VERSION 5.8 ;
BUSBITCHARS "[]" ;
DIVIDERCHAR "/" ;
UNITS
    DATABASE MICRONS 1000 ;
END UNITS

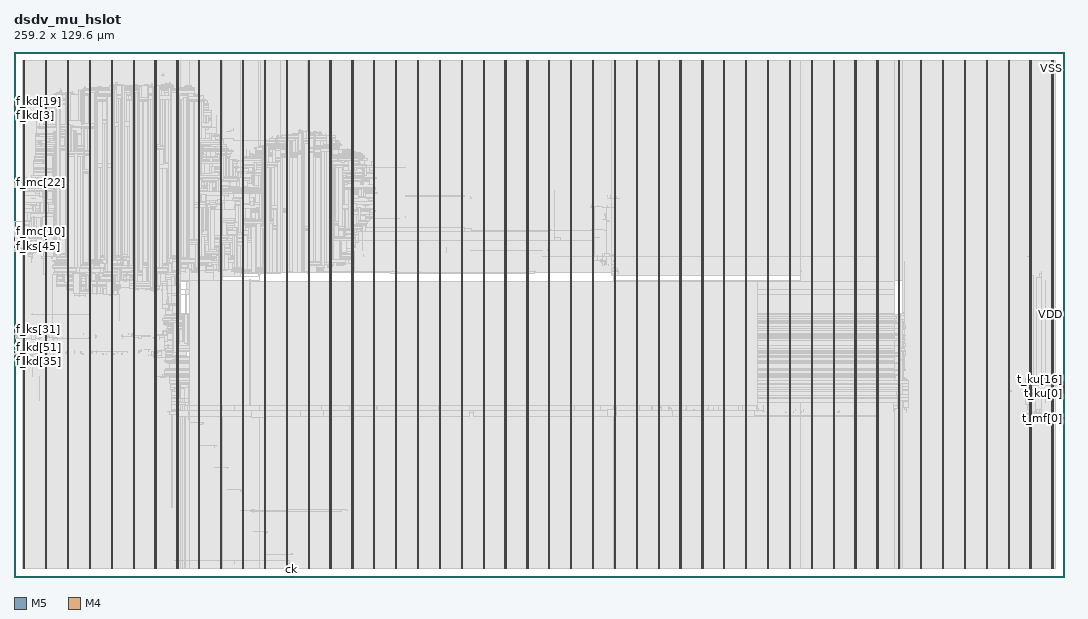
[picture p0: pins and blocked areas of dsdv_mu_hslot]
MACRO dsdv_mu_hslot
  FOREIGN dsdv_mu_hslot 0 0 ;
  CLASS BLOCK ;
  SIZE 259.2 BY 129.6 ;
  PIN ck
    DIRECTION INPUT ;
    USE SIGNAL ;
    PORT
      LAYER M5 ;
        RECT  68.496 0 68.52 0.084 ;
    END
  END ck
  PIN f_kd[0]
    DIRECTION INPUT ;
    USE SIGNAL ;
    PORT
      LAYER M4 ;
        RECT  0 113.52 0.084 113.544 ;
    END
  END f_kd[0]
  PIN f_kd[10]
    DIRECTION INPUT ;
    USE SIGNAL ;
    PORT
      LAYER M4 ;
        RECT  0 114.48 0.084 114.504 ;
    END
  END f_kd[10]
  PIN f_kd[11]
    DIRECTION INPUT ;
    USE SIGNAL ;
    PORT
      LAYER M4 ;
        RECT  0 114.576 0.084 114.6 ;
    END
  END f_kd[11]
  PIN f_kd[12]
    DIRECTION INPUT ;
    USE SIGNAL ;
    PORT
      LAYER M4 ;
        RECT  0 114.672 0.084 114.696 ;
    END
  END f_kd[12]
  PIN f_kd[13]
    DIRECTION INPUT ;
    USE SIGNAL ;
    PORT
      LAYER M4 ;
        RECT  0 114.768 0.084 114.792 ;
    END
  END f_kd[13]
  PIN f_kd[14]
    DIRECTION INPUT ;
    USE SIGNAL ;
    PORT
      LAYER M4 ;
        RECT  0 114.864 0.084 114.888 ;
    END
  END f_kd[14]
  PIN f_kd[15]
    DIRECTION INPUT ;
    USE SIGNAL ;
    PORT
      LAYER M4 ;
        RECT  0 114.96 0.084 114.984 ;
    END
  END f_kd[15]
  PIN f_kd[16]
    DIRECTION INPUT ;
    USE SIGNAL ;
    PORT
      LAYER M4 ;
        RECT  0 115.056 0.084 115.08 ;
    END
  END f_kd[16]
  PIN f_kd[17]
    DIRECTION INPUT ;
    USE SIGNAL ;
    PORT
      LAYER M4 ;
        RECT  0 115.152 0.084 115.176 ;
    END
  END f_kd[17]
  PIN f_kd[18]
    DIRECTION INPUT ;
    USE SIGNAL ;
    PORT
      LAYER M4 ;
        RECT  0 115.248 0.084 115.272 ;
    END
  END f_kd[18]
  PIN f_kd[19]
    DIRECTION INPUT ;
    USE SIGNAL ;
    PORT
      LAYER M4 ;
        RECT  0 115.344 0.084 115.368 ;
    END
  END f_kd[19]
  PIN f_kd[1]
    DIRECTION INPUT ;
    USE SIGNAL ;
    PORT
      LAYER M4 ;
        RECT  0 113.616 0.084 113.64 ;
    END
  END f_kd[1]
  PIN f_kd[20]
    DIRECTION INPUT ;
    USE SIGNAL ;
    PORT
      LAYER M4 ;
        RECT  0 115.44 0.084 115.464 ;
    END
  END f_kd[20]
  PIN f_kd[21]
    DIRECTION INPUT ;
    USE SIGNAL ;
    PORT
      LAYER M4 ;
        RECT  0 115.536 0.084 115.56 ;
    END
  END f_kd[21]
  PIN f_kd[22]
    DIRECTION INPUT ;
    USE SIGNAL ;
    PORT
      LAYER M4 ;
        RECT  0 115.632 0.084 115.656 ;
    END
  END f_kd[22]
  PIN f_kd[23]
    DIRECTION INPUT ;
    USE SIGNAL ;
    PORT
      LAYER M4 ;
        RECT  0 115.728 0.084 115.752 ;
    END
  END f_kd[23]
  PIN f_kd[24]
    DIRECTION INPUT ;
    USE SIGNAL ;
    PORT
      LAYER M4 ;
        RECT  0 115.824 0.084 115.848 ;
    END
  END f_kd[24]
  PIN f_kd[25]
    DIRECTION INPUT ;
    USE SIGNAL ;
    PORT
      LAYER M4 ;
        RECT  0 115.92 0.084 115.944 ;
    END
  END f_kd[25]
  PIN f_kd[26]
    DIRECTION INPUT ;
    USE SIGNAL ;
    PORT
      LAYER M4 ;
        RECT  0 116.016 0.084 116.04 ;
    END
  END f_kd[26]
  PIN f_kd[27]
    DIRECTION INPUT ;
    USE SIGNAL ;
    PORT
      LAYER M4 ;
        RECT  0 116.112 0.084 116.136 ;
    END
  END f_kd[27]
  PIN f_kd[28]
    DIRECTION INPUT ;
    USE SIGNAL ;
    PORT
      LAYER M4 ;
        RECT  0 116.208 0.084 116.232 ;
    END
  END f_kd[28]
  PIN f_kd[29]
    DIRECTION INPUT ;
    USE SIGNAL ;
    PORT
      LAYER M4 ;
        RECT  0 116.304 0.084 116.328 ;
    END
  END f_kd[29]
  PIN f_kd[2]
    DIRECTION INPUT ;
    USE SIGNAL ;
    PORT
      LAYER M4 ;
        RECT  0 113.712 0.084 113.736 ;
    END
  END f_kd[2]
  PIN f_kd[30]
    DIRECTION INPUT ;
    USE SIGNAL ;
    PORT
      LAYER M4 ;
        RECT  0 116.4 0.084 116.424 ;
    END
  END f_kd[30]
  PIN f_kd[31]
    DIRECTION INPUT ;
    USE SIGNAL ;
    PORT
      LAYER M4 ;
        RECT  0 116.496 0.084 116.52 ;
    END
  END f_kd[31]
  PIN f_kd[32]
    DIRECTION INPUT ;
    USE SIGNAL ;
    PORT
      LAYER M4 ;
        RECT  0 52.848 0.084 52.872 ;
    END
  END f_kd[32]
  PIN f_kd[33]
    DIRECTION INPUT ;
    USE SIGNAL ;
    PORT
      LAYER M4 ;
        RECT  0 52.944 0.084 52.968 ;
    END
  END f_kd[33]
  PIN f_kd[34]
    DIRECTION INPUT ;
    USE SIGNAL ;
    PORT
      LAYER M4 ;
        RECT  0 53.04 0.084 53.064 ;
    END
  END f_kd[34]
  PIN f_kd[35]
    DIRECTION INPUT ;
    USE SIGNAL ;
    PORT
      LAYER M4 ;
        RECT  0 53.136 0.084 53.16 ;
    END
  END f_kd[35]
  PIN f_kd[36]
    DIRECTION INPUT ;
    USE SIGNAL ;
    PORT
      LAYER M4 ;
        RECT  0 53.232 0.084 53.256 ;
    END
  END f_kd[36]
  PIN f_kd[37]
    DIRECTION INPUT ;
    USE SIGNAL ;
    PORT
      LAYER M4 ;
        RECT  0 53.328 0.084 53.352 ;
    END
  END f_kd[37]
  PIN f_kd[38]
    DIRECTION INPUT ;
    USE SIGNAL ;
    PORT
      LAYER M4 ;
        RECT  0 53.424 0.084 53.448 ;
    END
  END f_kd[38]
  PIN f_kd[39]
    DIRECTION INPUT ;
    USE SIGNAL ;
    PORT
      LAYER M4 ;
        RECT  0 53.52 0.084 53.544 ;
    END
  END f_kd[39]
  PIN f_kd[3]
    DIRECTION INPUT ;
    USE SIGNAL ;
    PORT
      LAYER M4 ;
        RECT  0 113.808 0.084 113.832 ;
    END
  END f_kd[3]
  PIN f_kd[40]
    DIRECTION INPUT ;
    USE SIGNAL ;
    PORT
      LAYER M4 ;
        RECT  0 53.616 0.084 53.64 ;
    END
  END f_kd[40]
  PIN f_kd[41]
    DIRECTION INPUT ;
    USE SIGNAL ;
    PORT
      LAYER M4 ;
        RECT  0 53.712 0.084 53.736 ;
    END
  END f_kd[41]
  PIN f_kd[42]
    DIRECTION INPUT ;
    USE SIGNAL ;
    PORT
      LAYER M4 ;
        RECT  0 53.808 0.084 53.832 ;
    END
  END f_kd[42]
  PIN f_kd[43]
    DIRECTION INPUT ;
    USE SIGNAL ;
    PORT
      LAYER M4 ;
        RECT  0 53.904 0.084 53.928 ;
    END
  END f_kd[43]
  PIN f_kd[44]
    DIRECTION INPUT ;
    USE SIGNAL ;
    PORT
      LAYER M4 ;
        RECT  0 54 0.084 54.024 ;
    END
  END f_kd[44]
  PIN f_kd[45]
    DIRECTION INPUT ;
    USE SIGNAL ;
    PORT
      LAYER M4 ;
        RECT  0 54.096 0.084 54.12 ;
    END
  END f_kd[45]
  PIN f_kd[46]
    DIRECTION INPUT ;
    USE SIGNAL ;
    PORT
      LAYER M4 ;
        RECT  0 54.192 0.084 54.216 ;
    END
  END f_kd[46]
  PIN f_kd[47]
    DIRECTION INPUT ;
    USE SIGNAL ;
    PORT
      LAYER M4 ;
        RECT  0 54.288 0.084 54.312 ;
    END
  END f_kd[47]
  PIN f_kd[48]
    DIRECTION INPUT ;
    USE SIGNAL ;
    PORT
      LAYER M4 ;
        RECT  0 54.384 0.084 54.408 ;
    END
  END f_kd[48]
  PIN f_kd[49]
    DIRECTION INPUT ;
    USE SIGNAL ;
    PORT
      LAYER M4 ;
        RECT  0 54.48 0.084 54.504 ;
    END
  END f_kd[49]
  PIN f_kd[4]
    DIRECTION INPUT ;
    USE SIGNAL ;
    PORT
      LAYER M4 ;
        RECT  0 113.904 0.084 113.928 ;
    END
  END f_kd[4]
  PIN f_kd[50]
    DIRECTION INPUT ;
    USE SIGNAL ;
    PORT
      LAYER M4 ;
        RECT  0 54.576 0.084 54.6 ;
    END
  END f_kd[50]
  PIN f_kd[51]
    DIRECTION INPUT ;
    USE SIGNAL ;
    PORT
      LAYER M4 ;
        RECT  0 54.672 0.084 54.696 ;
    END
  END f_kd[51]
  PIN f_kd[52]
    DIRECTION INPUT ;
    USE SIGNAL ;
    PORT
      LAYER M4 ;
        RECT  0 54.768 0.084 54.792 ;
    END
  END f_kd[52]
  PIN f_kd[53]
    DIRECTION INPUT ;
    USE SIGNAL ;
    PORT
      LAYER M4 ;
        RECT  0 54.864 0.084 54.888 ;
    END
  END f_kd[53]
  PIN f_kd[5]
    DIRECTION INPUT ;
    USE SIGNAL ;
    PORT
      LAYER M4 ;
        RECT  0 114 0.084 114.024 ;
    END
  END f_kd[5]
  PIN f_kd[6]
    DIRECTION INPUT ;
    USE SIGNAL ;
    PORT
      LAYER M4 ;
        RECT  0 114.096 0.084 114.12 ;
    END
  END f_kd[6]
  PIN f_kd[7]
    DIRECTION INPUT ;
    USE SIGNAL ;
    PORT
      LAYER M4 ;
        RECT  0 114.192 0.084 114.216 ;
    END
  END f_kd[7]
  PIN f_kd[8]
    DIRECTION INPUT ;
    USE SIGNAL ;
    PORT
      LAYER M4 ;
        RECT  0 114.288 0.084 114.312 ;
    END
  END f_kd[8]
  PIN f_kd[9]
    DIRECTION INPUT ;
    USE SIGNAL ;
    PORT
      LAYER M4 ;
        RECT  0 114.384 0.084 114.408 ;
    END
  END f_kd[9]
  PIN f_ks[0]
    DIRECTION INPUT ;
    USE SIGNAL ;
    PORT
      LAYER M4 ;
        RECT  0 54.96 0.084 54.984 ;
    END
  END f_ks[0]
  PIN f_ks[10]
    DIRECTION INPUT ;
    USE SIGNAL ;
    PORT
      LAYER M4 ;
        RECT  0 58.992 0.084 59.016 ;
    END
  END f_ks[10]
  PIN f_ks[11]
    DIRECTION INPUT ;
    USE SIGNAL ;
    PORT
      LAYER M4 ;
        RECT  0 59.088 0.084 59.112 ;
    END
  END f_ks[11]
  PIN f_ks[12]
    DIRECTION INPUT ;
    USE SIGNAL ;
    PORT
      LAYER M4 ;
        RECT  0 59.184 0.084 59.208 ;
    END
  END f_ks[12]
  PIN f_ks[13]
    DIRECTION INPUT ;
    USE SIGNAL ;
    PORT
      LAYER M4 ;
        RECT  0 59.28 0.084 59.304 ;
    END
  END f_ks[13]
  PIN f_ks[14]
    DIRECTION INPUT ;
    USE SIGNAL ;
    PORT
      LAYER M4 ;
        RECT  0 59.376 0.084 59.4 ;
    END
  END f_ks[14]
  PIN f_ks[15]
    DIRECTION INPUT ;
    USE SIGNAL ;
    PORT
      LAYER M4 ;
        RECT  0 59.472 0.084 59.496 ;
    END
  END f_ks[15]
  PIN f_ks[16]
    DIRECTION INPUT ;
    USE SIGNAL ;
    PORT
      LAYER M4 ;
        RECT  0 59.568 0.084 59.592 ;
    END
  END f_ks[16]
  PIN f_ks[17]
    DIRECTION INPUT ;
    USE SIGNAL ;
    PORT
      LAYER M4 ;
        RECT  0 59.664 0.084 59.688 ;
    END
  END f_ks[17]
  PIN f_ks[18]
    DIRECTION INPUT ;
    USE SIGNAL ;
    PORT
      LAYER M4 ;
        RECT  0 59.76 0.084 59.784 ;
    END
  END f_ks[18]
  PIN f_ks[19]
    DIRECTION INPUT ;
    USE SIGNAL ;
    PORT
      LAYER M4 ;
        RECT  0 59.856 0.084 59.88 ;
    END
  END f_ks[19]
  PIN f_ks[1]
    DIRECTION INPUT ;
    USE SIGNAL ;
    PORT
      LAYER M4 ;
        RECT  0 55.056 0.084 55.08 ;
    END
  END f_ks[1]
  PIN f_ks[20]
    DIRECTION INPUT ;
    USE SIGNAL ;
    PORT
      LAYER M4 ;
        RECT  0 59.952 0.084 59.976 ;
    END
  END f_ks[20]
  PIN f_ks[21]
    DIRECTION INPUT ;
    USE SIGNAL ;
    PORT
      LAYER M4 ;
        RECT  0 60.048 0.084 60.072 ;
    END
  END f_ks[21]
  PIN f_ks[22]
    DIRECTION INPUT ;
    USE SIGNAL ;
    PORT
      LAYER M4 ;
        RECT  0 60.144 0.084 60.168 ;
    END
  END f_ks[22]
  PIN f_ks[23]
    DIRECTION INPUT ;
    USE SIGNAL ;
    PORT
      LAYER M4 ;
        RECT  0 60.24 0.084 60.264 ;
    END
  END f_ks[23]
  PIN f_ks[24]
    DIRECTION INPUT ;
    USE SIGNAL ;
    PORT
      LAYER M4 ;
        RECT  0 60.336 0.084 60.36 ;
    END
  END f_ks[24]
  PIN f_ks[25]
    DIRECTION INPUT ;
    USE SIGNAL ;
    PORT
      LAYER M4 ;
        RECT  0 60.432 0.084 60.456 ;
    END
  END f_ks[25]
  PIN f_ks[26]
    DIRECTION INPUT ;
    USE SIGNAL ;
    PORT
      LAYER M4 ;
        RECT  0 60.528 0.084 60.552 ;
    END
  END f_ks[26]
  PIN f_ks[27]
    DIRECTION INPUT ;
    USE SIGNAL ;
    PORT
      LAYER M4 ;
        RECT  0 60.624 0.084 60.648 ;
    END
  END f_ks[27]
  PIN f_ks[28]
    DIRECTION INPUT ;
    USE SIGNAL ;
    PORT
      LAYER M4 ;
        RECT  0 60.72 0.084 60.744 ;
    END
  END f_ks[28]
  PIN f_ks[29]
    DIRECTION INPUT ;
    USE SIGNAL ;
    PORT
      LAYER M4 ;
        RECT  0 60.816 0.084 60.84 ;
    END
  END f_ks[29]
  PIN f_ks[2]
    DIRECTION INPUT ;
    USE SIGNAL ;
    PORT
      LAYER M4 ;
        RECT  0 55.152 0.084 55.176 ;
    END
  END f_ks[2]
  PIN f_ks[30]
    DIRECTION INPUT ;
    USE SIGNAL ;
    PORT
      LAYER M4 ;
        RECT  0 60.912 0.084 60.936 ;
    END
  END f_ks[30]
  PIN f_ks[31]
    DIRECTION INPUT ;
    USE SIGNAL ;
    PORT
      LAYER M4 ;
        RECT  0 61.008 0.084 61.032 ;
    END
  END f_ks[31]
  PIN f_ks[32]
    DIRECTION INPUT ;
    USE SIGNAL ;
    PORT
      LAYER M4 ;
        RECT  0 61.104 0.084 61.128 ;
    END
  END f_ks[32]
  PIN f_ks[33]
    DIRECTION INPUT ;
    USE SIGNAL ;
    PORT
      LAYER M4 ;
        RECT  0 61.2 0.084 61.224 ;
    END
  END f_ks[33]
  PIN f_ks[34]
    DIRECTION INPUT ;
    USE SIGNAL ;
    PORT
      LAYER M4 ;
        RECT  0 61.296 0.084 61.32 ;
    END
  END f_ks[34]
  PIN f_ks[35]
    DIRECTION INPUT ;
    USE SIGNAL ;
    PORT
      LAYER M4 ;
        RECT  0 61.392 0.084 61.416 ;
    END
  END f_ks[35]
  PIN f_ks[36]
    DIRECTION INPUT ;
    USE SIGNAL ;
    PORT
      LAYER M4 ;
        RECT  0 61.488 0.084 61.512 ;
    END
  END f_ks[36]
  PIN f_ks[37]
    DIRECTION INPUT ;
    USE SIGNAL ;
    PORT
      LAYER M4 ;
        RECT  0 61.584 0.084 61.608 ;
    END
  END f_ks[37]
  PIN f_ks[38]
    DIRECTION INPUT ;
    USE SIGNAL ;
    PORT
      LAYER M4 ;
        RECT  0 61.68 0.084 61.704 ;
    END
  END f_ks[38]
  PIN f_ks[39]
    DIRECTION INPUT ;
    USE SIGNAL ;
    PORT
      LAYER M4 ;
        RECT  0 61.776 0.084 61.8 ;
    END
  END f_ks[39]
  PIN f_ks[3]
    DIRECTION INPUT ;
    USE SIGNAL ;
    PORT
      LAYER M4 ;
        RECT  0 55.248 0.084 55.272 ;
    END
  END f_ks[3]
  PIN f_ks[40]
    DIRECTION INPUT ;
    USE SIGNAL ;
    PORT
      LAYER M4 ;
        RECT  0 61.872 0.084 61.896 ;
    END
  END f_ks[40]
  PIN f_ks[41]
    DIRECTION INPUT ;
    USE SIGNAL ;
    PORT
      LAYER M4 ;
        RECT  0 61.968 0.084 61.992 ;
    END
  END f_ks[41]
  PIN f_ks[42]
    DIRECTION INPUT ;
    USE SIGNAL ;
    PORT
      LAYER M4 ;
        RECT  0 81.264 0.084 81.288 ;
    END
  END f_ks[42]
  PIN f_ks[43]
    DIRECTION INPUT ;
    USE SIGNAL ;
    PORT
      LAYER M4 ;
        RECT  0 81.36 0.084 81.384 ;
    END
  END f_ks[43]
  PIN f_ks[44]
    DIRECTION INPUT ;
    USE SIGNAL ;
    PORT
      LAYER M4 ;
        RECT  0 81.456 0.084 81.48 ;
    END
  END f_ks[44]
  PIN f_ks[45]
    DIRECTION INPUT ;
    USE SIGNAL ;
    PORT
      LAYER M4 ;
        RECT  0 81.552 0.084 81.576 ;
    END
  END f_ks[45]
  PIN f_ks[46]
    DIRECTION INPUT ;
    USE SIGNAL ;
    PORT
      LAYER M4 ;
        RECT  0 81.648 0.084 81.672 ;
    END
  END f_ks[46]
  PIN f_ks[47]
    DIRECTION INPUT ;
    USE SIGNAL ;
    PORT
      LAYER M4 ;
        RECT  0 81.744 0.084 81.768 ;
    END
  END f_ks[47]
  PIN f_ks[48]
    DIRECTION INPUT ;
    USE SIGNAL ;
    PORT
      LAYER M4 ;
        RECT  0 81.84 0.084 81.864 ;
    END
  END f_ks[48]
  PIN f_ks[49]
    DIRECTION INPUT ;
    USE SIGNAL ;
    PORT
      LAYER M4 ;
        RECT  0 81.936 0.084 81.96 ;
    END
  END f_ks[49]
  PIN f_ks[4]
    DIRECTION INPUT ;
    USE SIGNAL ;
    PORT
      LAYER M4 ;
        RECT  0 55.344 0.084 55.368 ;
    END
  END f_ks[4]
  PIN f_ks[50]
    DIRECTION INPUT ;
    USE SIGNAL ;
    PORT
      LAYER M4 ;
        RECT  0 82.032 0.084 82.056 ;
    END
  END f_ks[50]
  PIN f_ks[51]
    DIRECTION INPUT ;
    USE SIGNAL ;
    PORT
      LAYER M4 ;
        RECT  0 82.128 0.084 82.152 ;
    END
  END f_ks[51]
  PIN f_ks[52]
    DIRECTION INPUT ;
    USE SIGNAL ;
    PORT
      LAYER M4 ;
        RECT  0 82.224 0.084 82.248 ;
    END
  END f_ks[52]
  PIN f_ks[5]
    DIRECTION INPUT ;
    USE SIGNAL ;
    PORT
      LAYER M4 ;
        RECT  0 55.44 0.084 55.464 ;
    END
  END f_ks[5]
  PIN f_ks[6]
    DIRECTION INPUT ;
    USE SIGNAL ;
    PORT
      LAYER M4 ;
        RECT  0 55.536 0.084 55.56 ;
    END
  END f_ks[6]
  PIN f_ks[7]
    DIRECTION INPUT ;
    USE SIGNAL ;
    PORT
      LAYER M4 ;
        RECT  0 55.632 0.084 55.656 ;
    END
  END f_ks[7]
  PIN f_ks[8]
    DIRECTION INPUT ;
    USE SIGNAL ;
    PORT
      LAYER M4 ;
        RECT  0 55.728 0.084 55.752 ;
    END
  END f_ks[8]
  PIN f_ks[9]
    DIRECTION INPUT ;
    USE SIGNAL ;
    PORT
      LAYER M4 ;
        RECT  0 55.824 0.084 55.848 ;
    END
  END f_ks[9]
  PIN f_mc[0]
    DIRECTION INPUT ;
    USE SIGNAL ;
    PORT
      LAYER M4 ;
        RECT  0 82.32 0.084 82.344 ;
    END
  END f_mc[0]
  PIN f_mc[10]
    DIRECTION INPUT ;
    USE SIGNAL ;
    PORT
      LAYER M4 ;
        RECT  0 83.28 0.084 83.304 ;
    END
  END f_mc[10]
  PIN f_mc[11]
    DIRECTION INPUT ;
    USE SIGNAL ;
    PORT
      LAYER M4 ;
        RECT  0 83.376 0.084 83.4 ;
    END
  END f_mc[11]
  PIN f_mc[12]
    DIRECTION INPUT ;
    USE SIGNAL ;
    PORT
      LAYER M4 ;
        RECT  0 83.472 0.084 83.496 ;
    END
  END f_mc[12]
  PIN f_mc[13]
    DIRECTION INPUT ;
    USE SIGNAL ;
    PORT
      LAYER M4 ;
        RECT  0 83.568 0.084 83.592 ;
    END
  END f_mc[13]
  PIN f_mc[14]
    DIRECTION INPUT ;
    USE SIGNAL ;
    PORT
      LAYER M4 ;
        RECT  0 83.664 0.084 83.688 ;
    END
  END f_mc[14]
  PIN f_mc[15]
    DIRECTION INPUT ;
    USE SIGNAL ;
    PORT
      LAYER M4 ;
        RECT  0 83.76 0.084 83.784 ;
    END
  END f_mc[15]
  PIN f_mc[16]
    DIRECTION INPUT ;
    USE SIGNAL ;
    PORT
      LAYER M4 ;
        RECT  0 83.856 0.084 83.88 ;
    END
  END f_mc[16]
  PIN f_mc[17]
    DIRECTION INPUT ;
    USE SIGNAL ;
    PORT
      LAYER M4 ;
        RECT  0 83.952 0.084 83.976 ;
    END
  END f_mc[17]
  PIN f_mc[18]
    DIRECTION INPUT ;
    USE SIGNAL ;
    PORT
      LAYER M4 ;
        RECT  0 84.048 0.084 84.072 ;
    END
  END f_mc[18]
  PIN f_mc[19]
    DIRECTION INPUT ;
    USE SIGNAL ;
    PORT
      LAYER M4 ;
        RECT  0 84.144 0.084 84.168 ;
    END
  END f_mc[19]
  PIN f_mc[1]
    DIRECTION INPUT ;
    USE SIGNAL ;
    PORT
      LAYER M4 ;
        RECT  0 82.416 0.084 82.44 ;
    END
  END f_mc[1]
  PIN f_mc[20]
    DIRECTION INPUT ;
    USE SIGNAL ;
    PORT
      LAYER M4 ;
        RECT  0 84.24 0.084 84.264 ;
    END
  END f_mc[20]
  PIN f_mc[21]
    DIRECTION INPUT ;
    USE SIGNAL ;
    PORT
      LAYER M4 ;
        RECT  0 97.2 0.084 97.224 ;
    END
  END f_mc[21]
  PIN f_mc[22]
    DIRECTION INPUT ;
    USE SIGNAL ;
    PORT
      LAYER M4 ;
        RECT  0 97.296 0.084 97.32 ;
    END
  END f_mc[22]
  PIN f_mc[23]
    DIRECTION INPUT ;
    USE SIGNAL ;
    PORT
      LAYER M4 ;
        RECT  0 97.392 0.084 97.416 ;
    END
  END f_mc[23]
  PIN f_mc[24]
    DIRECTION INPUT ;
    USE SIGNAL ;
    PORT
      LAYER M4 ;
        RECT  0 97.488 0.084 97.512 ;
    END
  END f_mc[24]
  PIN f_mc[25]
    DIRECTION INPUT ;
    USE SIGNAL ;
    PORT
      LAYER M4 ;
        RECT  0 97.584 0.084 97.608 ;
    END
  END f_mc[25]
  PIN f_mc[2]
    DIRECTION INPUT ;
    USE SIGNAL ;
    PORT
      LAYER M4 ;
        RECT  0 82.512 0.084 82.536 ;
    END
  END f_mc[2]
  PIN f_mc[3]
    DIRECTION INPUT ;
    USE SIGNAL ;
    PORT
      LAYER M4 ;
        RECT  0 82.608 0.084 82.632 ;
    END
  END f_mc[3]
  PIN f_mc[4]
    DIRECTION INPUT ;
    USE SIGNAL ;
    PORT
      LAYER M4 ;
        RECT  0 82.704 0.084 82.728 ;
    END
  END f_mc[4]
  PIN f_mc[5]
    DIRECTION INPUT ;
    USE SIGNAL ;
    PORT
      LAYER M4 ;
        RECT  0 82.8 0.084 82.824 ;
    END
  END f_mc[5]
  PIN f_mc[6]
    DIRECTION INPUT ;
    USE SIGNAL ;
    PORT
      LAYER M4 ;
        RECT  0 82.896 0.084 82.92 ;
    END
  END f_mc[6]
  PIN f_mc[7]
    DIRECTION INPUT ;
    USE SIGNAL ;
    PORT
      LAYER M4 ;
        RECT  0 82.992 0.084 83.016 ;
    END
  END f_mc[7]
  PIN f_mc[8]
    DIRECTION INPUT ;
    USE SIGNAL ;
    PORT
      LAYER M4 ;
        RECT  0 83.088 0.084 83.112 ;
    END
  END f_mc[8]
  PIN f_mc[9]
    DIRECTION INPUT ;
    USE SIGNAL ;
    PORT
      LAYER M4 ;
        RECT  0 83.184 0.084 83.208 ;
    END
  END f_mc[9]
  PIN rst_n
    DIRECTION INPUT ;
    USE SIGNAL ;
    PORT
      LAYER M5 ;
        RECT  68.592 0 68.616 0.084 ;
    END
  END rst_n
  PIN t_ku[0]
    DIRECTION OUTPUT ;
    USE SIGNAL ;
    PORT
      LAYER M4 ;
        RECT  259.116 45.264 259.2 45.288 ;
    END
  END t_ku[0]
  PIN t_ku[10]
    DIRECTION OUTPUT ;
    USE SIGNAL ;
    PORT
      LAYER M4 ;
        RECT  259.116 46.224 259.2 46.248 ;
    END
  END t_ku[10]
  PIN t_ku[11]
    DIRECTION OUTPUT ;
    USE SIGNAL ;
    PORT
      LAYER M4 ;
        RECT  259.116 46.32 259.2 46.344 ;
    END
  END t_ku[11]
  PIN t_ku[12]
    DIRECTION OUTPUT ;
    USE SIGNAL ;
    PORT
      LAYER M4 ;
        RECT  259.116 46.416 259.2 46.44 ;
    END
  END t_ku[12]
  PIN t_ku[13]
    DIRECTION OUTPUT ;
    USE SIGNAL ;
    PORT
      LAYER M4 ;
        RECT  259.116 46.512 259.2 46.536 ;
    END
  END t_ku[13]
  PIN t_ku[14]
    DIRECTION OUTPUT ;
    USE SIGNAL ;
    PORT
      LAYER M4 ;
        RECT  259.116 46.608 259.2 46.632 ;
    END
  END t_ku[14]
  PIN t_ku[15]
    DIRECTION OUTPUT ;
    USE SIGNAL ;
    PORT
      LAYER M4 ;
        RECT  259.116 46.704 259.2 46.728 ;
    END
  END t_ku[15]
  PIN t_ku[16]
    DIRECTION OUTPUT ;
    USE SIGNAL ;
    PORT
      LAYER M4 ;
        RECT  259.116 46.8 259.2 46.824 ;
    END
  END t_ku[16]
  PIN t_ku[17]
    DIRECTION OUTPUT ;
    USE SIGNAL ;
    PORT
      LAYER M4 ;
        RECT  259.116 46.896 259.2 46.92 ;
    END
  END t_ku[17]
  PIN t_ku[18]
    DIRECTION OUTPUT ;
    USE SIGNAL ;
    PORT
      LAYER M4 ;
        RECT  259.116 46.992 259.2 47.016 ;
    END
  END t_ku[18]
  PIN t_ku[19]
    DIRECTION OUTPUT ;
    USE SIGNAL ;
    PORT
      LAYER M4 ;
        RECT  259.116 47.088 259.2 47.112 ;
    END
  END t_ku[19]
  PIN t_ku[1]
    DIRECTION OUTPUT ;
    USE SIGNAL ;
    PORT
      LAYER M4 ;
        RECT  259.116 45.36 259.2 45.384 ;
    END
  END t_ku[1]
  PIN t_ku[20]
    DIRECTION OUTPUT ;
    USE SIGNAL ;
    PORT
      LAYER M4 ;
        RECT  259.116 47.184 259.2 47.208 ;
    END
  END t_ku[20]
  PIN t_ku[21]
    DIRECTION OUTPUT ;
    USE SIGNAL ;
    PORT
      LAYER M4 ;
        RECT  259.116 47.28 259.2 47.304 ;
    END
  END t_ku[21]
  PIN t_ku[22]
    DIRECTION OUTPUT ;
    USE SIGNAL ;
    PORT
      LAYER M4 ;
        RECT  259.116 47.376 259.2 47.4 ;
    END
  END t_ku[22]
  PIN t_ku[23]
    DIRECTION OUTPUT ;
    USE SIGNAL ;
    PORT
      LAYER M4 ;
        RECT  259.116 47.472 259.2 47.496 ;
    END
  END t_ku[23]
  PIN t_ku[24]
    DIRECTION OUTPUT ;
    USE SIGNAL ;
    PORT
      LAYER M4 ;
        RECT  259.116 47.568 259.2 47.592 ;
    END
  END t_ku[24]
  PIN t_ku[25]
    DIRECTION OUTPUT ;
    USE SIGNAL ;
    PORT
      LAYER M4 ;
        RECT  259.116 47.664 259.2 47.688 ;
    END
  END t_ku[25]
  PIN t_ku[26]
    DIRECTION OUTPUT ;
    USE SIGNAL ;
    PORT
      LAYER M4 ;
        RECT  259.116 47.76 259.2 47.784 ;
    END
  END t_ku[26]
  PIN t_ku[27]
    DIRECTION OUTPUT ;
    USE SIGNAL ;
    PORT
      LAYER M4 ;
        RECT  259.116 47.856 259.2 47.88 ;
    END
  END t_ku[27]
  PIN t_ku[28]
    DIRECTION OUTPUT ;
    USE SIGNAL ;
    PORT
      LAYER M4 ;
        RECT  259.116 47.952 259.2 47.976 ;
    END
  END t_ku[28]
  PIN t_ku[29]
    DIRECTION OUTPUT ;
    USE SIGNAL ;
    PORT
      LAYER M4 ;
        RECT  259.116 48.048 259.2 48.072 ;
    END
  END t_ku[29]
  PIN t_ku[2]
    DIRECTION OUTPUT ;
    USE SIGNAL ;
    PORT
      LAYER M4 ;
        RECT  259.116 45.456 259.2 45.48 ;
    END
  END t_ku[2]
  PIN t_ku[30]
    DIRECTION OUTPUT ;
    USE SIGNAL ;
    PORT
      LAYER M4 ;
        RECT  259.116 48.144 259.2 48.168 ;
    END
  END t_ku[30]
  PIN t_ku[31]
    DIRECTION OUTPUT ;
    USE SIGNAL ;
    PORT
      LAYER M4 ;
        RECT  259.116 48.24 259.2 48.264 ;
    END
  END t_ku[31]
  PIN t_ku[3]
    DIRECTION OUTPUT ;
    USE SIGNAL ;
    PORT
      LAYER M4 ;
        RECT  259.116 45.552 259.2 45.576 ;
    END
  END t_ku[3]
  PIN t_ku[4]
    DIRECTION OUTPUT ;
    USE SIGNAL ;
    PORT
      LAYER M4 ;
        RECT  259.116 45.648 259.2 45.672 ;
    END
  END t_ku[4]
  PIN t_ku[5]
    DIRECTION OUTPUT ;
    USE SIGNAL ;
    PORT
      LAYER M4 ;
        RECT  259.116 45.744 259.2 45.768 ;
    END
  END t_ku[5]
  PIN t_ku[6]
    DIRECTION OUTPUT ;
    USE SIGNAL ;
    PORT
      LAYER M4 ;
        RECT  259.116 45.84 259.2 45.864 ;
    END
  END t_ku[6]
  PIN t_ku[7]
    DIRECTION OUTPUT ;
    USE SIGNAL ;
    PORT
      LAYER M4 ;
        RECT  259.116 45.936 259.2 45.96 ;
    END
  END t_ku[7]
  PIN t_ku[8]
    DIRECTION OUTPUT ;
    USE SIGNAL ;
    PORT
      LAYER M4 ;
        RECT  259.116 46.032 259.2 46.056 ;
    END
  END t_ku[8]
  PIN t_ku[9]
    DIRECTION OUTPUT ;
    USE SIGNAL ;
    PORT
      LAYER M4 ;
        RECT  259.116 46.128 259.2 46.152 ;
    END
  END t_ku[9]
  PIN t_mf[0]
    DIRECTION OUTPUT ;
    USE SIGNAL ;
    PORT
      LAYER M4 ;
        RECT  259.116 39.12 259.2 39.144 ;
    END
  END t_mf[0]
  PIN t_mf[1]
    DIRECTION OUTPUT ;
    USE SIGNAL ;
    PORT
      LAYER M4 ;
        RECT  259.116 39.216 259.2 39.24 ;
    END
  END t_mf[1]
  PIN t_mf[2]
    DIRECTION OUTPUT ;
    USE SIGNAL ;
    PORT
      LAYER M4 ;
        RECT  259.116 39.312 259.2 39.336 ;
    END
  END t_mf[2]
  PIN t_mf[3]
    DIRECTION OUTPUT ;
    USE SIGNAL ;
    PORT
      LAYER M4 ;
        RECT  259.116 39.408 259.2 39.432 ;
    END
  END t_mf[3]
  PIN VDD
    DIRECTION INOUT ;
    USE POWER ;
    PORT
      LAYER M5 ;
        RECT  256.392 2.151 256.512 127.449 ;
        RECT  250.992 2.151 251.112 127.449 ;
        RECT  245.592 2.151 245.712 127.449 ;
        RECT  240.192 2.151 240.312 127.449 ;
        RECT  234.792 2.151 234.912 127.449 ;
        RECT  229.392 2.151 229.512 127.449 ;
        RECT  223.992 2.151 224.112 127.449 ;
        RECT  218.592 2.151 218.712 127.449 ;
        RECT  213.192 2.151 213.312 127.449 ;
        RECT  207.792 2.151 207.912 127.449 ;
        RECT  202.392 2.151 202.512 127.449 ;
        RECT  196.992 2.151 197.112 127.449 ;
        RECT  191.592 2.151 191.712 127.449 ;
        RECT  186.192 2.151 186.312 127.449 ;
        RECT  180.792 2.151 180.912 127.449 ;
        RECT  175.392 2.151 175.512 127.449 ;
        RECT  169.992 2.151 170.112 127.449 ;
        RECT  164.592 2.151 164.712 127.449 ;
        RECT  159.192 2.151 159.312 127.449 ;
        RECT  153.792 2.151 153.912 127.449 ;
        RECT  148.392 2.151 148.512 127.449 ;
        RECT  142.992 2.151 143.112 127.449 ;
        RECT  137.592 2.151 137.712 127.449 ;
        RECT  132.192 2.151 132.312 127.449 ;
        RECT  126.792 2.151 126.912 127.449 ;
        RECT  121.392 2.151 121.512 127.449 ;
        RECT  115.992 2.151 116.112 127.449 ;
        RECT  110.592 2.151 110.712 127.449 ;
        RECT  105.192 2.151 105.312 127.449 ;
        RECT  99.792 2.151 99.912 127.449 ;
        RECT  94.392 2.151 94.512 127.449 ;
        RECT  88.992 2.151 89.112 127.449 ;
        RECT  83.592 2.151 83.712 127.449 ;
        RECT  78.192 2.151 78.312 127.449 ;
        RECT  72.792 2.151 72.912 127.449 ;
        RECT  67.392 2.151 67.512 127.449 ;
        RECT  61.992 2.151 62.112 127.449 ;
        RECT  56.592 2.151 56.712 127.449 ;
        RECT  51.192 2.151 51.312 127.449 ;
        RECT  45.792 2.151 45.912 127.449 ;
        RECT  40.392 2.151 40.512 127.449 ;
        RECT  34.992 2.151 35.112 127.449 ;
        RECT  29.592 2.151 29.712 127.449 ;
        RECT  24.192 2.151 24.312 127.449 ;
        RECT  18.792 2.151 18.912 127.449 ;
        RECT  13.392 2.151 13.512 127.449 ;
        RECT  7.992 2.151 8.112 127.449 ;
        RECT  2.592 2.151 2.712 127.449 ;
    END
  END VDD
  PIN VSS
    DIRECTION INOUT ;
    USE GROUND ;
    PORT
      LAYER M5 ;
        RECT  256.2 2.137 256.32 127.463 ;
        RECT  250.8 2.137 250.92 127.463 ;
        RECT  245.4 2.137 245.52 127.463 ;
        RECT  240 2.137 240.12 127.463 ;
        RECT  234.6 2.137 234.72 127.463 ;
        RECT  229.2 2.137 229.32 127.463 ;
        RECT  223.8 2.137 223.92 127.463 ;
        RECT  218.4 2.137 218.52 127.463 ;
        RECT  213 2.137 213.12 127.463 ;
        RECT  207.6 2.137 207.72 127.463 ;
        RECT  202.2 2.137 202.32 127.463 ;
        RECT  196.8 2.137 196.92 127.463 ;
        RECT  191.4 2.137 191.52 127.463 ;
        RECT  186 2.137 186.12 127.463 ;
        RECT  180.6 2.137 180.72 127.463 ;
        RECT  175.2 2.137 175.32 127.463 ;
        RECT  169.8 2.137 169.92 127.463 ;
        RECT  164.4 2.137 164.52 127.463 ;
        RECT  159 2.137 159.12 127.463 ;
        RECT  153.6 2.137 153.72 127.463 ;
        RECT  148.2 2.137 148.32 127.463 ;
        RECT  142.8 2.137 142.92 127.463 ;
        RECT  137.4 2.137 137.52 127.463 ;
        RECT  132 2.137 132.12 127.463 ;
        RECT  126.6 2.137 126.72 127.463 ;
        RECT  121.2 2.137 121.32 127.463 ;
        RECT  115.8 2.137 115.92 127.463 ;
        RECT  110.4 2.137 110.52 127.463 ;
        RECT  105 2.137 105.12 127.463 ;
        RECT  99.6 2.137 99.72 127.463 ;
        RECT  94.2 2.137 94.32 127.463 ;
        RECT  88.8 2.137 88.92 127.463 ;
        RECT  83.4 2.137 83.52 127.463 ;
        RECT  78 2.137 78.12 127.463 ;
        RECT  72.6 2.137 72.72 127.463 ;
        RECT  67.2 2.137 67.32 127.463 ;
        RECT  61.8 2.137 61.92 127.463 ;
        RECT  56.4 2.137 56.52 127.463 ;
        RECT  51 2.137 51.12 127.463 ;
        RECT  45.6 2.137 45.72 127.463 ;
        RECT  40.2 2.137 40.32 127.463 ;
        RECT  34.8 2.137 34.92 127.463 ;
        RECT  29.4 2.137 29.52 127.463 ;
        RECT  24 2.137 24.12 127.463 ;
        RECT  18.6 2.137 18.72 127.463 ;
        RECT  13.2 2.137 13.32 127.463 ;
        RECT  7.8 2.137 7.92 127.463 ;
        RECT  2.4 2.137 2.52 127.463 ;
    END
  END VSS
  # OT_OBS_CLOSED layer=M5 d_um=1.536 added=462
  OBS
    LAYER RVTN ;
     RECT  2.16 2.16 257.04 2.295 ;
     RECT  2.16 2.565 257.04 2.835 ;
     RECT  2.16 3.105 257.04 3.375 ;
     RECT  2.16 3.645 257.04 3.915 ;
     RECT  2.16 4.185 257.04 4.455 ;
     RECT  2.16 4.725 257.04 4.995 ;
     RECT  2.16 5.265 257.04 5.535 ;
     RECT  2.16 5.805 257.04 6.075 ;
     RECT  2.16 6.345 257.04 6.615 ;
     RECT  2.16 6.885 257.04 7.155 ;
     RECT  2.16 7.425 257.04 7.695 ;
     RECT  2.16 7.965 257.04 8.235 ;
     RECT  2.16 8.505 257.04 8.775 ;
     RECT  2.16 9.045 257.04 9.315 ;
     RECT  2.16 9.585 257.04 9.855 ;
     RECT  2.16 10.125 257.04 10.395 ;
     RECT  2.16 10.665 257.04 10.935 ;
     RECT  2.16 11.205 257.04 11.475 ;
     RECT  2.16 11.745 257.04 12.015 ;
     RECT  2.16 12.285 257.04 12.555 ;
     RECT  2.16 12.825 257.04 13.095 ;
     RECT  2.16 13.365 257.04 13.635 ;
     RECT  2.16 13.905 257.04 14.175 ;
     RECT  2.16 14.445 257.04 14.715 ;
     RECT  2.16 14.985 257.04 15.255 ;
     RECT  2.16 15.525 257.04 15.795 ;
     RECT  2.16 16.065 257.04 16.335 ;
     RECT  2.16 16.605 257.04 16.875 ;
     RECT  2.16 17.145 257.04 17.415 ;
     RECT  2.16 17.685 257.04 17.955 ;
     RECT  2.16 18.225 257.04 18.495 ;
     RECT  2.16 18.765 257.04 19.035 ;
     RECT  2.16 19.305 257.04 19.575 ;
     RECT  2.16 19.845 257.04 20.115 ;
     RECT  2.16 20.385 257.04 20.655 ;
     RECT  2.16 20.925 257.04 21.195 ;
     RECT  2.16 21.465 257.04 21.735 ;
     RECT  2.16 22.005 257.04 22.275 ;
     RECT  2.16 22.545 257.04 22.815 ;
     RECT  2.16 23.085 257.04 23.355 ;
     RECT  2.16 23.625 257.04 23.895 ;
     RECT  2.16 24.165 257.04 24.435 ;
     RECT  2.16 24.705 257.04 24.975 ;
     RECT  2.16 25.245 257.04 25.515 ;
     RECT  2.16 25.785 257.04 26.055 ;
     RECT  2.16 26.325 257.04 26.595 ;
     RECT  2.16 26.865 257.04 27.135 ;
     RECT  2.16 27.405 257.04 27.675 ;
     RECT  2.16 27.945 257.04 28.215 ;
     RECT  2.16 28.485 257.04 28.755 ;
     RECT  2.16 29.025 257.04 29.295 ;
     RECT  2.16 29.565 257.04 29.835 ;
     RECT  2.16 30.105 257.04 30.375 ;
     RECT  2.16 30.645 257.04 30.915 ;
     RECT  2.16 31.185 257.04 31.455 ;
     RECT  2.16 31.725 257.04 31.995 ;
     RECT  2.16 32.265 257.04 32.535 ;
     RECT  2.16 32.805 257.04 33.075 ;
     RECT  2.16 33.345 257.04 33.615 ;
     RECT  2.16 33.885 257.04 34.155 ;
     RECT  2.16 34.425 257.04 34.695 ;
     RECT  2.16 34.965 257.04 35.235 ;
     RECT  2.16 35.505 257.04 35.775 ;
     RECT  2.16 36.045 257.04 36.315 ;
     RECT  2.16 36.585 257.04 36.855 ;
     RECT  2.16 37.125 257.04 37.395 ;
     RECT  2.16 37.665 257.04 37.935 ;
     RECT  2.16 38.205 257.04 38.475 ;
     RECT  2.16 38.745 257.04 39.015 ;
     RECT  2.16 39.285 257.04 39.555 ;
     RECT  2.16 39.825 257.04 40.095 ;
     RECT  2.16 40.365 257.04 40.635 ;
     RECT  2.16 40.905 257.04 41.04 ;
     RECT  2.16 41.04 41.148 41.175 ;
     RECT  219.348 41.04 257.04 41.175 ;
     RECT  2.16 41.445 41.148 41.715 ;
     RECT  219.348 41.445 257.04 41.715 ;
     RECT  2.16 41.985 41.148 42.255 ;
     RECT  219.348 41.985 257.04 42.255 ;
     RECT  2.16 42.525 41.148 42.795 ;
     RECT  219.348 42.525 257.04 42.795 ;
     RECT  2.16 43.065 41.148 43.335 ;
     RECT  219.348 43.065 257.04 43.335 ;
     RECT  2.16 43.605 41.148 43.875 ;
     RECT  219.348 43.605 257.04 43.875 ;
     RECT  2.16 44.145 41.148 44.415 ;
     RECT  219.348 44.145 257.04 44.415 ;
     RECT  2.16 44.685 41.148 44.955 ;
     RECT  219.348 44.685 257.04 44.955 ;
     RECT  2.16 45.225 41.148 45.495 ;
     RECT  219.348 45.225 257.04 45.495 ;
     RECT  2.16 45.765 41.148 46.035 ;
     RECT  219.348 45.765 257.04 46.035 ;
     RECT  2.16 46.305 41.148 46.575 ;
     RECT  219.348 46.305 257.04 46.575 ;
     RECT  2.16 46.845 41.148 47.115 ;
     RECT  219.348 46.845 257.04 47.115 ;
     RECT  2.16 47.385 41.148 47.655 ;
     RECT  219.348 47.385 257.04 47.655 ;
     RECT  2.16 47.925 41.148 48.195 ;
     RECT  219.348 47.925 257.04 48.195 ;
     RECT  2.16 48.465 41.148 48.735 ;
     RECT  219.348 48.465 257.04 48.735 ;
     RECT  2.16 49.005 41.148 49.275 ;
     RECT  219.348 49.005 257.04 49.275 ;
     RECT  2.16 49.545 41.148 49.815 ;
     RECT  219.348 49.545 257.04 49.815 ;
     RECT  2.16 50.085 41.148 50.355 ;
     RECT  219.348 50.085 257.04 50.355 ;
     RECT  2.16 50.625 41.148 50.895 ;
     RECT  219.348 50.625 257.04 50.895 ;
     RECT  2.16 51.165 41.148 51.435 ;
     RECT  219.348 51.165 257.04 51.435 ;
     RECT  2.16 51.705 41.148 51.975 ;
     RECT  219.348 51.705 257.04 51.975 ;
     RECT  2.16 52.245 41.148 52.515 ;
     RECT  219.348 52.245 257.04 52.515 ;
     RECT  2.16 52.785 41.148 53.055 ;
     RECT  219.348 52.785 257.04 53.055 ;
     RECT  2.16 53.325 41.148 53.595 ;
     RECT  219.348 53.325 257.04 53.595 ;
     RECT  2.16 53.865 41.148 54.135 ;
     RECT  219.348 53.865 257.04 54.135 ;
     RECT  2.16 54.405 41.148 54.675 ;
     RECT  219.348 54.405 257.04 54.675 ;
     RECT  2.16 54.945 41.148 55.215 ;
     RECT  219.348 54.945 257.04 55.215 ;
     RECT  2.16 55.485 41.148 55.755 ;
     RECT  219.348 55.485 257.04 55.755 ;
     RECT  2.16 56.025 41.148 56.295 ;
     RECT  219.348 56.025 257.04 56.295 ;
     RECT  2.16 56.565 41.148 56.835 ;
     RECT  219.348 56.565 257.04 56.835 ;
     RECT  2.16 57.105 41.148 57.375 ;
     RECT  219.348 57.105 257.04 57.375 ;
     RECT  2.16 57.645 41.148 57.915 ;
     RECT  219.348 57.645 257.04 57.915 ;
     RECT  2.16 58.185 41.148 58.455 ;
     RECT  219.348 58.185 257.04 58.455 ;
     RECT  2.16 58.725 41.148 58.995 ;
     RECT  219.348 58.725 257.04 58.995 ;
     RECT  2.16 59.265 41.148 59.535 ;
     RECT  219.348 59.265 257.04 59.535 ;
     RECT  2.16 59.805 41.148 60.075 ;
     RECT  219.348 59.805 257.04 60.075 ;
     RECT  2.16 60.345 41.148 60.615 ;
     RECT  219.348 60.345 257.04 60.615 ;
     RECT  2.16 60.885 41.148 61.155 ;
     RECT  219.348 60.885 257.04 61.155 ;
     RECT  2.16 61.425 41.148 61.695 ;
     RECT  219.348 61.425 257.04 61.695 ;
     RECT  2.16 61.965 41.148 62.235 ;
     RECT  219.348 61.965 257.04 62.235 ;
     RECT  2.16 62.505 41.148 62.775 ;
     RECT  219.348 62.505 257.04 62.775 ;
     RECT  2.16 63.045 41.148 63.315 ;
     RECT  219.348 63.045 257.04 63.315 ;
     RECT  2.16 63.585 41.148 63.855 ;
     RECT  219.348 63.585 257.04 63.855 ;
     RECT  2.16 64.125 41.148 64.395 ;
     RECT  219.348 64.125 257.04 64.395 ;
     RECT  2.16 64.665 41.148 64.935 ;
     RECT  219.348 64.665 257.04 64.935 ;
     RECT  2.16 65.205 41.148 65.475 ;
     RECT  219.348 65.205 257.04 65.475 ;
     RECT  2.16 65.745 41.148 66.015 ;
     RECT  219.348 65.745 257.04 66.015 ;
     RECT  2.16 66.285 41.148 66.555 ;
     RECT  219.348 66.285 257.04 66.555 ;
     RECT  2.16 66.825 41.148 67.095 ;
     RECT  219.348 66.825 257.04 67.095 ;
     RECT  2.16 67.365 41.148 67.635 ;
     RECT  219.348 67.365 257.04 67.635 ;
     RECT  2.16 67.905 41.148 68.175 ;
     RECT  219.348 67.905 257.04 68.175 ;
     RECT  2.16 68.445 41.148 68.715 ;
     RECT  219.348 68.445 257.04 68.715 ;
     RECT  2.16 68.985 41.148 69.255 ;
     RECT  219.348 68.985 257.04 69.255 ;
     RECT  2.16 69.525 41.148 69.795 ;
     RECT  219.348 69.525 257.04 69.795 ;
     RECT  2.16 70.065 41.148 70.335 ;
     RECT  219.348 70.065 257.04 70.335 ;
     RECT  2.16 70.605 41.148 70.875 ;
     RECT  219.348 70.605 257.04 70.875 ;
     RECT  2.16 71.145 41.148 71.415 ;
     RECT  219.348 71.145 257.04 71.415 ;
     RECT  2.16 71.685 41.148 71.955 ;
     RECT  219.348 71.685 257.04 71.955 ;
     RECT  2.16 72.225 41.148 72.495 ;
     RECT  219.348 72.225 257.04 72.495 ;
     RECT  2.16 72.765 41.148 73.035 ;
     RECT  219.348 72.765 257.04 73.035 ;
     RECT  2.16 73.305 41.148 73.575 ;
     RECT  219.348 73.305 257.04 73.575 ;
     RECT  2.16 73.845 41.148 74.115 ;
     RECT  219.348 73.845 257.04 74.115 ;
     RECT  2.16 74.385 41.148 74.655 ;
     RECT  219.348 74.385 257.04 74.655 ;
     RECT  2.16 74.925 41.148 75.06 ;
     RECT  219.348 74.925 257.04 75.06 ;
     RECT  2.16 75.06 257.04 75.195 ;
     RECT  2.16 75.465 257.04 75.735 ;
     RECT  2.16 76.005 257.04 76.275 ;
     RECT  2.16 76.545 257.04 76.815 ;
     RECT  2.16 77.085 257.04 77.355 ;
     RECT  2.16 77.625 257.04 77.895 ;
     RECT  2.16 78.165 257.04 78.435 ;
     RECT  2.16 78.705 257.04 78.975 ;
     RECT  2.16 79.245 257.04 79.515 ;
     RECT  2.16 79.785 257.04 80.055 ;
     RECT  2.16 80.325 257.04 80.595 ;
     RECT  2.16 80.865 257.04 81.135 ;
     RECT  2.16 81.405 257.04 81.675 ;
     RECT  2.16 81.945 257.04 82.215 ;
     RECT  2.16 82.485 257.04 82.755 ;
     RECT  2.16 83.025 257.04 83.295 ;
     RECT  2.16 83.565 257.04 83.835 ;
     RECT  2.16 84.105 257.04 84.375 ;
     RECT  2.16 84.645 257.04 84.915 ;
     RECT  2.16 85.185 257.04 85.455 ;
     RECT  2.16 85.725 257.04 85.995 ;
     RECT  2.16 86.265 257.04 86.535 ;
     RECT  2.16 86.805 257.04 87.075 ;
     RECT  2.16 87.345 257.04 87.615 ;
     RECT  2.16 87.885 257.04 88.155 ;
     RECT  2.16 88.425 257.04 88.695 ;
     RECT  2.16 88.965 257.04 89.235 ;
     RECT  2.16 89.505 257.04 89.775 ;
     RECT  2.16 90.045 257.04 90.315 ;
     RECT  2.16 90.585 257.04 90.855 ;
     RECT  2.16 91.125 257.04 91.395 ;
     RECT  2.16 91.665 257.04 91.935 ;
     RECT  2.16 92.205 257.04 92.475 ;
     RECT  2.16 92.745 257.04 93.015 ;
     RECT  2.16 93.285 257.04 93.555 ;
     RECT  2.16 93.825 257.04 94.095 ;
     RECT  2.16 94.365 257.04 94.635 ;
     RECT  2.16 94.905 257.04 95.175 ;
     RECT  2.16 95.445 257.04 95.715 ;
     RECT  2.16 95.985 257.04 96.255 ;
     RECT  2.16 96.525 257.04 96.795 ;
     RECT  2.16 97.065 257.04 97.335 ;
     RECT  2.16 97.605 257.04 97.875 ;
     RECT  2.16 98.145 257.04 98.415 ;
     RECT  2.16 98.685 257.04 98.955 ;
     RECT  2.16 99.225 257.04 99.495 ;
     RECT  2.16 99.765 257.04 100.035 ;
     RECT  2.16 100.305 257.04 100.575 ;
     RECT  2.16 100.845 257.04 101.115 ;
     RECT  2.16 101.385 257.04 101.655 ;
     RECT  2.16 101.925 257.04 102.195 ;
     RECT  2.16 102.465 257.04 102.735 ;
     RECT  2.16 103.005 257.04 103.275 ;
     RECT  2.16 103.545 257.04 103.815 ;
     RECT  2.16 104.085 257.04 104.355 ;
     RECT  2.16 104.625 257.04 104.895 ;
     RECT  2.16 105.165 257.04 105.435 ;
     RECT  2.16 105.705 257.04 105.975 ;
     RECT  2.16 106.245 257.04 106.515 ;
     RECT  2.16 106.785 257.04 107.055 ;
     RECT  2.16 107.325 257.04 107.595 ;
     RECT  2.16 107.865 257.04 108.135 ;
     RECT  2.16 108.405 257.04 108.675 ;
     RECT  2.16 108.945 257.04 109.215 ;
     RECT  2.16 109.485 257.04 109.755 ;
     RECT  2.16 110.025 257.04 110.295 ;
     RECT  2.16 110.565 257.04 110.835 ;
     RECT  2.16 111.105 257.04 111.375 ;
     RECT  2.16 111.645 257.04 111.915 ;
     RECT  2.16 112.185 257.04 112.455 ;
     RECT  2.16 112.725 257.04 112.995 ;
     RECT  2.16 113.265 257.04 113.535 ;
     RECT  2.16 113.805 257.04 114.075 ;
     RECT  2.16 114.345 257.04 114.615 ;
     RECT  2.16 114.885 257.04 115.155 ;
     RECT  2.16 115.425 257.04 115.695 ;
     RECT  2.16 115.965 257.04 116.235 ;
     RECT  2.16 116.505 257.04 116.775 ;
     RECT  2.16 117.045 257.04 117.315 ;
     RECT  2.16 117.585 257.04 117.855 ;
     RECT  2.16 118.125 257.04 118.395 ;
     RECT  2.16 118.665 257.04 118.935 ;
     RECT  2.16 119.205 257.04 119.475 ;
     RECT  2.16 119.745 257.04 120.015 ;
     RECT  2.16 120.285 257.04 120.555 ;
     RECT  2.16 120.825 257.04 121.095 ;
     RECT  2.16 121.365 257.04 121.635 ;
     RECT  2.16 121.905 257.04 122.175 ;
     RECT  2.16 122.445 257.04 122.715 ;
     RECT  2.16 122.985 257.04 123.255 ;
     RECT  2.16 123.525 257.04 123.795 ;
     RECT  2.16 124.065 257.04 124.335 ;
     RECT  2.16 124.605 257.04 124.875 ;
     RECT  2.16 125.145 257.04 125.415 ;
     RECT  2.16 125.685 257.04 125.955 ;
     RECT  2.16 126.225 257.04 126.495 ;
     RECT  2.16 126.765 257.04 127.035 ;
     RECT  2.16 127.305 257.04 127.44 ;
    LAYER RVTP ;
     RECT  2.16 2.295 257.04 2.565 ;
     RECT  2.16 2.835 257.04 3.105 ;
     RECT  2.16 3.375 257.04 3.645 ;
     RECT  2.16 3.915 257.04 4.185 ;
     RECT  2.16 4.455 257.04 4.725 ;
     RECT  2.16 4.995 257.04 5.265 ;
     RECT  2.16 5.535 257.04 5.805 ;
     RECT  2.16 6.075 257.04 6.345 ;
     RECT  2.16 6.615 257.04 6.885 ;
     RECT  2.16 7.155 257.04 7.425 ;
     RECT  2.16 7.695 257.04 7.965 ;
     RECT  2.16 8.235 257.04 8.505 ;
     RECT  2.16 8.775 257.04 9.045 ;
     RECT  2.16 9.315 257.04 9.585 ;
     RECT  2.16 9.855 257.04 10.125 ;
     RECT  2.16 10.395 257.04 10.665 ;
     RECT  2.16 10.935 257.04 11.205 ;
     RECT  2.16 11.475 257.04 11.745 ;
     RECT  2.16 12.015 257.04 12.285 ;
     RECT  2.16 12.555 257.04 12.825 ;
     RECT  2.16 13.095 257.04 13.365 ;
     RECT  2.16 13.635 257.04 13.905 ;
     RECT  2.16 14.175 257.04 14.445 ;
     RECT  2.16 14.715 257.04 14.985 ;
     RECT  2.16 15.255 257.04 15.525 ;
     RECT  2.16 15.795 257.04 16.065 ;
     RECT  2.16 16.335 257.04 16.605 ;
     RECT  2.16 16.875 257.04 17.145 ;
     RECT  2.16 17.415 257.04 17.685 ;
     RECT  2.16 17.955 257.04 18.225 ;
     RECT  2.16 18.495 257.04 18.765 ;
     RECT  2.16 19.035 257.04 19.305 ;
     RECT  2.16 19.575 257.04 19.845 ;
     RECT  2.16 20.115 257.04 20.385 ;
     RECT  2.16 20.655 257.04 20.925 ;
     RECT  2.16 21.195 257.04 21.465 ;
     RECT  2.16 21.735 257.04 22.005 ;
     RECT  2.16 22.275 257.04 22.545 ;
     RECT  2.16 22.815 257.04 23.085 ;
     RECT  2.16 23.355 257.04 23.625 ;
     RECT  2.16 23.895 257.04 24.165 ;
     RECT  2.16 24.435 257.04 24.705 ;
     RECT  2.16 24.975 257.04 25.245 ;
     RECT  2.16 25.515 257.04 25.785 ;
     RECT  2.16 26.055 257.04 26.325 ;
     RECT  2.16 26.595 257.04 26.865 ;
     RECT  2.16 27.135 257.04 27.405 ;
     RECT  2.16 27.675 257.04 27.945 ;
     RECT  2.16 28.215 257.04 28.485 ;
     RECT  2.16 28.755 257.04 29.025 ;
     RECT  2.16 29.295 257.04 29.565 ;
     RECT  2.16 29.835 257.04 30.105 ;
     RECT  2.16 30.375 257.04 30.645 ;
     RECT  2.16 30.915 257.04 31.185 ;
     RECT  2.16 31.455 257.04 31.725 ;
     RECT  2.16 31.995 257.04 32.265 ;
     RECT  2.16 32.535 257.04 32.805 ;
     RECT  2.16 33.075 257.04 33.345 ;
     RECT  2.16 33.615 257.04 33.885 ;
     RECT  2.16 34.155 257.04 34.425 ;
     RECT  2.16 34.695 257.04 34.965 ;
     RECT  2.16 35.235 257.04 35.505 ;
     RECT  2.16 35.775 257.04 36.045 ;
     RECT  2.16 36.315 257.04 36.585 ;
     RECT  2.16 36.855 257.04 37.125 ;
     RECT  2.16 37.395 257.04 37.665 ;
     RECT  2.16 37.935 257.04 38.205 ;
     RECT  2.16 38.475 257.04 38.745 ;
     RECT  2.16 39.015 257.04 39.285 ;
     RECT  2.16 39.555 257.04 39.825 ;
     RECT  2.16 40.095 257.04 40.365 ;
     RECT  2.16 40.635 257.04 40.905 ;
     RECT  2.16 41.175 41.148 41.445 ;
     RECT  219.348 41.175 257.04 41.445 ;
     RECT  2.16 41.715 41.148 41.985 ;
     RECT  219.348 41.715 257.04 41.985 ;
     RECT  2.16 42.255 41.148 42.525 ;
     RECT  219.348 42.255 257.04 42.525 ;
     RECT  2.16 42.795 41.148 43.065 ;
     RECT  219.348 42.795 257.04 43.065 ;
     RECT  2.16 43.335 41.148 43.605 ;
     RECT  219.348 43.335 257.04 43.605 ;
     RECT  2.16 43.875 41.148 44.145 ;
     RECT  219.348 43.875 257.04 44.145 ;
     RECT  2.16 44.415 41.148 44.685 ;
     RECT  219.348 44.415 257.04 44.685 ;
     RECT  2.16 44.955 41.148 45.225 ;
     RECT  219.348 44.955 257.04 45.225 ;
     RECT  2.16 45.495 41.148 45.765 ;
     RECT  219.348 45.495 257.04 45.765 ;
     RECT  2.16 46.035 41.148 46.305 ;
     RECT  219.348 46.035 257.04 46.305 ;
     RECT  2.16 46.575 41.148 46.845 ;
     RECT  219.348 46.575 257.04 46.845 ;
     RECT  2.16 47.115 41.148 47.385 ;
     RECT  219.348 47.115 257.04 47.385 ;
     RECT  2.16 47.655 41.148 47.925 ;
     RECT  219.348 47.655 257.04 47.925 ;
     RECT  2.16 48.195 41.148 48.465 ;
     RECT  219.348 48.195 257.04 48.465 ;
     RECT  2.16 48.735 41.148 49.005 ;
     RECT  219.348 48.735 257.04 49.005 ;
     RECT  2.16 49.275 41.148 49.545 ;
     RECT  219.348 49.275 257.04 49.545 ;
     RECT  2.16 49.815 41.148 50.085 ;
     RECT  219.348 49.815 257.04 50.085 ;
     RECT  2.16 50.355 41.148 50.625 ;
     RECT  219.348 50.355 257.04 50.625 ;
     RECT  2.16 50.895 41.148 51.165 ;
     RECT  219.348 50.895 257.04 51.165 ;
     RECT  2.16 51.435 41.148 51.705 ;
     RECT  219.348 51.435 257.04 51.705 ;
     RECT  2.16 51.975 41.148 52.245 ;
     RECT  219.348 51.975 257.04 52.245 ;
     RECT  2.16 52.515 41.148 52.785 ;
     RECT  219.348 52.515 257.04 52.785 ;
     RECT  2.16 53.055 41.148 53.325 ;
     RECT  219.348 53.055 257.04 53.325 ;
     RECT  2.16 53.595 41.148 53.865 ;
     RECT  219.348 53.595 257.04 53.865 ;
     RECT  2.16 54.135 41.148 54.405 ;
     RECT  219.348 54.135 257.04 54.405 ;
     RECT  2.16 54.675 41.148 54.945 ;
     RECT  219.348 54.675 257.04 54.945 ;
     RECT  2.16 55.215 41.148 55.485 ;
     RECT  219.348 55.215 257.04 55.485 ;
     RECT  2.16 55.755 41.148 56.025 ;
     RECT  219.348 55.755 257.04 56.025 ;
     RECT  2.16 56.295 41.148 56.565 ;
     RECT  219.348 56.295 257.04 56.565 ;
     RECT  2.16 56.835 41.148 57.105 ;
     RECT  219.348 56.835 257.04 57.105 ;
     RECT  2.16 57.375 41.148 57.645 ;
     RECT  219.348 57.375 257.04 57.645 ;
     RECT  2.16 57.915 41.148 58.185 ;
     RECT  219.348 57.915 257.04 58.185 ;
     RECT  2.16 58.455 41.148 58.725 ;
     RECT  219.348 58.455 257.04 58.725 ;
     RECT  2.16 58.995 41.148 59.265 ;
     RECT  219.348 58.995 257.04 59.265 ;
     RECT  2.16 59.535 41.148 59.805 ;
     RECT  219.348 59.535 257.04 59.805 ;
     RECT  2.16 60.075 41.148 60.345 ;
     RECT  219.348 60.075 257.04 60.345 ;
     RECT  2.16 60.615 41.148 60.885 ;
     RECT  219.348 60.615 257.04 60.885 ;
     RECT  2.16 61.155 41.148 61.425 ;
     RECT  219.348 61.155 257.04 61.425 ;
     RECT  2.16 61.695 41.148 61.965 ;
     RECT  219.348 61.695 257.04 61.965 ;
     RECT  2.16 62.235 41.148 62.505 ;
     RECT  219.348 62.235 257.04 62.505 ;
     RECT  2.16 62.775 41.148 63.045 ;
     RECT  219.348 62.775 257.04 63.045 ;
     RECT  2.16 63.315 41.148 63.585 ;
     RECT  219.348 63.315 257.04 63.585 ;
     RECT  2.16 63.855 41.148 64.125 ;
     RECT  219.348 63.855 257.04 64.125 ;
     RECT  2.16 64.395 41.148 64.665 ;
     RECT  219.348 64.395 257.04 64.665 ;
     RECT  2.16 64.935 41.148 65.205 ;
     RECT  219.348 64.935 257.04 65.205 ;
     RECT  2.16 65.475 41.148 65.745 ;
     RECT  219.348 65.475 257.04 65.745 ;
     RECT  2.16 66.015 41.148 66.285 ;
     RECT  219.348 66.015 257.04 66.285 ;
     RECT  2.16 66.555 41.148 66.825 ;
     RECT  219.348 66.555 257.04 66.825 ;
     RECT  2.16 67.095 41.148 67.365 ;
     RECT  219.348 67.095 257.04 67.365 ;
     RECT  2.16 67.635 41.148 67.905 ;
     RECT  219.348 67.635 257.04 67.905 ;
     RECT  2.16 68.175 41.148 68.445 ;
     RECT  219.348 68.175 257.04 68.445 ;
     RECT  2.16 68.715 41.148 68.985 ;
     RECT  219.348 68.715 257.04 68.985 ;
     RECT  2.16 69.255 41.148 69.525 ;
     RECT  219.348 69.255 257.04 69.525 ;
     RECT  2.16 69.795 41.148 70.065 ;
     RECT  219.348 69.795 257.04 70.065 ;
     RECT  2.16 70.335 41.148 70.605 ;
     RECT  219.348 70.335 257.04 70.605 ;
     RECT  2.16 70.875 41.148 71.145 ;
     RECT  219.348 70.875 257.04 71.145 ;
     RECT  2.16 71.415 41.148 71.685 ;
     RECT  219.348 71.415 257.04 71.685 ;
     RECT  2.16 71.955 41.148 72.225 ;
     RECT  219.348 71.955 257.04 72.225 ;
     RECT  2.16 72.495 41.148 72.765 ;
     RECT  219.348 72.495 257.04 72.765 ;
     RECT  2.16 73.035 41.148 73.305 ;
     RECT  219.348 73.035 257.04 73.305 ;
     RECT  2.16 73.575 41.148 73.845 ;
     RECT  219.348 73.575 257.04 73.845 ;
     RECT  2.16 74.115 41.148 74.385 ;
     RECT  219.348 74.115 257.04 74.385 ;
     RECT  2.16 74.655 41.148 74.925 ;
     RECT  219.348 74.655 257.04 74.925 ;
     RECT  2.16 75.195 257.04 75.465 ;
     RECT  2.16 75.735 257.04 76.005 ;
     RECT  2.16 76.275 257.04 76.545 ;
     RECT  2.16 76.815 257.04 77.085 ;
     RECT  2.16 77.355 257.04 77.625 ;
     RECT  2.16 77.895 257.04 78.165 ;
     RECT  2.16 78.435 257.04 78.705 ;
     RECT  2.16 78.975 257.04 79.245 ;
     RECT  2.16 79.515 257.04 79.785 ;
     RECT  2.16 80.055 257.04 80.325 ;
     RECT  2.16 80.595 257.04 80.865 ;
     RECT  2.16 81.135 257.04 81.405 ;
     RECT  2.16 81.675 257.04 81.945 ;
     RECT  2.16 82.215 257.04 82.485 ;
     RECT  2.16 82.755 257.04 83.025 ;
     RECT  2.16 83.295 257.04 83.565 ;
     RECT  2.16 83.835 257.04 84.105 ;
     RECT  2.16 84.375 257.04 84.645 ;
     RECT  2.16 84.915 257.04 85.185 ;
     RECT  2.16 85.455 257.04 85.725 ;
     RECT  2.16 85.995 257.04 86.265 ;
     RECT  2.16 86.535 257.04 86.805 ;
     RECT  2.16 87.075 257.04 87.345 ;
     RECT  2.16 87.615 257.04 87.885 ;
     RECT  2.16 88.155 257.04 88.425 ;
     RECT  2.16 88.695 257.04 88.965 ;
     RECT  2.16 89.235 257.04 89.505 ;
     RECT  2.16 89.775 257.04 90.045 ;
     RECT  2.16 90.315 257.04 90.585 ;
     RECT  2.16 90.855 257.04 91.125 ;
     RECT  2.16 91.395 257.04 91.665 ;
     RECT  2.16 91.935 257.04 92.205 ;
     RECT  2.16 92.475 257.04 92.745 ;
     RECT  2.16 93.015 257.04 93.285 ;
     RECT  2.16 93.555 257.04 93.825 ;
     RECT  2.16 94.095 257.04 94.365 ;
     RECT  2.16 94.635 257.04 94.905 ;
     RECT  2.16 95.175 257.04 95.445 ;
     RECT  2.16 95.715 257.04 95.985 ;
     RECT  2.16 96.255 257.04 96.525 ;
     RECT  2.16 96.795 257.04 97.065 ;
     RECT  2.16 97.335 257.04 97.605 ;
     RECT  2.16 97.875 257.04 98.145 ;
     RECT  2.16 98.415 257.04 98.685 ;
     RECT  2.16 98.955 257.04 99.225 ;
     RECT  2.16 99.495 257.04 99.765 ;
     RECT  2.16 100.035 257.04 100.305 ;
     RECT  2.16 100.575 257.04 100.845 ;
     RECT  2.16 101.115 257.04 101.385 ;
     RECT  2.16 101.655 257.04 101.925 ;
     RECT  2.16 102.195 257.04 102.465 ;
     RECT  2.16 102.735 257.04 103.005 ;
     RECT  2.16 103.275 257.04 103.545 ;
     RECT  2.16 103.815 257.04 104.085 ;
     RECT  2.16 104.355 257.04 104.625 ;
     RECT  2.16 104.895 257.04 105.165 ;
     RECT  2.16 105.435 257.04 105.705 ;
     RECT  2.16 105.975 257.04 106.245 ;
     RECT  2.16 106.515 257.04 106.785 ;
     RECT  2.16 107.055 257.04 107.325 ;
     RECT  2.16 107.595 257.04 107.865 ;
     RECT  2.16 108.135 257.04 108.405 ;
     RECT  2.16 108.675 257.04 108.945 ;
     RECT  2.16 109.215 257.04 109.485 ;
     RECT  2.16 109.755 257.04 110.025 ;
     RECT  2.16 110.295 257.04 110.565 ;
     RECT  2.16 110.835 257.04 111.105 ;
     RECT  2.16 111.375 257.04 111.645 ;
     RECT  2.16 111.915 257.04 112.185 ;
     RECT  2.16 112.455 257.04 112.725 ;
     RECT  2.16 112.995 257.04 113.265 ;
     RECT  2.16 113.535 257.04 113.805 ;
     RECT  2.16 114.075 257.04 114.345 ;
     RECT  2.16 114.615 257.04 114.885 ;
     RECT  2.16 115.155 257.04 115.425 ;
     RECT  2.16 115.695 257.04 115.965 ;
     RECT  2.16 116.235 257.04 116.505 ;
     RECT  2.16 116.775 257.04 117.045 ;
     RECT  2.16 117.315 257.04 117.585 ;
     RECT  2.16 117.855 257.04 118.125 ;
     RECT  2.16 118.395 257.04 118.665 ;
     RECT  2.16 118.935 257.04 119.205 ;
     RECT  2.16 119.475 257.04 119.745 ;
     RECT  2.16 120.015 257.04 120.285 ;
     RECT  2.16 120.555 257.04 120.825 ;
     RECT  2.16 121.095 257.04 121.365 ;
     RECT  2.16 121.635 257.04 121.905 ;
     RECT  2.16 122.175 257.04 122.445 ;
     RECT  2.16 122.715 257.04 122.985 ;
     RECT  2.16 123.255 257.04 123.525 ;
     RECT  2.16 123.795 257.04 124.065 ;
     RECT  2.16 124.335 257.04 124.605 ;
     RECT  2.16 124.875 257.04 125.145 ;
     RECT  2.16 125.415 257.04 125.685 ;
     RECT  2.16 125.955 257.04 126.225 ;
     RECT  2.16 126.495 257.04 126.765 ;
     RECT  2.16 127.035 257.04 127.305 ;
    LAYER M1 ;
     RECT  2.16 2.151 257.04 41.049 ;
     RECT  43.2 43.2 217.32 72.936 ;
     RECT  2.16 41.049 41.148 75.051 ;
     RECT  219.348 41.049 257.04 75.051 ;
     RECT  2.16 75.051 257.04 127.449 ;
    LAYER M2 ;
     RECT  0.103 81.72 0.139 84.33 ;
     RECT  0.103 96.3 0.139 96.318 ;
     RECT  0.211 55.692 0.247 55.71 ;
     RECT  0.103 59.202 0.535 60.174 ;
     RECT  0.139 80.334 1.723 80.352 ;
     RECT  0.103 54.882 2.16 54.9 ;
     RECT  0.247 55.692 2.16 55.818 ;
     RECT  0.535 59.004 2.16 60.174 ;
     RECT  1.723 80.334 2.16 80.658 ;
     RECT  0.139 81.612 2.16 84.33 ;
     RECT  0.031 87.822 2.16 87.84 ;
     RECT  0.139 96.192 2.16 96.318 ;
     RECT  2.16 2.151 41.148 127.449 ;
     RECT  41.148 59.976 41.351 65.16 ;
     RECT  41.351 60.12 41.639 65.16 ;
     RECT  41.148 2.151 41.711 49.734 ;
     RECT  41.711 46.35 42.143 49.734 ;
     RECT  41.711 2.151 42.179 45.45 ;
     RECT  42.143 46.35 42.179 47.574 ;
     RECT  41.639 60.39 42.179 65.16 ;
     RECT  41.148 57.15 42.215 59.094 ;
     RECT  42.179 60.516 42.215 61.524 ;
     RECT  42.179 62.442 42.215 64.314 ;
     RECT  42.179 2.151 42.287 45.18 ;
     RECT  42.215 57.15 42.287 58.644 ;
     RECT  42.287 2.151 42.359 43.254 ;
     RECT  41.148 55.764 42.359 56.25 ;
     RECT  41.148 70.956 42.467 70.974 ;
     RECT  42.179 46.35 42.727 47.304 ;
     RECT  42.359 2.151 43.2 43.128 ;
     RECT  42.287 44.496 43.2 45.18 ;
     RECT  42.727 46.242 43.2 47.304 ;
     RECT  42.143 48.636 43.2 49.734 ;
     RECT  41.148 54.414 43.2 54.432 ;
     RECT  42.359 55.764 43.2 55.782 ;
     RECT  42.287 57.726 43.2 58.644 ;
     RECT  43.015 59.886 43.2 59.904 ;
     RECT  42.215 60.894 43.2 61.38 ;
     RECT  42.215 62.676 43.2 64.314 ;
     RECT  42.179 65.142 43.2 65.16 ;
     RECT  41.148 69.804 43.2 69.822 ;
     RECT  41.148 72.972 43.2 127.449 ;
     RECT  43.2 2.151 51.467 127.449 ;
     RECT  51.467 74.16 55.931 127.449 ;
     RECT  55.931 74.16 60.359 74.178 ;
     RECT  55.931 75.006 60.475 127.449 ;
     RECT  51.467 2.151 60.503 73.26 ;
     RECT  60.475 74.664 60.755 127.449 ;
     RECT  60.755 75.006 65.831 127.449 ;
     RECT  65.831 75.051 72.571 127.449 ;
     RECT  72.571 75.006 72.959 127.449 ;
     RECT  72.959 75.051 147.523 127.449 ;
     RECT  60.503 2.151 148.063 72.936 ;
     RECT  148.063 2.151 194.071 73.26 ;
     RECT  147.523 74.358 194.071 127.449 ;
     RECT  194.071 2.151 217.32 127.449 ;
     RECT  217.32 2.151 218.839 64.728 ;
     RECT  218.839 2.151 219.348 64.926 ;
     RECT  217.32 73.242 219.348 127.449 ;
     RECT  219.348 2.151 257.04 127.449 ;
     RECT  257.04 44.73 257.063 48.528 ;
     RECT  257.04 39.096 258.215 39.744 ;
     RECT  257.063 44.73 258.215 48.114 ;
     RECT  258.215 39.096 258.251 39.114 ;
     RECT  258.215 44.73 258.287 47.916 ;
     RECT  258.287 45.234 258.323 45.252 ;
     RECT  258.287 46.314 259.079 47.916 ;
     RECT  259.079 46.314 259.115 46.332 ;
     RECT  259.079 47.826 259.115 47.844 ;
    LAYER M3 ;
     RECT  2.415 2.143 2.505 2.413 ;
     RECT  7.815 2.143 7.905 2.413 ;
     RECT  13.215 2.143 13.305 2.413 ;
     RECT  18.615 2.143 18.705 2.413 ;
     RECT  24.015 2.143 24.105 2.413 ;
     RECT  29.415 2.143 29.505 2.413 ;
     RECT  34.815 2.143 34.905 2.413 ;
     RECT  40.215 2.143 40.305 2.413 ;
     RECT  45.615 2.143 45.705 2.413 ;
     RECT  51.015 2.143 51.105 2.413 ;
     RECT  56.415 2.143 56.505 2.413 ;
     RECT  61.815 2.143 61.905 2.413 ;
     RECT  67.215 2.143 67.305 2.413 ;
     RECT  68.184 0.571 68.202 2.413 ;
     RECT  72.615 2.143 72.705 2.413 ;
     RECT  78.015 2.143 78.105 2.413 ;
     RECT  83.415 2.143 83.505 2.413 ;
     RECT  88.815 2.143 88.905 2.413 ;
     RECT  94.215 2.143 94.305 2.413 ;
     RECT  99.615 2.143 99.705 2.413 ;
     RECT  105.015 2.143 105.105 2.413 ;
     RECT  110.415 2.143 110.505 2.413 ;
     RECT  115.815 2.143 115.905 2.413 ;
     RECT  121.215 2.143 121.305 2.413 ;
     RECT  126.615 2.143 126.705 2.413 ;
     RECT  132.015 2.143 132.105 2.413 ;
     RECT  137.415 2.143 137.505 2.413 ;
     RECT  142.815 2.143 142.905 2.413 ;
     RECT  148.215 2.143 148.305 2.413 ;
     RECT  153.615 2.143 153.705 2.413 ;
     RECT  159.015 2.143 159.105 2.413 ;
     RECT  164.415 2.143 164.505 2.413 ;
     RECT  169.815 2.143 169.905 2.413 ;
     RECT  175.215 2.143 175.305 2.413 ;
     RECT  180.615 2.143 180.705 2.413 ;
     RECT  186.015 2.143 186.105 2.413 ;
     RECT  191.415 2.143 191.505 2.413 ;
     RECT  196.815 2.143 196.905 2.413 ;
     RECT  202.215 2.143 202.305 2.413 ;
     RECT  207.615 2.143 207.705 2.413 ;
     RECT  213.015 2.143 213.105 2.413 ;
     RECT  218.415 2.143 218.505 2.413 ;
     RECT  223.815 2.143 223.905 2.413 ;
     RECT  229.215 2.143 229.305 2.413 ;
     RECT  234.615 2.143 234.705 2.413 ;
     RECT  240.015 2.143 240.105 2.413 ;
     RECT  245.415 2.143 245.505 2.413 ;
     RECT  250.815 2.143 250.905 2.413 ;
     RECT  256.215 2.143 256.305 2.413 ;
     RECT  67.215 2.413 68.202 2.911 ;
     RECT  67.215 2.911 68.31 3.299 ;
     RECT  67.215 3.299 68.13 3.389 ;
     RECT  54.396 3.307 54.414 3.875 ;
     RECT  40.215 2.413 40.497 3.991 ;
     RECT  39.78 3.991 40.497 4.081 ;
     RECT  39.636 4.081 40.497 4.157 ;
     RECT  40.215 4.157 40.497 4.261 ;
     RECT  65.52 5.467 65.538 5.504 ;
     RECT  65.664 5.611 65.682 5.648 ;
     RECT  61.815 2.413 62.097 10.831 ;
     RECT  61.815 10.831 62.19 11.011 ;
     RECT  61.815 11.011 62.514 11.261 ;
     RECT  80.82 16.231 80.838 16.301 ;
     RECT  59.04 15.979 59.058 16.363 ;
     RECT  58.716 16.363 59.058 16.411 ;
     RECT  58.716 16.411 59.382 16.541 ;
     RECT  82.116 16.405 82.134 16.685 ;
     RECT  40.215 4.261 40.59 17.105 ;
     RECT  56.415 2.413 56.697 21.115 ;
     RECT  54.72 21.499 54.738 21.629 ;
     RECT  55.872 21.115 56.697 21.659 ;
     RECT  52.74 26.779 52.758 27.031 ;
     RECT  52.74 27.031 53.046 27.059 ;
     RECT  53.028 27.059 53.046 27.149 ;
     RECT  49.536 31.915 49.554 32.431 ;
     RECT  49.536 32.431 49.878 32.459 ;
     RECT  49.86 32.459 49.878 32.477 ;
     RECT  45.615 2.413 45.897 37.627 ;
     RECT  45.615 37.627 46.422 37.859 ;
     RECT  46.728 38.011 46.746 38.189 ;
     RECT  256.215 2.413 256.497 39.115 ;
     RECT  256.215 39.115 257.058 39.209 ;
     RECT  254.304 39.091 254.322 39.289 ;
     RECT  258.228 39.091 258.246 39.341 ;
     RECT  253.116 39.289 253.134 39.361 ;
     RECT  254.232 39.289 254.322 39.361 ;
     RECT  61.815 11.261 62.097 39.451 ;
     RECT  61.704 39.451 62.097 39.488 ;
     RECT  253.116 39.361 253.242 39.595 ;
     RECT  254.232 39.361 254.502 39.595 ;
     RECT  255.384 39.325 255.402 39.595 ;
     RECT  252.288 39.595 252.306 39.631 ;
     RECT  253.116 39.595 255.402 39.631 ;
     RECT  252.288 39.631 255.402 39.721 ;
     RECT  252.072 39.721 255.402 39.739 ;
     RECT  256.215 39.209 256.497 39.739 ;
     RECT  252.072 39.739 256.497 39.749 ;
     RECT  258.192 39.403 258.21 39.749 ;
     RECT  112.356 39.721 112.374 39.773 ;
     RECT  113.472 39.739 113.49 39.785 ;
     RECT  255.384 39.749 256.497 39.785 ;
     RECT  252.072 39.749 254.106 39.793 ;
     RECT  180.615 2.413 180.897 39.901 ;
     RECT  255.384 39.785 255.402 39.929 ;
     RECT  56.415 21.659 56.697 39.991 ;
     RECT  250.815 2.413 251.097 40.063 ;
     RECT  160.92 39.991 160.938 40.091 ;
     RECT  180.615 39.901 181.314 40.171 ;
     RECT  251.928 39.793 254.106 40.171 ;
     RECT  160.668 40.135 160.686 40.289 ;
     RECT  250.236 40.063 251.097 40.289 ;
     RECT  251.892 40.171 254.106 40.289 ;
     RECT  58.176 40.027 58.194 40.297 ;
     RECT  148.215 2.413 148.497 40.297 ;
     RECT  159.015 2.413 159.297 40.297 ;
     RECT  72.615 2.413 72.897 40.405 ;
     RECT  148.215 40.297 148.554 40.441 ;
     RECT  153.615 2.413 153.897 40.441 ;
     RECT  175.215 2.413 175.497 40.441 ;
     RECT  40.215 17.105 40.497 40.459 ;
     RECT  169.815 2.413 170.097 40.507 ;
     RECT  61.815 39.488 62.097 40.531 ;
     RECT  63.684 39.631 63.702 40.531 ;
     RECT  67.215 3.389 67.497 40.555 ;
     RECT  148.176 40.441 148.554 40.555 ;
     RECT  174.384 40.441 174.402 40.555 ;
     RECT  175.215 40.441 176.058 40.555 ;
     RECT  250.815 40.289 251.097 40.555 ;
     RECT  251.892 40.289 253.566 40.555 ;
     RECT  58.176 40.297 58.698 40.559 ;
     RECT  174.384 40.555 176.058 40.559 ;
     RECT  250.815 40.555 253.566 40.559 ;
     RECT  66.672 40.555 67.497 40.567 ;
     RECT  159.015 40.297 159.57 40.567 ;
     RECT  190.584 40.531 190.602 40.567 ;
     RECT  58.5 40.559 58.698 40.589 ;
     RECT  42.444 40.297 42.462 40.603 ;
     RECT  43.236 40.459 43.254 40.603 ;
     RECT  146.592 40.555 146.61 40.603 ;
     RECT  190.512 40.567 190.602 40.603 ;
     RECT  190.44 40.603 190.602 40.631 ;
     RECT  250.815 40.559 252.45 40.631 ;
     RECT  63.684 40.531 64.494 40.637 ;
     RECT  66.672 40.567 68.13 40.639 ;
     RECT  147.96 40.555 148.77 40.651 ;
     RECT  63.864 40.637 64.494 40.667 ;
     RECT  42.192 40.603 43.254 40.675 ;
     RECT  135.9 40.531 136.098 40.675 ;
     RECT  203.796 40.603 203.814 40.675 ;
     RECT  66.06 40.639 68.13 40.685 ;
     RECT  42.192 40.675 43.47 40.699 ;
     RECT  45.615 37.859 45.897 40.699 ;
     RECT  169.815 40.507 170.622 40.702 ;
     RECT  174.384 40.559 175.986 40.703 ;
     RECT  42.192 40.699 43.542 40.711 ;
     RECT  70.38 40.603 70.398 40.711 ;
     RECT  74.7 40.603 74.718 40.711 ;
     RECT  75.888 40.651 75.906 40.711 ;
     RECT  146.592 40.603 146.682 40.711 ;
     RECT  147.96 40.651 148.842 40.711 ;
     RECT  162.36 40.567 162.45 40.711 ;
     RECT  66.672 40.685 68.13 40.739 ;
     RECT  76.896 40.567 76.914 40.739 ;
     RECT  146.52 40.711 146.682 40.739 ;
     RECT  174.384 40.703 175.842 40.739 ;
     RECT  146.52 40.739 146.646 40.781 ;
     RECT  78.015 2.413 78.297 40.787 ;
     RECT  83.415 2.413 83.697 40.787 ;
     RECT  94.215 2.413 94.497 40.787 ;
     RECT  99.615 2.413 99.897 40.787 ;
     RECT  105.015 2.413 105.297 40.787 ;
     RECT  110.415 2.413 110.697 40.787 ;
     RECT  115.815 2.413 116.097 40.787 ;
     RECT  121.215 2.413 121.497 40.787 ;
     RECT  126.615 2.413 126.897 40.787 ;
     RECT  132.015 2.413 132.297 40.787 ;
     RECT  137.415 2.413 137.697 40.787 ;
     RECT  142.815 2.413 143.097 40.787 ;
     RECT  164.415 2.413 164.697 40.787 ;
     RECT  180.615 40.171 181.458 40.787 ;
     RECT  186.015 2.413 186.297 40.787 ;
     RECT  191.415 2.413 191.697 40.787 ;
     RECT  196.815 2.413 197.097 40.787 ;
     RECT  202.215 2.413 202.497 40.787 ;
     RECT  207.615 2.413 207.897 40.787 ;
     RECT  213.015 2.413 213.297 40.787 ;
     RECT  218.415 2.413 218.697 40.787 ;
     RECT  45.615 40.699 45.99 40.795 ;
     RECT  51.015 2.413 51.297 40.795 ;
     RECT  70.308 40.711 70.398 40.795 ;
     RECT  70.308 40.795 70.866 40.801 ;
     RECT  75.888 40.711 76.014 40.801 ;
     RECT  105.015 40.787 105.105 40.801 ;
     RECT  134.532 40.531 134.622 40.801 ;
     RECT  146.52 40.781 146.61 40.801 ;
     RECT  153.615 40.441 154.314 40.801 ;
     RECT  162.288 40.711 162.45 40.801 ;
     RECT  42.192 40.711 43.614 40.829 ;
     RECT  63.864 40.667 64.458 40.829 ;
     RECT  66.744 40.739 68.13 40.829 ;
     RECT  74.448 40.711 74.718 40.829 ;
     RECT  79.56 40.639 79.578 40.829 ;
     RECT  86.616 40.711 86.634 40.829 ;
     RECT  90.504 40.675 90.522 40.829 ;
     RECT  135.612 40.675 136.098 40.829 ;
     RECT  182.808 40.651 182.826 40.829 ;
     RECT  190.44 40.631 190.53 40.829 ;
     RECT  192.456 40.639 192.474 40.829 ;
     RECT  194.436 40.711 194.454 40.829 ;
     RECT  203.22 40.675 203.814 40.829 ;
     RECT  251.928 40.631 252.45 40.829 ;
     RECT  45.615 40.795 46.062 40.835 ;
     RECT  51.015 40.795 51.39 40.835 ;
     RECT  66.744 40.829 67.59 40.835 ;
     RECT  162.216 40.801 162.45 40.837 ;
     RECT  166.176 40.801 166.518 40.837 ;
     RECT  169.815 40.702 170.658 40.837 ;
     RECT  74.448 40.829 74.466 40.865 ;
     RECT  158.472 40.567 159.57 40.865 ;
     RECT  172.512 40.603 172.53 40.865 ;
     RECT  217.188 40.837 217.206 40.873 ;
     RECT  45.615 40.835 45.99 40.877 ;
     RECT  56.415 39.991 56.97 40.877 ;
     RECT  179.676 40.837 179.694 40.877 ;
     RECT  75.888 40.801 76.374 40.891 ;
     RECT  147.96 40.711 148.878 40.891 ;
     RECT  136.008 40.829 136.098 40.901 ;
     RECT  158.616 40.865 159.57 40.901 ;
     RECT  174.384 40.739 175.77 40.901 ;
     RECT  181.548 40.801 181.566 40.901 ;
     RECT  190.44 40.829 190.458 40.901 ;
     RECT  203.688 40.829 203.814 40.901 ;
     RECT  54.72 40.297 54.738 40.909 ;
     RECT  69.876 40.801 70.866 40.925 ;
     RECT  178.596 40.873 178.686 40.925 ;
     RECT  65.664 40.837 65.682 40.936 ;
     RECT  43.596 40.829 43.614 40.937 ;
     RECT  66.744 40.835 67.482 40.937 ;
     RECT  68.976 40.891 68.994 40.937 ;
     RECT  69.876 40.925 70.83 40.937 ;
     RECT  72.615 40.405 72.954 40.937 ;
     RECT  162.216 40.837 162.522 40.937 ;
     RECT  38.988 17.077 39.006 40.945 ;
     RECT  40.215 40.459 40.698 40.945 ;
     RECT  54.72 40.909 55.206 40.945 ;
     RECT  83.415 40.787 83.505 40.945 ;
     RECT  88.815 2.413 89.097 40.945 ;
     RECT  162.216 40.937 162.486 40.945 ;
     RECT  164.415 40.787 164.682 40.945 ;
     RECT  165.924 40.837 166.518 40.945 ;
     RECT  185.184 40.873 185.202 40.945 ;
     RECT  220.392 40.531 220.41 40.945 ;
     RECT  56.415 40.877 56.754 40.973 ;
     RECT  64.44 40.829 64.458 40.973 ;
     RECT  65.556 40.936 65.682 40.973 ;
     RECT  75.78 40.891 76.374 40.973 ;
     RECT  134.532 40.801 134.838 40.973 ;
     RECT  136.08 40.901 136.098 40.973 ;
     RECT  146.484 40.801 146.61 40.973 ;
     RECT  173.592 40.936 173.61 40.973 ;
     RECT  184.86 40.945 185.202 40.973 ;
     RECT  45.615 40.877 45.81 40.981 ;
     RECT  51.015 40.835 51.21 40.981 ;
     RECT  56.415 40.973 56.682 40.981 ;
     RECT  61.815 40.531 62.766 40.981 ;
     RECT  72.615 40.937 72.882 40.981 ;
     RECT  157.392 40.945 157.41 40.981 ;
     RECT  159.015 40.901 159.57 40.981 ;
     RECT  167.796 40.945 167.814 40.981 ;
     RECT  169.815 40.837 171.342 40.981 ;
     RECT  178.668 40.925 178.686 40.981 ;
     RECT  180.615 40.787 180.81 40.981 ;
     RECT  183.564 40.945 183.582 40.981 ;
     RECT  54.468 40.945 55.206 41.009 ;
     RECT  56.304 40.981 56.682 41.009 ;
     RECT  58.788 40.909 58.806 41.009 ;
     RECT  61.704 40.981 62.766 41.009 ;
     RECT  67.104 40.937 67.482 41.009 ;
     RECT  70.236 40.937 70.83 41.009 ;
     RECT  72.504 40.981 72.882 41.009 ;
     RECT  156.528 40.873 156.546 41.009 ;
     RECT  165.852 40.945 166.518 41.009 ;
     RECT  174.708 40.901 175.77 41.009 ;
     RECT  178.668 40.981 178.866 41.009 ;
     RECT  194.796 40.873 194.886 41.009 ;
     RECT  202.215 40.787 202.482 41.009 ;
     RECT  203.724 40.901 203.814 41.009 ;
     RECT  45.504 40.981 45.81 41.021 ;
     RECT  50.904 40.981 51.21 41.021 ;
     RECT  56.304 41.009 56.61 41.021 ;
     RECT  61.704 41.009 62.01 41.021 ;
     RECT  67.104 41.009 67.41 41.021 ;
     RECT  72.504 41.009 72.81 41.021 ;
     RECT  77.112 40.945 77.13 41.021 ;
     RECT  134.82 40.973 134.838 41.021 ;
     RECT  144.54 40.945 144.774 41.021 ;
     RECT  169.704 40.981 171.522 41.021 ;
     RECT  179.928 40.981 180.81 41.021 ;
     RECT  184.86 40.973 185.13 41.021 ;
     RECT  45.615 41.021 45.705 41.057 ;
     RECT  51.015 41.021 51.105 41.057 ;
     RECT  56.415 41.021 56.505 41.057 ;
     RECT  61.815 41.021 61.905 41.057 ;
     RECT  67.215 41.021 67.305 41.057 ;
     RECT  72.615 41.021 72.705 41.057 ;
     RECT  78.015 40.787 78.21 41.057 ;
     RECT  82.8 40.945 83.505 41.057 ;
     RECT  94.215 40.787 94.305 41.057 ;
     RECT  104.868 40.801 105.105 41.057 ;
     RECT  115.815 40.787 115.905 41.057 ;
     RECT  126.615 40.787 126.705 41.057 ;
     RECT  137.415 40.787 137.505 41.057 ;
     RECT  159.015 40.981 159.822 41.057 ;
     RECT  169.815 41.021 169.905 41.057 ;
     RECT  174.708 41.009 175.698 41.057 ;
     RECT  179.928 41.021 180.705 41.057 ;
     RECT  186.015 40.787 186.105 41.057 ;
     RECT  191.415 40.787 191.505 41.057 ;
     RECT  196.815 40.787 196.905 41.057 ;
     RECT  202.215 41.009 202.305 41.057 ;
     RECT  207.615 40.787 207.705 41.057 ;
     RECT  213.015 40.787 213.105 41.057 ;
     RECT  218.415 40.787 218.505 41.057 ;
     RECT  38.988 40.945 40.698 41.071 ;
     RECT  88.815 40.945 89.622 41.071 ;
     RECT  99.615 40.787 99.81 41.071 ;
     RECT  110.415 40.787 110.61 41.071 ;
     RECT  121.215 40.787 121.41 41.071 ;
     RECT  132.015 40.787 132.21 41.071 ;
     RECT  142.815 40.787 143.01 41.071 ;
     RECT  153.615 40.801 154.458 41.071 ;
     RECT  147.888 40.891 148.95 41.099 ;
     RECT  88.704 41.071 89.622 41.117 ;
     RECT  99.504 41.071 99.81 41.117 ;
     RECT  110.304 41.071 110.61 41.117 ;
     RECT  121.104 41.071 121.41 41.117 ;
     RECT  131.904 41.071 132.21 41.117 ;
     RECT  142.704 41.071 143.01 41.117 ;
     RECT  153.504 41.071 154.458 41.117 ;
     RECT  70.668 41.009 70.686 41.165 ;
     RECT  148.356 41.099 148.806 41.165 ;
     RECT  75.996 40.973 76.374 41.213 ;
     RECT  78.192 41.057 78.21 41.213 ;
     RECT  161.496 40.945 162.486 41.213 ;
     RECT  220.32 40.945 220.41 41.251 ;
     RECT  146.484 40.973 146.502 41.261 ;
     RECT  194.796 41.009 194.814 41.279 ;
     RECT  217.188 40.873 217.386 41.296 ;
     RECT  165.852 41.009 166.122 41.324 ;
     RECT  175.68 41.057 175.698 41.324 ;
     RECT  252.18 40.829 252.45 41.341 ;
     RECT  253.224 40.559 253.566 41.341 ;
     RECT  171.252 41.021 171.522 41.369 ;
     RECT  192.852 40.981 192.87 41.369 ;
     RECT  38.88 41.071 40.698 41.377 ;
     RECT  167.796 40.981 168.066 41.405 ;
     RECT  164.16 40.945 164.682 41.441 ;
     RECT  174.708 41.057 174.726 41.441 ;
     RECT  250.815 40.631 251.097 41.449 ;
     RECT  217.188 41.296 217.674 41.485 ;
     RECT  161.496 41.213 162.378 41.513 ;
     RECT  183.276 40.981 183.834 41.549 ;
     RECT  219.708 41.251 220.41 41.881 ;
     RECT  161.496 41.513 162.162 41.909 ;
     RECT  172.764 40.981 172.782 41.909 ;
     RECT  159.228 41.057 159.822 41.945 ;
     RECT  219.672 41.881 220.41 41.953 ;
     RECT  89.604 41.117 89.622 41.981 ;
     RECT  104.868 41.057 104.886 41.981 ;
     RECT  82.8 41.057 82.818 42.017 ;
     RECT  138.42 40.801 138.438 42.017 ;
     RECT  148.788 41.165 148.806 42.053 ;
     RECT  154.44 41.117 154.458 42.089 ;
     RECT  178.848 41.009 178.866 42.134 ;
     RECT  173.844 40.981 173.862 42.179 ;
     RECT  217.188 41.485 218.034 42.421 ;
     RECT  185.112 41.021 185.13 42.449 ;
     RECT  250.236 41.449 251.097 42.457 ;
     RECT  183.276 41.549 183.582 42.461 ;
     RECT  250.236 42.457 251.262 42.493 ;
     RECT  38.88 41.377 40.986 42.571 ;
     RECT  38.88 42.571 41.022 42.701 ;
     RECT  254.592 43.033 254.61 43.105 ;
     RECT  42.192 40.829 42.822 43.2 ;
     RECT  54.468 41.009 54.486 43.2 ;
     RECT  75.996 41.213 76.014 43.2 ;
     RECT  144.756 41.021 144.774 43.2 ;
     RECT  157.392 40.981 157.662 43.2 ;
     RECT  159.48 41.945 159.498 43.2 ;
     RECT  161.496 41.909 161.514 43.2 ;
     RECT  164.664 41.441 164.682 43.2 ;
     RECT  166.104 41.324 166.122 43.2 ;
     RECT  171.504 41.369 171.522 43.2 ;
     RECT  179.928 41.057 179.946 43.2 ;
     RECT  183.276 42.461 183.294 43.2 ;
     RECT  217.188 42.421 218.07 43.2 ;
     RECT  38.88 42.701 40.986 43.231 ;
     RECT  219.672 41.953 220.878 43.303 ;
     RECT  219.636 43.303 220.878 43.537 ;
     RECT  218.916 43.537 220.878 43.681 ;
     RECT  42.192 43.2 218.07 44.059 ;
     RECT  38.844 43.231 40.986 44.155 ;
     RECT  42.156 44.059 218.07 44.221 ;
     RECT  218.88 43.681 220.878 44.221 ;
     RECT  38.844 44.155 41.346 44.251 ;
     RECT  42.156 44.221 220.878 44.251 ;
     RECT  38.844 44.251 220.878 44.339 ;
     RECT  256.215 39.785 256.497 44.419 ;
     RECT  254.592 43.105 254.718 44.455 ;
     RECT  255.492 44.419 256.497 44.455 ;
     RECT  249.804 42.493 251.262 44.725 ;
     RECT  252.18 41.341 253.566 44.725 ;
     RECT  38.844 44.339 218.034 44.753 ;
     RECT  249.696 44.725 253.566 44.761 ;
     RECT  254.304 44.455 256.497 44.761 ;
     RECT  258.264 44.725 258.282 44.761 ;
     RECT  249.696 44.761 256.497 44.879 ;
     RECT  249.732 44.879 256.497 44.995 ;
     RECT  218.88 44.339 220.878 45.053 ;
     RECT  249.732 44.995 256.59 45.185 ;
     RECT  258.228 44.761 258.282 45.229 ;
     RECT  258.228 45.229 258.318 45.301 ;
     RECT  257.58 45.301 258.318 45.485 ;
     RECT  249.732 45.185 256.497 45.563 ;
     RECT  257.616 45.485 258.318 45.773 ;
     RECT  38.844 44.753 217.746 45.841 ;
     RECT  245.415 2.413 245.697 45.841 ;
     RECT  257.616 45.773 258.246 45.869 ;
     RECT  219.384 45.053 220.878 46.027 ;
     RECT  259.092 45.931 259.11 46.027 ;
     RECT  219.276 46.027 220.878 46.067 ;
     RECT  245.415 45.841 246.258 46.103 ;
     RECT  249.768 45.563 256.497 46.111 ;
     RECT  38.844 45.841 218.394 46.237 ;
     RECT  257.652 45.869 258.246 46.253 ;
     RECT  249.768 46.111 256.698 46.265 ;
     RECT  219.348 46.067 220.878 46.301 ;
     RECT  38.808 46.237 218.394 46.309 ;
     RECT  38.772 46.309 218.394 46.381 ;
     RECT  38.7 46.381 218.394 46.813 ;
     RECT  219.384 46.301 220.878 46.973 ;
     RECT  258.192 46.253 258.246 47.011 ;
     RECT  249.768 46.265 256.59 47.317 ;
     RECT  249.732 47.317 256.59 47.371 ;
     RECT  257.652 47.011 258.246 47.371 ;
     RECT  38.7 46.813 218.466 47.623 ;
     RECT  249.732 47.371 258.246 47.693 ;
     RECT  259.056 46.027 259.11 47.849 ;
     RECT  38.7 47.623 218.502 47.857 ;
     RECT  219.42 46.973 220.878 47.857 ;
     RECT  259.056 47.849 259.074 47.921 ;
     RECT  249.732 47.693 258.21 48.077 ;
     RECT  258.192 48.077 258.21 48.119 ;
     RECT  38.304 47.857 220.878 48.413 ;
     RECT  218.304 48.413 220.878 48.425 ;
     RECT  249.732 48.077 257.058 48.533 ;
     RECT  218.304 48.425 220.446 48.605 ;
     RECT  219.42 48.605 220.446 48.659 ;
     RECT  219.42 48.659 220.338 48.929 ;
     RECT  249.732 48.533 256.497 48.929 ;
     RECT  249.732 48.929 253.818 48.965 ;
     RECT  254.628 48.929 255.402 49.001 ;
     RECT  219.42 48.929 219.798 49.109 ;
     RECT  254.628 49.001 254.718 49.199 ;
     RECT  38.304 48.413 217.458 49.234 ;
     RECT  219.492 49.109 219.798 49.307 ;
     RECT  250.236 48.965 253.782 49.307 ;
     RECT  37.404 49.207 37.422 49.351 ;
     RECT  219.492 49.307 219.654 49.379 ;
     RECT  6.372 43.573 6.39 49.469 ;
     RECT  36.144 49.351 37.422 49.469 ;
     RECT  250.236 49.307 253.638 49.469 ;
     RECT  36.828 49.469 37.422 49.505 ;
     RECT  37.296 49.505 37.422 49.513 ;
     RECT  38.304 49.234 217.494 49.513 ;
     RECT  250.236 49.469 253.566 49.541 ;
     RECT  36 49.477 36.018 49.565 ;
     RECT  37.296 49.513 217.494 49.621 ;
     RECT  218.304 48.605 218.394 49.621 ;
     RECT  219.492 49.379 219.582 49.649 ;
     RECT  37.296 49.621 218.394 49.949 ;
     RECT  219.528 49.649 219.582 50.009 ;
     RECT  37.296 49.949 217.458 50.299 ;
     RECT  218.304 49.949 218.394 50.323 ;
     RECT  218.304 50.323 218.43 50.549 ;
     RECT  219.528 50.009 219.546 50.855 ;
     RECT  37.224 50.299 217.458 50.963 ;
     RECT  37.404 50.963 217.458 50.965 ;
     RECT  218.304 50.549 218.394 50.965 ;
     RECT  219.564 51.061 219.906 51.097 ;
     RECT  219.564 51.097 219.978 51.197 ;
     RECT  37.404 50.965 218.394 51.293 ;
     RECT  37.404 51.293 217.422 51.359 ;
     RECT  38.196 51.359 217.422 51.503 ;
     RECT  37.404 51.359 37.422 51.533 ;
     RECT  219.564 51.197 219.762 51.835 ;
     RECT  219.528 51.835 219.762 51.935 ;
     RECT  219.564 51.935 219.762 52.141 ;
     RECT  219.564 52.141 219.798 52.411 ;
     RECT  38.268 51.503 217.422 52.591 ;
     RECT  218.304 51.293 218.394 52.591 ;
     RECT  38.268 52.591 218.394 52.825 ;
     RECT  219.564 52.411 219.942 53.015 ;
     RECT  37.98 52.825 218.394 53.021 ;
     RECT  37.98 53.021 217.458 53.035 ;
     RECT  37.404 53.035 217.458 53.095 ;
     RECT  37.188 53.095 217.458 53.357 ;
     RECT  219.564 53.015 219.834 53.371 ;
     RECT  218.304 53.021 218.394 53.527 ;
     RECT  219.528 53.371 219.834 53.527 ;
     RECT  218.304 53.527 219.834 53.597 ;
     RECT  219.42 53.597 219.834 53.699 ;
     RECT  37.296 53.357 217.458 54.103 ;
     RECT  219.528 53.699 219.834 54.175 ;
     RECT  34.815 2.413 35.097 54.187 ;
     RECT  37.152 54.103 217.458 54.187 ;
     RECT  218.304 53.597 218.322 54.337 ;
     RECT  36.756 54.187 217.458 54.437 ;
     RECT  43.2 54.437 217.458 54.481 ;
     RECT  218.304 54.337 218.466 54.481 ;
     RECT  43.2 54.481 218.466 54.557 ;
     RECT  219.528 54.175 219.906 54.607 ;
     RECT  36.756 54.437 42.462 54.715 ;
     RECT  219.42 54.607 219.906 54.749 ;
     RECT  4.536 49.549 4.554 54.751 ;
     RECT  219.528 54.749 219.906 54.751 ;
     RECT  218.304 54.557 218.466 54.824 ;
     RECT  9.036 54.751 9.054 54.869 ;
     RECT  2.415 2.413 2.697 54.877 ;
     RECT  5.508 54.751 5.526 54.877 ;
     RECT  0.108 54.859 0.126 54.905 ;
     RECT  21.852 54.841 21.87 54.913 ;
     RECT  22.824 54.877 22.842 54.949 ;
     RECT  26.676 54.877 26.694 54.949 ;
     RECT  2.415 54.877 3.294 54.955 ;
     RECT  4.104 54.751 4.554 54.955 ;
     RECT  22.824 54.949 22.914 54.977 ;
     RECT  33.084 54.751 33.102 54.977 ;
     RECT  34.416 54.187 35.097 54.985 ;
     RECT  5.328 54.877 5.85 55.021 ;
     RECT  7.815 2.413 8.097 55.021 ;
     RECT  16.884 54.877 16.902 55.021 ;
     RECT  24.015 2.413 24.297 55.021 ;
     RECT  26.604 54.949 26.694 55.021 ;
     RECT  34.308 54.985 35.097 55.111 ;
     RECT  16.884 55.021 17.082 55.139 ;
     RECT  21.852 54.913 22.05 55.139 ;
     RECT  26.568 55.021 26.694 55.139 ;
     RECT  34.056 55.111 35.097 55.139 ;
     RECT  13.215 2.413 13.497 55.147 ;
     RECT  219.528 54.751 219.978 55.147 ;
     RECT  16.884 55.139 16.902 55.175 ;
     RECT  21.852 55.139 21.87 55.175 ;
     RECT  24.015 55.021 24.93 55.175 ;
     RECT  0.144 55.051 0.342 55.181 ;
     RECT  18.615 2.413 18.897 55.183 ;
     RECT  22.896 54.977 22.914 55.211 ;
     RECT  26.604 55.139 26.694 55.211 ;
     RECT  219.528 55.147 220.086 55.247 ;
     RECT  25.632 55.243 25.65 55.283 ;
     RECT  43.2 54.557 217.458 55.285 ;
     RECT  218.304 54.824 218.43 55.285 ;
     RECT  5.328 55.021 6.102 55.291 ;
     RECT  6.84 54.751 6.93 55.291 ;
     RECT  10.908 54.877 10.926 55.291 ;
     RECT  34.815 55.139 35.097 55.291 ;
     RECT  43.2 55.285 218.43 55.325 ;
     RECT  2.415 54.955 4.554 55.339 ;
     RECT  10.836 55.291 10.926 55.409 ;
     RECT  18.615 55.183 19.386 55.409 ;
     RECT  34.056 55.139 34.074 55.409 ;
     RECT  218.304 55.325 218.43 55.409 ;
     RECT  5.328 55.291 6.93 55.432 ;
     RECT  12.6 55.147 13.497 55.445 ;
     RECT  30.78 55.291 30.798 55.481 ;
     RECT  10.836 55.409 10.854 55.489 ;
     RECT  34.815 55.291 35.37 55.489 ;
     RECT  2.304 55.339 4.554 55.525 ;
     RECT  5.328 55.432 5.634 55.525 ;
     RECT  6.48 55.432 6.93 55.531 ;
     RECT  7.815 55.021 8.226 55.531 ;
     RECT  14.832 55.147 14.85 55.552 ;
     RECT  10.548 55.489 10.854 55.553 ;
     RECT  12.96 55.445 13.497 55.553 ;
     RECT  20.304 55.291 20.322 55.561 ;
     RECT  26.784 55.453 26.802 55.561 ;
     RECT  30.852 55.489 30.87 55.561 ;
     RECT  219.528 55.247 219.978 55.579 ;
     RECT  26.784 55.561 26.874 55.589 ;
     RECT  9.648 54.949 9.666 55.651 ;
     RECT  20.196 55.561 20.394 55.651 ;
     RECT  34.815 55.489 35.766 55.651 ;
     RECT  36.54 54.715 42.462 55.651 ;
     RECT  27.9 55.525 27.918 55.675 ;
     RECT  2.304 55.525 5.634 55.679 ;
     RECT  10.548 55.553 10.674 55.679 ;
     RECT  16.38 55.291 16.614 55.679 ;
     RECT  27.72 55.675 27.918 55.679 ;
     RECT  20.196 55.651 20.43 55.687 ;
     RECT  0.144 55.181 0.306 55.709 ;
     RECT  6.48 55.531 8.226 55.709 ;
     RECT  33.876 55.525 33.894 55.709 ;
     RECT  0.216 55.709 0.306 55.715 ;
     RECT  10.584 55.679 10.674 55.715 ;
     RECT  16.38 55.679 16.398 55.715 ;
     RECT  26.856 55.589 26.874 55.715 ;
     RECT  27.72 55.679 27.738 55.715 ;
     RECT  2.304 55.679 5.562 55.751 ;
     RECT  10.584 55.715 10.602 55.751 ;
     RECT  14.832 55.552 14.886 55.751 ;
     RECT  34.815 55.651 42.462 55.751 ;
     RECT  30.852 55.561 31.158 55.759 ;
     RECT  36.396 55.751 42.462 55.759 ;
     RECT  43.2 55.325 217.422 55.759 ;
     RECT  20.16 55.687 20.43 55.787 ;
     RECT  0.252 55.715 0.306 55.823 ;
     RECT  20.376 55.787 20.394 55.823 ;
     RECT  30.852 55.759 31.374 55.823 ;
     RECT  33.12 55.561 33.138 55.823 ;
     RECT  0.288 55.823 0.306 55.853 ;
     RECT  2.304 55.751 4.626 55.853 ;
     RECT  5.544 55.751 5.562 55.853 ;
     RECT  2.304 55.853 2.898 55.859 ;
     RECT  14.832 55.751 14.85 55.859 ;
     RECT  18.615 55.409 19.026 55.859 ;
     RECT  34.815 55.751 35.19 55.901 ;
     RECT  3.96 55.853 4.626 55.949 ;
     RECT  9.072 55.651 9.666 55.949 ;
     RECT  30.96 55.823 31.374 55.949 ;
     RECT  218.844 55.579 219.978 55.949 ;
     RECT  2.304 55.859 2.697 55.985 ;
     RECT  4.068 55.949 4.086 55.985 ;
     RECT  6.48 55.709 8.097 55.985 ;
     RECT  9.144 55.949 9.666 55.985 ;
     RECT  36.396 55.759 217.422 55.985 ;
     RECT  36.396 55.985 36.414 56.057 ;
     RECT  31.356 55.949 31.374 56.129 ;
     RECT  32.364 56.101 32.382 56.203 ;
     RECT  6.732 55.985 6.894 56.219 ;
     RECT  32.22 56.203 32.382 56.219 ;
     RECT  6.732 56.219 6.75 56.255 ;
     RECT  32.22 56.219 32.238 56.255 ;
     RECT  218.844 55.949 219.942 56.497 ;
     RECT  37.152 55.985 217.422 56.524 ;
     RECT  218.304 56.497 219.942 56.561 ;
     RECT  219.528 56.561 219.942 56.923 ;
     RECT  37.152 56.524 217.458 57.181 ;
     RECT  218.304 56.561 218.43 57.181 ;
     RECT  37.152 57.181 218.43 57.245 ;
     RECT  218.304 57.245 218.43 57.343 ;
     RECT  5.22 57.019 5.238 57.451 ;
     RECT  5.22 57.451 5.634 57.569 ;
     RECT  218.304 57.343 218.466 57.569 ;
     RECT  219.528 56.923 219.978 57.569 ;
     RECT  5.22 57.569 5.346 57.581 ;
     RECT  219.528 57.569 219.834 58.171 ;
     RECT  37.152 57.245 217.458 58.261 ;
     RECT  218.304 57.569 218.394 58.261 ;
     RECT  2.415 55.985 2.697 58.351 ;
     RECT  5.22 57.581 5.238 58.531 ;
     RECT  219.42 58.171 219.834 58.531 ;
     RECT  5.22 58.531 5.346 58.621 ;
     RECT  219.42 58.531 219.978 58.649 ;
     RECT  9.648 55.985 9.666 58.693 ;
     RECT  6.336 58.531 6.354 58.765 ;
     RECT  9.576 58.693 9.666 58.765 ;
     RECT  219.42 58.649 219.834 58.781 ;
     RECT  219.456 58.781 219.834 58.793 ;
     RECT  4.212 58.531 4.23 58.801 ;
     RECT  5.148 58.621 5.346 58.801 ;
     RECT  34.815 55.901 35.097 58.801 ;
     RECT  30.78 58.801 30.87 58.843 ;
     RECT  37.152 58.261 218.394 58.877 ;
     RECT  7.815 55.985 8.097 58.891 ;
     RECT  9.576 58.765 9.738 58.891 ;
     RECT  10.8 58.729 10.818 58.891 ;
     RECT  13.215 55.553 13.497 58.891 ;
     RECT  18.615 55.859 18.897 58.891 ;
     RECT  33.444 58.765 33.462 58.919 ;
     RECT  18.252 58.891 18.897 58.927 ;
     RECT  37.152 58.877 217.422 58.927 ;
     RECT  13.104 58.891 13.497 58.928 ;
     RECT  18.252 58.927 18.954 58.928 ;
     RECT  218.304 58.877 218.394 58.963 ;
     RECT  4.212 58.801 5.598 58.987 ;
     RECT  6.336 58.765 6.462 58.987 ;
     RECT  7.704 58.891 8.097 58.991 ;
     RECT  30.78 58.843 31.554 58.991 ;
     RECT  2.415 58.351 3.15 59.035 ;
     RECT  4.212 58.987 6.462 59.035 ;
     RECT  37.044 58.927 217.422 59.069 ;
     RECT  1.728 59.035 3.15 59.071 ;
     RECT  4.212 59.035 6.75 59.071 ;
     RECT  7.74 58.991 8.097 59.071 ;
     RECT  9.576 58.891 10.818 59.071 ;
     RECT  30.78 58.991 30.87 59.071 ;
     RECT  34.38 58.801 35.097 59.071 ;
     RECT  0.54 58.999 0.558 59.083 ;
     RECT  7.74 59.071 10.818 59.099 ;
     RECT  1.728 59.071 6.75 59.117 ;
     RECT  30.564 59.071 30.87 59.117 ;
     RECT  7.74 59.099 9.594 59.189 ;
     RECT  10.44 59.099 10.818 59.189 ;
     RECT  14.832 59.071 14.85 59.189 ;
     RECT  34.236 59.071 35.097 59.189 ;
     RECT  218.304 58.963 218.466 59.189 ;
     RECT  20.052 58.801 20.07 59.197 ;
     RECT  0.108 59.083 0.558 59.213 ;
     RECT  4.104 59.117 6.75 59.225 ;
     RECT  11.952 58.801 11.97 59.225 ;
     RECT  18.396 58.928 18.954 59.225 ;
     RECT  35.928 58.729 35.946 59.233 ;
     RECT  37.044 59.069 41.346 59.233 ;
     RECT  26.784 58.927 26.802 59.275 ;
     RECT  42.192 59.069 217.422 59.357 ;
     RECT  1.728 59.117 3.366 59.369 ;
     RECT  20.052 59.197 20.43 59.369 ;
     RECT  7.74 59.189 8.838 59.468 ;
     RECT  33.624 59.461 33.642 59.501 ;
     RECT  219.6 58.793 219.834 59.539 ;
     RECT  34.704 59.189 35.097 59.563 ;
     RECT  35.928 59.233 41.346 59.563 ;
     RECT  34.704 59.563 41.346 59.597 ;
     RECT  42.444 59.357 217.422 59.605 ;
     RECT  218.304 59.189 218.394 59.605 ;
     RECT  29.415 2.413 29.697 59.611 ;
     RECT  30.708 59.117 30.87 59.639 ;
     RECT  42.444 59.605 218.394 59.639 ;
     RECT  0.108 59.213 0.162 59.693 ;
     RECT  20.052 59.369 20.286 59.729 ;
     RECT  26.568 59.275 26.802 59.729 ;
     RECT  30.708 59.639 30.798 59.729 ;
     RECT  219.6 59.539 219.978 59.729 ;
     RECT  219.6 59.729 219.834 59.737 ;
     RECT  20.052 59.729 20.07 59.765 ;
     RECT  34.815 59.597 41.346 59.765 ;
     RECT  5.616 59.225 6.75 59.773 ;
     RECT  7.74 59.468 8.802 59.773 ;
     RECT  29.088 59.611 29.697 59.809 ;
     RECT  4.104 59.225 4.698 59.837 ;
     RECT  26.784 59.729 26.802 59.837 ;
     RECT  36.288 59.765 36.774 59.837 ;
     RECT  219.528 59.737 219.834 59.873 ;
     RECT  1.728 59.369 3.186 59.885 ;
     RECT  42.444 59.639 218.322 59.933 ;
     RECT  1.764 59.885 3.186 59.981 ;
     RECT  5.616 59.773 8.802 59.999 ;
     RECT  10.44 59.189 10.458 59.999 ;
     RECT  17.244 59.881 17.262 59.999 ;
     RECT  29.016 59.809 29.697 59.999 ;
     RECT  5.616 59.999 5.994 60.035 ;
     RECT  28.26 59.809 28.278 60.035 ;
     RECT  219.744 59.873 219.834 60.035 ;
     RECT  10.512 60.007 10.53 60.043 ;
     RECT  6.84 59.999 8.802 60.107 ;
     RECT  10.512 60.043 10.818 60.107 ;
     RECT  37.548 59.765 41.346 60.115 ;
     RECT  2.415 59.981 3.186 60.151 ;
     RECT  4.104 59.837 4.626 60.151 ;
     RECT  0.108 59.693 0.126 60.179 ;
     RECT  2.415 60.151 4.626 60.179 ;
     RECT  10.8 60.107 10.818 60.179 ;
     RECT  43.2 59.933 218.322 60.221 ;
     RECT  3.456 60.179 4.626 60.269 ;
     RECT  5.616 60.035 5.922 60.269 ;
     RECT  6.84 60.107 6.858 60.269 ;
     RECT  3.456 60.269 4.554 60.317 ;
     RECT  7.815 60.107 8.802 60.317 ;
     RECT  37.548 60.115 41.634 60.376 ;
     RECT  42.444 59.933 42.462 60.376 ;
     RECT  5.904 60.269 5.922 60.413 ;
     RECT  36.648 59.837 36.774 60.511 ;
     RECT  37.548 60.376 42.462 60.511 ;
     RECT  218.304 60.221 218.322 60.511 ;
     RECT  4.104 60.317 4.266 60.539 ;
     RECT  36.648 60.511 42.462 60.539 ;
     RECT  4.104 60.539 4.122 60.575 ;
     RECT  36.756 60.539 42.462 60.809 ;
     RECT  219.78 60.035 219.834 60.859 ;
     RECT  37.62 60.809 42.462 60.889 ;
     RECT  43.2 60.221 217.422 60.889 ;
     RECT  219.744 60.859 219.834 60.955 ;
     RECT  219.744 60.955 219.942 61.087 ;
     RECT  37.62 60.889 217.422 61.231 ;
     RECT  218.304 60.511 218.394 61.231 ;
     RECT  219.528 61.087 219.942 61.231 ;
     RECT  37.62 61.231 218.394 61.277 ;
     RECT  37.62 61.277 217.422 61.349 ;
     RECT  218.304 61.277 218.394 61.349 ;
     RECT  219.528 61.231 219.978 61.655 ;
     RECT  37.836 61.349 217.422 61.949 ;
     RECT  37.836 61.949 42.462 62.131 ;
     RECT  219.564 61.655 219.978 62.159 ;
     RECT  37.332 62.131 42.462 62.251 ;
     RECT  36.864 62.251 42.462 62.303 ;
     RECT  218.304 61.349 218.322 62.311 ;
     RECT  218.304 62.311 218.466 62.465 ;
     RECT  218.304 62.465 218.394 62.537 ;
     RECT  43.2 61.949 217.422 62.581 ;
     RECT  218.304 62.537 218.358 62.581 ;
     RECT  219.564 62.159 219.942 62.581 ;
     RECT  219.42 62.581 219.942 62.635 ;
     RECT  37.152 62.303 42.462 62.671 ;
     RECT  43.2 62.581 218.358 62.671 ;
     RECT  37.152 62.671 218.358 62.699 ;
     RECT  219.384 62.635 219.942 62.779 ;
     RECT  219.312 62.779 219.942 62.816 ;
     RECT  37.152 62.699 218.322 62.861 ;
     RECT  219.42 62.816 219.942 63.005 ;
     RECT  41.688 62.861 217.746 63.149 ;
     RECT  42.156 63.149 217.746 63.197 ;
     RECT  37.152 62.861 40.806 63.211 ;
     RECT  219.42 63.005 219.834 63.643 ;
     RECT  36.684 63.211 40.806 63.851 ;
     RECT  37.188 63.851 40.806 63.923 ;
     RECT  42.156 63.197 217.422 63.925 ;
     RECT  37.188 63.923 40.77 64.049 ;
     RECT  42.156 63.925 217.746 64.201 ;
     RECT  41.616 64.201 217.746 64.253 ;
     RECT  41.616 64.253 217.422 64.349 ;
     RECT  218.844 63.643 219.834 64.435 ;
     RECT  37.224 64.049 40.77 64.499 ;
     RECT  218.304 64.435 219.834 64.507 ;
     RECT  218.304 64.507 219.942 64.625 ;
     RECT  37.296 64.499 40.77 64.697 ;
     RECT  41.76 64.349 217.422 64.697 ;
     RECT  42.156 64.697 217.422 64.733 ;
     RECT  4.536 64.795 4.554 64.831 ;
     RECT  13.215 58.928 13.497 64.831 ;
     RECT  5.904 64.795 5.922 64.859 ;
     RECT  4.356 64.831 4.554 64.877 ;
     RECT  13.104 64.831 13.497 64.877 ;
     RECT  42.156 64.733 217.32 64.931 ;
     RECT  218.844 64.625 219.942 64.931 ;
     RECT  4.536 64.877 4.554 65.129 ;
     RECT  42.444 64.931 217.32 65.165 ;
     RECT  219.456 64.931 219.942 65.165 ;
     RECT  219.456 65.165 219.834 65.399 ;
     RECT  37.476 64.697 40.77 65.713 ;
     RECT  37.404 65.713 40.77 65.785 ;
     RECT  37.296 65.785 40.77 66.361 ;
     RECT  36.756 66.361 40.77 67.181 ;
     RECT  37.548 67.181 40.77 67.433 ;
     RECT  37.548 67.433 38.034 67.829 ;
     RECT  37.584 67.829 38.034 68.189 ;
     RECT  37.836 68.189 38.034 69.251 ;
     RECT  16.056 69.331 16.074 69.421 ;
     RECT  17.568 69.331 17.586 69.457 ;
     RECT  14.832 69.421 14.85 69.493 ;
     RECT  16.056 69.421 16.47 69.493 ;
     RECT  17.244 69.457 17.586 69.493 ;
     RECT  38.88 67.433 40.77 69.529 ;
     RECT  24.015 55.175 24.297 69.601 ;
     RECT  23.688 69.601 24.297 69.691 ;
     RECT  25.056 69.601 25.074 69.691 ;
     RECT  22.68 69.691 22.698 69.799 ;
     RECT  23.688 69.691 25.074 69.799 ;
     RECT  25.92 63.391 25.938 69.799 ;
     RECT  42.444 65.165 42.462 69.799 ;
     RECT  43.2 65.165 217.32 69.799 ;
     RECT  23.508 69.799 25.938 69.827 ;
     RECT  22.608 69.799 22.698 69.835 ;
     RECT  23.508 69.827 24.498 69.835 ;
     RECT  14.832 69.493 17.586 69.871 ;
     RECT  18.615 59.225 18.897 69.871 ;
     RECT  20.268 69.835 20.286 69.871 ;
     RECT  38.88 69.529 41.022 69.989 ;
     RECT  14.58 69.871 18.897 70.025 ;
     RECT  22.14 69.835 24.498 70.033 ;
     RECT  14.652 70.025 18.897 70.069 ;
     RECT  19.944 69.871 20.718 70.069 ;
     RECT  14.652 70.069 20.718 70.075 ;
     RECT  14.652 70.075 20.934 70.411 ;
     RECT  21.708 70.033 24.498 70.411 ;
     RECT  34.815 59.765 35.097 70.501 ;
     RECT  14.652 70.411 24.498 70.555 ;
     RECT  14.652 70.555 24.606 70.573 ;
     RECT  34.632 70.501 35.097 70.573 ;
     RECT  14.652 70.573 24.678 70.603 ;
     RECT  25.668 69.827 25.686 70.645 ;
     RECT  13.215 64.877 13.497 70.681 ;
     RECT  14.652 70.603 24.714 70.681 ;
     RECT  25.452 70.645 25.686 70.681 ;
     RECT  34.344 70.573 35.097 70.681 ;
     RECT  29.415 59.999 29.697 70.771 ;
     RECT  33.732 70.681 35.097 70.771 ;
     RECT  13.215 70.681 13.842 70.843 ;
     RECT  14.652 70.681 25.686 70.843 ;
     RECT  36.756 67.181 36.774 70.843 ;
     RECT  29.415 70.771 29.934 70.879 ;
     RECT  30.744 70.771 30.762 70.879 ;
     RECT  13.212 70.843 25.686 70.915 ;
     RECT  32.508 70.681 32.526 70.915 ;
     RECT  33.588 70.771 35.406 70.915 ;
     RECT  12.996 70.915 25.686 70.951 ;
     RECT  37.836 69.251 37.854 70.951 ;
     RECT  42.444 69.799 217.32 70.979 ;
     RECT  36.396 70.843 36.774 71.069 ;
     RECT  32.508 70.915 35.406 71.077 ;
     RECT  31.644 70.951 31.662 71.113 ;
     RECT  32.508 71.077 35.982 71.113 ;
     RECT  29.415 70.879 30.762 71.179 ;
     RECT  29.088 71.179 30.762 71.185 ;
     RECT  31.644 71.113 35.982 71.185 ;
     RECT  12.996 70.951 26.01 71.311 ;
     RECT  27.504 71.491 27.522 71.549 ;
     RECT  12.996 71.311 26.19 71.617 ;
     RECT  12.456 71.617 26.19 71.653 ;
     RECT  11.808 71.653 26.19 71.689 ;
     RECT  29.088 71.185 35.982 71.761 ;
     RECT  11.628 71.689 26.19 71.851 ;
     RECT  11.412 71.851 26.19 71.887 ;
     RECT  11.412 71.887 26.226 71.995 ;
     RECT  28.584 71.761 35.982 71.995 ;
     RECT  36.756 71.069 36.774 71.995 ;
     RECT  10.44 71.707 10.458 72.031 ;
     RECT  11.304 71.995 26.226 72.031 ;
     RECT  37.656 70.951 37.854 72.031 ;
     RECT  38.88 69.989 40.77 72.031 ;
     RECT  10.44 72.031 26.262 72.077 ;
     RECT  10.44 72.077 26.226 72.149 ;
     RECT  10.44 72.149 26.082 72.265 ;
     RECT  37.656 72.031 40.77 72.265 ;
     RECT  28.584 71.995 36.774 72.535 ;
     RECT  37.656 72.265 41.058 72.535 ;
     RECT  42.48 70.979 217.32 72.936 ;
     RECT  10.368 72.265 26.082 72.959 ;
     RECT  17.64 72.959 26.082 72.967 ;
     RECT  27.288 73.003 27.306 73.039 ;
     RECT  10.368 72.959 16.83 73.103 ;
     RECT  17.64 72.967 26.154 73.111 ;
     RECT  27.288 73.039 27.81 73.111 ;
     RECT  17.64 73.111 26.226 73.201 ;
     RECT  27.288 73.111 27.846 73.201 ;
     RECT  10.368 73.103 16.326 73.229 ;
     RECT  42.48 72.936 42.498 73.265 ;
     RECT  254.7 49.199 254.718 73.265 ;
     RECT  17.64 73.201 27.846 73.273 ;
     RECT  28.584 72.535 41.058 73.273 ;
     RECT  17.64 73.273 41.058 73.409 ;
     RECT  17.64 73.409 27.882 73.499 ;
     RECT  51.408 72.936 51.426 73.813 ;
     RECT  252.432 49.541 253.566 73.841 ;
     RECT  49.14 72.936 49.158 73.849 ;
     RECT  28.62 73.409 41.058 73.877 ;
     RECT  10.368 73.229 15.93 74.083 ;
     RECT  60.48 72.936 60.498 74.155 ;
     RECT  10.368 74.083 16.002 74.191 ;
     RECT  21.456 73.499 27.882 74.251 ;
     RECT  10.368 74.191 16.614 74.281 ;
     RECT  17.748 73.499 20.538 74.281 ;
     RECT  21.276 74.251 27.882 74.281 ;
     RECT  148.068 72.936 148.086 74.353 ;
     RECT  250.815 49.541 251.586 74.381 ;
     RECT  10.368 74.281 27.882 74.539 ;
     RECT  9.576 59.189 9.594 74.551 ;
     RECT  10.368 74.539 27.954 74.551 ;
     RECT  9.576 74.551 27.954 74.615 ;
     RECT  9.72 74.615 27.954 74.623 ;
     RECT  28.8 73.877 40.497 74.623 ;
     RECT  60.336 74.155 60.498 74.659 ;
     RECT  7.815 60.317 8.097 74.731 ;
     RECT  9.72 74.623 40.497 74.731 ;
     RECT  253.116 73.841 253.566 74.957 ;
     RECT  45.504 72.936 45.522 75.043 ;
     RECT  51.408 73.813 51.462 75.043 ;
     RECT  55.908 74.353 55.926 75.043 ;
     RECT  147.528 74.353 148.086 75.043 ;
     RECT  45.504 75.043 45.705 75.091 ;
     RECT  72.576 75.001 72.954 75.091 ;
     RECT  94.215 75.043 94.305 75.091 ;
     RECT  55.908 75.043 56.505 75.127 ;
     RECT  57.492 75.091 57.51 75.127 ;
     RECT  60.336 74.659 60.75 75.127 ;
     RECT  61.815 75.043 61.905 75.157 ;
     RECT  61.632 75.157 61.905 75.163 ;
     RECT  110.415 75.043 110.505 75.163 ;
     RECT  94.068 75.091 94.305 75.197 ;
     RECT  45.144 75.091 45.705 75.199 ;
     RECT  47.376 75.091 47.394 75.199 ;
     RECT  49.14 73.849 49.266 75.199 ;
     RECT  65.808 75.001 65.826 75.199 ;
     RECT  67.215 75.043 67.305 75.199 ;
     RECT  71.856 75.091 72.954 75.199 ;
     RECT  78.015 75.043 78.105 75.199 ;
     RECT  83.415 75.043 83.505 75.199 ;
     RECT  88.815 75.043 88.905 75.199 ;
     RECT  94.215 75.197 94.305 75.199 ;
     RECT  99.615 75.043 99.705 75.199 ;
     RECT  105.015 75.043 105.105 75.199 ;
     RECT  115.815 75.043 115.905 75.199 ;
     RECT  121.215 75.043 121.305 75.199 ;
     RECT  128.412 74.923 128.43 75.199 ;
     RECT  9.72 74.731 40.842 75.227 ;
     RECT  9.9 75.227 40.842 75.235 ;
     RECT  44.028 75.199 45.705 75.235 ;
     RECT  55.908 75.127 57.51 75.235 ;
     RECT  58.392 75.199 58.41 75.235 ;
     RECT  59.832 75.127 60.75 75.235 ;
     RECT  61.56 75.163 61.905 75.235 ;
     RECT  65.808 75.199 66.042 75.235 ;
     RECT  55.908 75.235 58.698 75.259 ;
     RECT  65.052 75.235 66.042 75.259 ;
     RECT  67.14 75.199 67.305 75.259 ;
     RECT  126.615 75.043 126.705 75.259 ;
     RECT  128.124 75.199 128.43 75.259 ;
     RECT  9.9 75.235 40.95 75.263 ;
     RECT  47.376 75.199 49.266 75.271 ;
     RECT  54.396 74.683 54.414 75.271 ;
     RECT  55.908 75.259 58.734 75.271 ;
     RECT  63.108 75.259 63.126 75.271 ;
     RECT  70.884 75.259 70.902 75.271 ;
     RECT  71.856 75.199 73.026 75.271 ;
     RECT  78.015 75.199 78.39 75.293 ;
     RECT  88.815 75.199 89.19 75.293 ;
     RECT  94.215 75.199 94.59 75.293 ;
     RECT  99.615 75.199 99.99 75.293 ;
     RECT  105.015 75.199 105.39 75.293 ;
     RECT  110.415 75.163 110.79 75.293 ;
     RECT  115.815 75.199 116.19 75.293 ;
     RECT  121.215 75.199 121.59 75.293 ;
     RECT  128.124 75.259 128.754 75.293 ;
     RECT  43.884 75.235 45.705 75.313 ;
     RECT  59.544 75.235 61.905 75.313 ;
     RECT  65.052 75.259 67.305 75.313 ;
     RECT  126.54 75.259 126.705 75.313 ;
     RECT  132.015 75.043 132.105 75.313 ;
     RECT  137.415 75.043 137.505 75.313 ;
     RECT  142.815 75.043 142.905 75.313 ;
     RECT  147.528 75.043 148.305 75.313 ;
     RECT  149.148 74.929 149.166 75.313 ;
     RECT  153.615 75.043 153.705 75.313 ;
     RECT  159.015 75.043 159.105 75.313 ;
     RECT  164.415 75.043 164.505 75.313 ;
     RECT  169.815 75.043 169.905 75.313 ;
     RECT  175.215 75.043 175.305 75.313 ;
     RECT  180.615 75.043 180.705 75.313 ;
     RECT  186.015 75.043 186.105 75.313 ;
     RECT  191.415 75.043 191.505 75.313 ;
     RECT  196.815 75.043 196.905 75.313 ;
     RECT  202.215 75.043 202.305 75.313 ;
     RECT  207.615 75.043 207.705 75.313 ;
     RECT  213.015 75.043 213.105 75.313 ;
     RECT  218.415 75.043 218.505 75.313 ;
     RECT  63.108 75.271 63.738 75.355 ;
     RECT  68.76 75.271 68.85 75.355 ;
     RECT  22.176 75.263 40.95 75.361 ;
     RECT  51.015 75.043 51.462 75.361 ;
     RECT  59.544 75.313 62.097 75.361 ;
     RECT  9.9 75.263 15.354 75.389 ;
     RECT  128.448 75.293 128.754 75.389 ;
     RECT  42.408 75.271 42.426 75.397 ;
     RECT  54.396 75.271 58.806 75.397 ;
     RECT  59.544 75.361 62.154 75.397 ;
     RECT  65.052 75.313 67.497 75.397 ;
     RECT  68.76 75.355 69.246 75.397 ;
     RECT  75.888 75.271 75.906 75.397 ;
     RECT  93.024 74.923 93.042 75.425 ;
     RECT  253.548 74.957 253.566 75.425 ;
     RECT  22.176 75.361 41.094 75.433 ;
     RECT  41.94 75.397 42.426 75.433 ;
     RECT  54.396 75.397 62.154 75.433 ;
     RECT  70.308 75.271 70.902 75.433 ;
     RECT  71.712 75.271 74.07 75.433 ;
     RECT  83.415 75.199 83.79 75.433 ;
     RECT  194.076 73.813 194.094 75.433 ;
     RECT  126.54 75.313 126.897 75.485 ;
     RECT  64.62 75.397 69.246 75.505 ;
     RECT  70.308 75.433 74.07 75.505 ;
     RECT  47.34 75.271 49.266 75.541 ;
     RECT  63.108 75.355 63.846 75.541 ;
     RECT  74.844 75.397 74.862 75.541 ;
     RECT  75.816 75.397 75.906 75.541 ;
     RECT  93.312 75.451 93.33 75.569 ;
     RECT  128.448 75.389 128.466 75.569 ;
     RECT  194.076 75.433 194.382 75.569 ;
     RECT  43.884 75.313 45.897 75.631 ;
     RECT  50.436 75.361 51.462 75.631 ;
     RECT  53.748 75.433 62.154 75.631 ;
     RECT  147.528 75.313 149.166 75.659 ;
     RECT  47.304 75.541 49.266 75.667 ;
     RECT  50.436 75.631 52.002 75.667 ;
     RECT  43.884 75.631 46.566 75.733 ;
     RECT  43.74 75.733 46.566 75.775 ;
     RECT  47.304 75.667 52.002 75.775 ;
     RECT  63.108 75.541 63.882 75.775 ;
     RECT  64.62 75.505 74.07 75.775 ;
     RECT  53.604 75.631 62.154 75.787 ;
     RECT  63.108 75.775 74.07 75.787 ;
     RECT  53.604 75.787 74.07 75.811 ;
     RECT  74.844 75.541 76.518 75.811 ;
     RECT  43.668 75.775 52.47 75.901 ;
     RECT  53.388 75.811 76.518 75.901 ;
     RECT  22.176 75.433 42.426 76.045 ;
     RECT  9.9 75.389 15.318 76.081 ;
     RECT  16.092 75.263 21.402 76.171 ;
     RECT  22.176 76.045 42.93 76.171 ;
     RECT  147.528 75.659 148.914 76.199 ;
     RECT  16.092 76.171 42.93 76.207 ;
     RECT  43.668 75.901 76.518 76.207 ;
     RECT  9.864 76.081 15.318 76.315 ;
     RECT  16.092 76.207 76.518 76.315 ;
     RECT  9.864 76.315 76.518 76.351 ;
     RECT  9.576 76.351 76.518 76.477 ;
     RECT  78.015 75.293 78.297 76.477 ;
     RECT  77.436 76.477 78.354 76.621 ;
     RECT  145.512 76.621 145.53 76.739 ;
     RECT  80.532 76.819 80.55 76.855 ;
     RECT  9.576 76.477 76.662 76.883 ;
     RECT  77.436 76.621 78.678 76.891 ;
     RECT  79.956 76.855 80.694 76.891 ;
     RECT  145.728 76.855 145.746 76.925 ;
     RECT  79.956 76.891 81.234 76.939 ;
     RECT  146.7 76.855 146.718 77.045 ;
     RECT  147.528 76.199 148.497 77.117 ;
     RECT  79.596 76.939 81.27 77.125 ;
     RECT  145.944 77.089 145.962 77.125 ;
     RECT  9.684 76.883 48.042 77.153 ;
     RECT  48.852 76.883 76.662 77.161 ;
     RECT  77.436 76.891 78.75 77.161 ;
     RECT  79.596 77.125 81.954 77.287 ;
     RECT  10.116 77.153 48.042 77.387 ;
     RECT  79.56 77.287 81.954 77.396 ;
     RECT  83.415 75.433 84.114 77.431 ;
     RECT  10.116 77.387 25.47 77.453 ;
     RECT  10.116 77.453 22.05 77.549 ;
     RECT  147.384 77.125 147.402 77.549 ;
     RECT  48.852 77.161 78.75 77.557 ;
     RECT  79.56 77.396 81.918 77.557 ;
     RECT  26.208 77.387 48.042 77.665 ;
     RECT  48.852 77.557 81.918 77.665 ;
     RECT  26.208 77.665 81.918 77.693 ;
     RECT  219.816 65.399 219.834 77.819 ;
     RECT  148.215 77.117 148.497 77.935 ;
     RECT  10.116 77.549 21.906 77.971 ;
     RECT  144.936 77.755 144.954 77.971 ;
     RECT  9.612 77.971 21.906 78.077 ;
     RECT  148.032 77.935 148.497 78.089 ;
     RECT  144.756 77.971 144.954 78.133 ;
     RECT  145.944 77.125 146.25 78.133 ;
     RECT  26.208 77.693 38.394 78.173 ;
     RECT  22.824 77.453 25.47 78.205 ;
     RECT  26.208 78.173 27.702 78.205 ;
     RECT  10.188 78.077 21.906 78.233 ;
     RECT  144.756 78.133 146.25 78.233 ;
     RECT  144.756 78.233 145.386 78.359 ;
     RECT  10.44 78.233 21.906 78.475 ;
     RECT  22.824 78.205 27.702 78.475 ;
     RECT  39.168 77.693 81.918 78.475 ;
     RECT  82.692 77.431 84.114 78.475 ;
     RECT  143.964 78.091 143.982 78.629 ;
     RECT  145.296 78.359 145.386 78.629 ;
     RECT  4.284 77.701 4.302 78.673 ;
     RECT  7.164 74.731 8.097 78.709 ;
     RECT  4.284 78.673 4.374 78.745 ;
     RECT  28.476 78.173 38.394 78.745 ;
     RECT  39.168 78.475 84.114 78.745 ;
     RECT  10.44 78.475 27.702 78.979 ;
     RECT  28.476 78.745 84.114 78.979 ;
     RECT  250.815 74.381 251.097 79.003 ;
     RECT  3.492 79.015 3.51 79.051 ;
     RECT  4.284 78.745 4.518 79.051 ;
     RECT  10.44 78.979 84.114 79.051 ;
     RECT  6.84 78.709 8.097 79.169 ;
     RECT  194.076 75.569 194.094 79.169 ;
     RECT  10.26 79.051 84.114 79.177 ;
     RECT  133.056 79.141 133.074 79.181 ;
     RECT  250.236 79.003 251.097 79.181 ;
     RECT  9.36 78.511 9.45 79.195 ;
     RECT  132.015 75.313 132.297 79.195 ;
     RECT  131.508 79.195 132.297 79.241 ;
     RECT  148.215 78.089 148.497 79.243 ;
     RECT  142.815 75.313 143.097 79.411 ;
     RECT  5.58 79.249 5.598 79.439 ;
     RECT  144.108 78.781 144.126 79.439 ;
     RECT  3.492 79.051 4.518 79.591 ;
     RECT  9 79.195 9.45 79.591 ;
     RECT  10.188 79.177 84.114 79.591 ;
     RECT  146.232 78.233 146.25 79.591 ;
     RECT  86.184 79.177 86.202 79.709 ;
     RECT  147.852 79.243 148.497 79.709 ;
     RECT  2.415 60.179 2.697 79.717 ;
     RECT  3.492 79.591 4.662 79.717 ;
     RECT  146.232 79.591 146.718 79.717 ;
     RECT  9 79.591 84.114 79.753 ;
     RECT  146.232 79.717 146.934 79.757 ;
     RECT  2.415 79.717 4.662 79.861 ;
     RECT  145.296 78.629 145.314 79.979 ;
     RECT  2.415 79.861 4.698 80.131 ;
     RECT  9 79.753 84.15 80.249 ;
     RECT  2.415 80.131 4.914 80.257 ;
     RECT  5.688 80.131 5.706 80.257 ;
     RECT  9 80.249 84.114 80.321 ;
     RECT  9 80.321 83.898 80.329 ;
     RECT  7.164 79.169 8.097 80.365 ;
     RECT  2.415 80.257 5.706 80.381 ;
     RECT  121.215 75.293 121.497 80.491 ;
     RECT  130.176 80.485 130.194 80.525 ;
     RECT  121.104 80.491 121.497 80.528 ;
     RECT  2.415 80.381 5.382 80.635 ;
     RECT  132.015 79.241 132.297 80.671 ;
     RECT  131.724 80.671 132.297 80.957 ;
     RECT  0.144 80.329 0.162 81.163 ;
     RECT  6.84 80.365 8.097 81.175 ;
     RECT  8.928 80.329 83.898 81.175 ;
     RECT  6.84 81.175 83.898 81.211 ;
     RECT  6.696 81.211 83.898 81.337 ;
     RECT  106.848 80.131 106.866 81.365 ;
     RECT  6.696 81.337 83.934 81.409 ;
     RECT  1.728 80.635 5.382 81.445 ;
     RECT  6.696 81.409 84.33 81.481 ;
     RECT  1.728 81.445 5.562 81.485 ;
     RECT  2.304 81.485 5.562 81.751 ;
     RECT  6.336 81.481 84.33 81.751 ;
     RECT  0.108 81.163 0.162 82.123 ;
     RECT  0.108 82.123 0.558 82.247 ;
     RECT  2.304 81.751 84.33 82.453 ;
     RECT  2.304 82.453 84.366 82.651 ;
     RECT  2.304 82.651 85.086 82.679 ;
     RECT  142.815 79.411 143.262 83.021 ;
     RECT  1.296 82.507 1.314 83.065 ;
     RECT  2.304 82.679 84.33 83.065 ;
     RECT  1.296 83.065 84.33 83.083 ;
     RECT  1.188 83.083 84.33 83.659 ;
     RECT  142.815 83.021 143.097 83.755 ;
     RECT  1.152 83.659 84.33 83.885 ;
     RECT  0.108 82.247 0.126 83.947 ;
     RECT  1.152 83.885 1.206 83.947 ;
     RECT  0.108 83.947 1.206 84.065 ;
     RECT  0.108 84.065 1.17 84.137 ;
     RECT  1.152 84.137 1.17 84.173 ;
     RECT  146.232 79.757 146.25 84.299 ;
     RECT  0.108 84.137 0.27 84.331 ;
     RECT  0.036 84.331 0.27 84.365 ;
     RECT  2.304 83.885 84.33 84.451 ;
     RECT  85.068 82.679 85.086 84.451 ;
     RECT  2.304 84.451 85.086 85.451 ;
     RECT  132.015 80.957 132.297 85.483 ;
     RECT  55.26 85.451 85.086 85.531 ;
     RECT  85.932 80.599 85.95 85.531 ;
     RECT  146.196 84.343 146.214 85.579 ;
     RECT  142.815 83.755 143.334 85.627 ;
     RECT  145.764 85.579 146.214 85.649 ;
     RECT  132.015 85.483 132.39 85.661 ;
     RECT  55.26 85.531 85.95 85.685 ;
     RECT  2.304 85.451 54.522 85.757 ;
     RECT  142.524 85.627 143.334 85.757 ;
     RECT  145.44 85.72 145.458 85.757 ;
     RECT  110.415 75.293 110.697 85.891 ;
     RECT  110.415 85.891 111.366 85.949 ;
     RECT  55.476 85.685 85.95 85.999 ;
     RECT  110.415 85.949 111.15 86.237 ;
     RECT  87.048 85.189 87.066 86.539 ;
     RECT  55.476 85.999 86.058 86.611 ;
     RECT  86.796 86.539 87.066 86.611 ;
     RECT  55.476 86.611 87.066 86.701 ;
     RECT  2.304 85.757 54.378 86.765 ;
     RECT  55.476 86.701 87.138 87.035 ;
     RECT  55.512 87.035 87.138 87.151 ;
     RECT  2.34 86.765 54.378 87.269 ;
     RECT  55.512 87.151 87.282 87.305 ;
     RECT  55.62 87.305 87.282 87.341 ;
     RECT  2.376 87.269 54.378 87.575 ;
     RECT  55.656 87.341 87.282 87.691 ;
     RECT  146.196 85.649 146.214 87.787 ;
     RECT  0.036 84.365 0.054 87.845 ;
     RECT  55.656 87.691 87.462 87.925 ;
     RECT  2.415 87.575 54.378 88.079 ;
     RECT  146.196 87.787 146.862 88.079 ;
     RECT  146.196 88.079 146.214 88.195 ;
     RECT  55.656 87.925 87.858 88.231 ;
     RECT  88.815 75.293 89.097 88.231 ;
     RECT  145.872 88.195 146.214 88.253 ;
     RECT  4.104 88.079 54.378 88.397 ;
     RECT  94.215 75.293 94.497 88.411 ;
     RECT  4.104 88.397 49.986 88.421 ;
     RECT  4.14 88.421 48.006 88.457 ;
     RECT  50.724 88.397 54.378 88.459 ;
     RECT  48.78 88.421 49.986 88.619 ;
     RECT  94.215 88.411 95.094 88.619 ;
     RECT  50.724 88.459 54.738 88.771 ;
     RECT  55.656 88.231 87.966 88.771 ;
     RECT  88.74 88.231 89.097 88.771 ;
     RECT  4.14 88.457 47.79 88.799 ;
     RECT  50.724 88.771 89.097 88.889 ;
     RECT  96.624 88.771 96.642 88.925 ;
     RECT  50.724 88.889 53.694 89.231 ;
     RECT  50.76 89.231 53.694 89.303 ;
     RECT  146.052 88.253 146.214 89.311 ;
     RECT  51.015 89.303 53.01 89.339 ;
     RECT  52.992 89.339 53.01 89.357 ;
     RECT  54.432 88.889 89.097 89.429 ;
     RECT  51.015 89.339 52.074 89.501 ;
     RECT  49.212 88.619 49.59 89.545 ;
     RECT  145.836 89.311 146.214 89.771 ;
     RECT  4.176 88.799 47.79 89.803 ;
     RECT  4.176 89.803 47.826 89.815 ;
     RECT  48.564 89.545 49.59 89.815 ;
     RECT  2.415 88.079 3.366 89.977 ;
     RECT  4.176 89.815 49.59 89.977 ;
     RECT  54.468 89.429 89.097 90.121 ;
     RECT  54.468 90.121 89.19 90.419 ;
     RECT  54.468 90.419 89.097 90.661 ;
     RECT  2.415 89.977 49.59 90.923 ;
     RECT  48.528 90.923 49.59 90.931 ;
     RECT  54.396 90.661 89.097 91.049 ;
     RECT  146.196 89.771 146.214 91.049 ;
     RECT  54.504 91.049 89.097 91.085 ;
     RECT  48.528 90.931 49.698 91.165 ;
     RECT  145.188 91.165 145.35 91.229 ;
     RECT  142.815 85.757 143.334 91.319 ;
     RECT  145.332 91.229 145.35 91.319 ;
     RECT  147.384 91.195 147.402 91.319 ;
     RECT  142.815 91.319 143.097 91.327 ;
     RECT  142.38 91.327 143.097 91.373 ;
     RECT  146.448 91.195 146.466 91.471 ;
     RECT  146.448 91.471 146.61 91.517 ;
     RECT  48.528 91.165 49.842 91.561 ;
     RECT  146.592 91.517 146.61 91.589 ;
     RECT  144.324 91.471 144.342 91.733 ;
     RECT  48.528 91.561 49.95 91.831 ;
     RECT  54.54 91.085 89.097 91.859 ;
     RECT  142.488 91.373 143.097 91.859 ;
     RECT  2.415 90.923 47.754 91.939 ;
     RECT  48.528 91.831 50.022 91.939 ;
     RECT  2.415 91.939 50.238 91.975 ;
     RECT  51.015 89.501 51.297 91.975 ;
     RECT  2.415 91.975 51.297 92.551 ;
     RECT  52.056 89.501 52.074 92.551 ;
     RECT  54.684 91.859 89.097 92.677 ;
     RECT  54.504 92.677 89.097 92.785 ;
     RECT  148.215 79.709 148.497 93.499 ;
     RECT  54.396 92.785 89.097 93.595 ;
     RECT  110.415 86.237 110.697 93.991 ;
     RECT  112.788 93.499 112.806 94.019 ;
     RECT  148.215 93.499 148.77 94.019 ;
     RECT  147.348 93.499 147.366 94.055 ;
     RECT  110.415 93.991 111.294 94.061 ;
     RECT  2.415 92.551 52.074 94.099 ;
     RECT  52.812 93.901 52.83 94.099 ;
     RECT  2.415 94.099 52.83 94.289 ;
     RECT  146.484 93.991 146.502 94.289 ;
     RECT  54.144 93.595 89.097 94.651 ;
     RECT  53.856 94.651 89.097 94.711 ;
     RECT  53.856 94.711 89.658 94.973 ;
     RECT  52.992 94.699 53.01 95.107 ;
     RECT  2.415 94.289 52.11 95.179 ;
     RECT  52.848 95.107 53.01 95.179 ;
     RECT  53.856 94.973 89.097 95.179 ;
     RECT  133.344 83.755 133.362 95.369 ;
     RECT  2.415 95.179 89.097 95.405 ;
     RECT  48.672 95.405 89.097 95.719 ;
     RECT  2.415 95.405 47.79 95.819 ;
     RECT  48.672 95.719 89.334 96.017 ;
     RECT  48.672 96.017 54.126 96.179 ;
     RECT  54.864 96.017 89.334 96.179 ;
     RECT  47.772 95.819 47.79 96.259 ;
     RECT  48.672 96.179 53.586 96.259 ;
     RECT  0.144 96.187 0.162 96.295 ;
     RECT  47.772 96.259 53.586 96.323 ;
     RECT  2.415 95.819 46.926 96.715 ;
     RECT  47.772 96.323 53.478 96.715 ;
     RECT  2.415 96.715 53.478 96.755 ;
     RECT  2.415 96.755 46.998 97.387 ;
     RECT  0.108 96.295 0.162 97.483 ;
     RECT  2.304 97.387 46.998 97.531 ;
     RECT  47.772 96.755 53.478 97.531 ;
     RECT  2.304 97.531 53.478 97.537 ;
     RECT  2.304 97.537 54.09 97.573 ;
     RECT  54.864 96.179 89.097 97.573 ;
     RECT  0.108 97.483 0.342 97.613 ;
     RECT  2.304 97.573 89.097 97.835 ;
     RECT  0.108 97.613 0.126 97.853 ;
     RECT  2.34 97.835 3.618 98.339 ;
     RECT  2.34 98.339 3.294 98.375 ;
     RECT  4.428 97.835 89.097 98.491 ;
     RECT  2.415 98.375 3.006 98.519 ;
     RECT  4.428 98.491 89.514 98.609 ;
     RECT  4.428 98.609 89.097 98.669 ;
     RECT  4.428 98.669 55.422 99.185 ;
     RECT  56.415 98.669 89.097 99.697 ;
     RECT  4.716 99.185 55.422 99.805 ;
     RECT  56.196 99.697 89.097 99.805 ;
     RECT  4.716 99.805 89.097 99.959 ;
     RECT  4.716 99.959 55.278 100.103 ;
     RECT  4.716 100.103 54.846 100.679 ;
     RECT  4.716 100.679 48.15 100.841 ;
     RECT  48.924 100.679 54.846 100.849 ;
     RECT  56.415 99.959 89.097 100.877 ;
     RECT  48.924 100.849 55.17 101.039 ;
     RECT  48.996 101.039 55.17 101.075 ;
     RECT  49.104 101.075 55.17 101.191 ;
     RECT  49.104 101.191 55.53 101.309 ;
     RECT  49.104 101.309 55.17 101.345 ;
     RECT  86.832 100.877 89.097 101.489 ;
     RECT  86.832 101.489 87.174 101.579 ;
     RECT  87.984 101.489 89.097 101.579 ;
     RECT  56.415 100.877 86.058 101.623 ;
     RECT  86.832 101.579 86.922 101.623 ;
     RECT  56.415 101.623 86.922 101.849 ;
     RECT  4.752 100.841 48.15 101.965 ;
     RECT  4.752 101.965 48.366 102.001 ;
     RECT  49.104 101.345 54.846 102.001 ;
     RECT  4.752 102.001 54.846 102.127 ;
     RECT  4.752 102.127 55.278 102.509 ;
     RECT  48.96 102.509 55.278 102.541 ;
     RECT  48.96 102.541 55.458 102.659 ;
     RECT  88.2 101.579 89.097 102.659 ;
     RECT  4.752 102.509 48.222 102.695 ;
     RECT  4.752 102.695 48.186 102.767 ;
     RECT  56.415 101.849 86.634 102.775 ;
     RECT  48.96 102.659 55.278 102.803 ;
     RECT  56.415 102.775 86.814 102.811 ;
     RECT  56.415 102.811 87.354 102.907 ;
     RECT  4.896 102.767 48.186 102.929 ;
     RECT  48.96 102.803 54.882 102.929 ;
     RECT  48.96 102.929 54.846 102.965 ;
     RECT  48.96 102.965 53.622 102.989 ;
     RECT  54.468 102.965 54.846 102.989 ;
     RECT  54.828 102.989 54.846 103.001 ;
     RECT  5.076 102.929 48.186 103.037 ;
     RECT  56.376 102.907 87.354 103.199 ;
     RECT  5.148 103.037 48.186 103.513 ;
     RECT  48.96 102.989 53.298 103.513 ;
     RECT  56.415 103.199 86.634 103.577 ;
     RECT  5.148 103.513 53.298 103.711 ;
     RECT  56.415 103.577 86.526 103.739 ;
     RECT  56.415 103.739 86.418 103.757 ;
     RECT  57.42 103.757 86.418 103.775 ;
     RECT  5.148 103.711 53.334 103.855 ;
     RECT  5.148 103.855 53.514 103.919 ;
     RECT  58.176 103.775 86.418 104.117 ;
     RECT  58.176 104.117 86.022 104.279 ;
     RECT  5.328 103.919 53.514 104.315 ;
     RECT  5.364 104.315 53.514 104.431 ;
     RECT  59.544 104.279 86.022 104.549 ;
     RECT  58.176 104.279 58.77 104.585 ;
     RECT  59.544 104.549 85.842 104.585 ;
     RECT  59.544 104.585 85.734 104.621 ;
     RECT  58.176 104.585 58.302 104.657 ;
     RECT  59.544 104.621 85.554 104.819 ;
     RECT  5.364 104.431 53.766 105.061 ;
     RECT  59.544 104.819 84.366 105.089 ;
     RECT  81.144 105.089 83.697 105.125 ;
     RECT  81.36 105.125 83.697 105.233 ;
     RECT  58.176 104.657 58.194 105.269 ;
     RECT  5.364 105.061 54.09 105.359 ;
     RECT  82.188 105.233 83.697 105.359 ;
     RECT  81.36 105.233 81.378 105.437 ;
     RECT  82.26 105.359 82.458 105.437 ;
     RECT  83.376 105.359 83.697 105.437 ;
     RECT  53.748 105.359 53.766 105.503 ;
     RECT  5.364 105.359 53.01 105.629 ;
     RECT  57.42 103.775 57.438 105.629 ;
     RECT  82.26 105.437 82.35 105.629 ;
     RECT  82.26 105.629 82.278 105.665 ;
     RECT  59.544 105.089 80.406 105.883 ;
     RECT  5.364 105.629 52.83 105.899 ;
     RECT  59.436 105.883 80.406 105.899 ;
     RECT  59.436 105.899 59.454 105.935 ;
     RECT  60.516 105.899 80.406 106.079 ;
     RECT  60.552 106.079 80.406 106.205 ;
     RECT  5.364 105.899 52.47 106.241 ;
     RECT  60.588 106.205 80.406 106.439 ;
     RECT  61.38 106.439 80.406 106.483 ;
     RECT  61.38 106.483 80.442 106.519 ;
     RECT  61.38 106.519 80.91 106.583 ;
     RECT  5.364 106.241 52.434 106.781 ;
     RECT  61.74 106.583 80.91 106.853 ;
     RECT  5.364 106.781 51.966 106.889 ;
     RECT  61.74 106.853 80.658 107.051 ;
     RECT  5.364 106.889 51.822 107.249 ;
     RECT  61.74 107.051 80.37 107.591 ;
     RECT  61.74 107.591 80.19 107.699 ;
     RECT  5.364 107.249 51.714 107.789 ;
     RECT  61.74 107.699 79.794 107.789 ;
     RECT  61.74 107.789 62.298 107.797 ;
     RECT  61.704 107.797 62.298 107.837 ;
     RECT  63.18 107.789 79.47 107.837 ;
     RECT  61.815 107.837 62.298 107.897 ;
     RECT  49.716 107.789 51.714 108.059 ;
     RECT  63.18 107.837 79.362 108.317 ;
     RECT  63.18 108.317 63.846 108.329 ;
     RECT  63.396 108.329 63.846 108.365 ;
     RECT  63.504 108.365 63.846 108.473 ;
     RECT  64.692 108.317 79.362 108.599 ;
     RECT  64.692 108.599 65.322 108.635 ;
     RECT  63.828 108.473 63.846 108.707 ;
     RECT  64.728 108.635 65.322 108.707 ;
     RECT  64.98 108.707 65.322 108.779 ;
     RECT  5.364 107.789 48.798 108.841 ;
     RECT  49.716 108.059 51.297 108.841 ;
     RECT  65.088 108.779 65.322 108.869 ;
     RECT  66.06 108.599 79.362 108.869 ;
     RECT  76.824 108.869 78.297 108.893 ;
     RECT  66.204 108.869 76.05 109.013 ;
     RECT  5.364 108.841 51.297 109.139 ;
     RECT  67.104 109.013 76.05 109.139 ;
     RECT  66.204 109.013 66.222 109.175 ;
     RECT  5.364 109.139 49.986 109.283 ;
     RECT  67.104 109.139 75.978 109.283 ;
     RECT  67.215 109.283 75.978 109.319 ;
     RECT  5.4 109.283 49.986 109.409 ;
     RECT  68.652 109.319 75.978 109.409 ;
     RECT  76.824 108.893 76.986 109.409 ;
     RECT  77.76 108.893 78.297 109.409 ;
     RECT  68.724 109.409 69.138 109.421 ;
     RECT  5.4 109.409 49.95 109.445 ;
     RECT  68.724 109.421 68.922 109.445 ;
     RECT  76.824 109.409 76.842 109.445 ;
     RECT  68.904 109.445 68.922 109.481 ;
     RECT  70.308 109.409 75.978 109.679 ;
     RECT  70.308 109.679 74.574 109.709 ;
     RECT  75.312 109.679 75.978 109.715 ;
     RECT  75.384 109.715 75.978 109.787 ;
     RECT  70.308 109.709 73.134 109.949 ;
     RECT  73.944 109.709 74.574 109.949 ;
     RECT  75.384 109.787 75.726 109.949 ;
     RECT  70.308 109.949 71.406 109.955 ;
     RECT  72.216 109.949 72.99 109.985 ;
     RECT  74.124 109.949 74.286 109.985 ;
     RECT  75.564 109.949 75.726 109.985 ;
     RECT  74.124 109.985 74.142 110.021 ;
     RECT  75.708 109.985 75.726 110.021 ;
     RECT  53.424 110.011 53.442 110.155 ;
     RECT  53.424 110.155 54.126 110.219 ;
     RECT  70.308 109.955 71.118 110.219 ;
     RECT  72.216 109.985 72.897 110.219 ;
     RECT  70.38 110.219 70.794 110.489 ;
     RECT  70.776 110.489 70.794 110.525 ;
     RECT  54.108 110.219 54.126 110.669 ;
     RECT  5.58 109.445 49.95 110.909 ;
     RECT  5.58 110.909 48.69 111.209 ;
     RECT  5.58 111.209 5.598 112.765 ;
     RECT  6.336 111.209 48.69 112.765 ;
     RECT  5.58 112.765 48.69 112.877 ;
     RECT  6.516 112.877 48.69 113.071 ;
     RECT  6.516 113.071 48.834 113.333 ;
     RECT  5.58 112.877 5.598 113.639 ;
     RECT  6.516 113.333 48.762 113.999 ;
     RECT  49.932 110.909 49.95 113.999 ;
     RECT  6.84 113.999 48.762 114.035 ;
     RECT  6.84 114.035 48.69 114.557 ;
     RECT  16.452 114.557 48.69 114.605 ;
     RECT  6.84 114.557 15.714 114.961 ;
     RECT  16.524 114.605 48.69 115.079 ;
     RECT  6.732 114.961 15.714 115.133 ;
     RECT  6.84 115.133 15.714 115.357 ;
     RECT  16.524 115.079 48.114 115.357 ;
     RECT  6.84 115.357 48.114 115.889 ;
     RECT  6.84 115.889 6.858 116.045 ;
     RECT  7.596 115.889 48.114 116.429 ;
     RECT  7.776 116.429 48.114 116.465 ;
     RECT  7.776 116.465 48.042 116.609 ;
     RECT  7.815 116.609 48.042 117.005 ;
     RECT  8.928 117.005 47.862 117.509 ;
     RECT  8.928 117.509 47.358 117.779 ;
     RECT  8.928 117.779 47.286 117.815 ;
     RECT  8.928 117.815 46.782 117.851 ;
     RECT  10.764 117.851 46.782 117.959 ;
     RECT  7.815 117.005 8.097 118.165 ;
     RECT  8.928 117.851 9.99 118.165 ;
     RECT  7.815 118.165 9.99 118.193 ;
     RECT  7.815 118.193 8.802 118.205 ;
     RECT  9.54 118.193 9.99 118.741 ;
     RECT  10.764 117.959 28.314 118.741 ;
     RECT  29.088 117.959 46.782 118.859 ;
     RECT  9.54 118.741 28.314 118.867 ;
     RECT  29.088 118.859 46.638 118.867 ;
     RECT  9.54 118.867 46.638 118.895 ;
     RECT  9.54 118.895 46.278 118.967 ;
     RECT  9.54 118.967 45.897 119.039 ;
     RECT  9.684 119.039 45.897 119.129 ;
     RECT  9.9 119.129 44.802 119.165 ;
     RECT  10.008 119.165 14.886 119.273 ;
     RECT  15.804 119.165 44.802 119.273 ;
     RECT  15.804 119.273 44.55 119.309 ;
     RECT  10.548 119.273 14.886 119.399 ;
     RECT  10.548 119.399 14.67 119.435 ;
     RECT  10.548 119.435 14.49 119.471 ;
     RECT  12.78 119.471 14.49 119.507 ;
     RECT  12.78 119.507 14.418 119.549 ;
     RECT  10.548 119.471 12.042 119.669 ;
     RECT  12.78 119.549 13.497 119.669 ;
     RECT  13.14 119.669 13.497 119.705 ;
     RECT  14.4 119.549 14.418 119.741 ;
     RECT  11.196 119.669 11.718 119.813 ;
     RECT  15.804 119.309 32.238 120.091 ;
     RECT  32.976 119.309 44.55 120.091 ;
     RECT  11.412 119.813 11.718 120.119 ;
     RECT  15.804 120.091 44.55 120.209 ;
     RECT  15.804 120.209 15.822 120.245 ;
     RECT  16.776 120.209 44.55 120.281 ;
     RECT  11.412 120.119 11.43 120.479 ;
     RECT  17.1 120.281 44.55 120.479 ;
     RECT  17.1 120.479 21.762 120.515 ;
     RECT  17.1 120.515 21.546 120.551 ;
     RECT  22.572 120.479 44.55 120.623 ;
     RECT  17.388 120.551 21.546 120.659 ;
     RECT  17.388 120.659 17.694 120.749 ;
     RECT  22.572 120.623 39.258 120.749 ;
     RECT  40.215 120.623 44.55 120.749 ;
     RECT  20.124 120.659 21.546 120.797 ;
     RECT  22.572 120.749 22.662 120.797 ;
     RECT  40.215 120.749 43.83 120.797 ;
     RECT  18.576 120.659 19.026 120.821 ;
     RECT  40.215 120.797 40.878 120.821 ;
     RECT  41.688 120.797 43.83 120.821 ;
     RECT  20.196 120.797 21.546 120.929 ;
     RECT  17.388 120.749 17.406 121.019 ;
     RECT  20.736 120.929 21.546 121.019 ;
     RECT  42.048 120.821 43.83 121.019 ;
     RECT  18.576 120.821 18.897 121.163 ;
     RECT  23.544 120.749 39.258 121.199 ;
     RECT  23.544 121.199 34.074 121.289 ;
     RECT  34.815 121.199 39.258 121.289 ;
     RECT  42.444 121.019 43.83 121.289 ;
     RECT  23.544 121.289 27.27 121.325 ;
     RECT  28.188 121.289 28.206 121.325 ;
     RECT  29.34 121.289 31.482 121.325 ;
     RECT  34.815 121.289 35.694 121.325 ;
     RECT  43.524 121.289 43.83 121.325 ;
     RECT  29.415 121.325 30.978 121.361 ;
     RECT  24.015 121.325 27.27 121.397 ;
     RECT  36.504 121.289 39.258 121.397 ;
     RECT  43.524 121.325 43.542 121.397 ;
     RECT  24.015 121.397 27.09 121.559 ;
     RECT  32.292 121.289 33.318 121.559 ;
     RECT  36.504 121.397 39.15 121.559 ;
     RECT  25.092 121.559 25.866 121.595 ;
     RECT  36.612 121.559 38.718 121.595 ;
     RECT  29.415 121.361 30.402 121.631 ;
     RECT  34.056 121.289 34.074 121.703 ;
     RECT  37.296 121.595 38.718 121.829 ;
     RECT  37.296 121.829 37.314 121.973 ;
     RECT  25.092 121.595 25.614 122.099 ;
     RECT  38.268 121.829 38.718 122.099 ;
     RECT  38.268 122.099 38.286 122.135 ;
     RECT  25.596 122.099 25.614 122.171 ;
     RECT  36.54 123.691 36.846 123.989 ;
     RECT  36.828 123.989 36.846 124.259 ;
     RECT  2.415 98.519 2.697 127.187 ;
     RECT  7.815 118.205 8.097 127.187 ;
     RECT  13.215 119.705 13.497 127.187 ;
     RECT  18.615 121.163 18.897 127.187 ;
     RECT  24.015 121.559 24.297 127.187 ;
     RECT  29.415 121.631 29.697 127.187 ;
     RECT  34.815 121.325 35.097 127.187 ;
     RECT  40.215 120.821 40.497 127.187 ;
     RECT  45.615 119.129 45.897 127.187 ;
     RECT  51.015 109.139 51.297 127.187 ;
     RECT  56.415 103.757 56.697 127.187 ;
     RECT  61.815 107.897 62.097 127.187 ;
     RECT  67.215 109.319 67.497 127.187 ;
     RECT  72.615 110.219 72.897 127.187 ;
     RECT  78.015 109.409 78.297 127.187 ;
     RECT  83.415 105.437 83.697 127.187 ;
     RECT  88.815 102.659 89.097 127.187 ;
     RECT  94.215 88.619 94.497 127.187 ;
     RECT  99.615 75.293 99.897 127.187 ;
     RECT  105.015 75.293 105.297 127.187 ;
     RECT  110.415 94.061 110.697 127.187 ;
     RECT  115.815 75.293 116.097 127.187 ;
     RECT  121.215 80.528 121.497 127.187 ;
     RECT  126.615 75.485 126.897 127.187 ;
     RECT  132.015 85.661 132.297 127.187 ;
     RECT  137.415 75.313 137.697 127.187 ;
     RECT  142.815 91.859 143.097 127.187 ;
     RECT  148.215 94.019 148.497 127.187 ;
     RECT  153.615 75.313 153.897 127.187 ;
     RECT  159.015 75.313 159.297 127.187 ;
     RECT  164.415 75.313 164.697 127.187 ;
     RECT  169.815 75.313 170.097 127.187 ;
     RECT  175.215 75.313 175.497 127.187 ;
     RECT  180.615 75.313 180.897 127.187 ;
     RECT  186.015 75.313 186.297 127.187 ;
     RECT  191.415 75.313 191.697 127.187 ;
     RECT  196.815 75.313 197.097 127.187 ;
     RECT  202.215 75.313 202.497 127.187 ;
     RECT  207.615 75.313 207.897 127.187 ;
     RECT  213.015 75.313 213.297 127.187 ;
     RECT  218.415 75.313 218.697 127.187 ;
     RECT  223.815 2.413 224.097 127.187 ;
     RECT  229.215 2.413 229.497 127.187 ;
     RECT  234.615 2.413 234.897 127.187 ;
     RECT  240.015 2.413 240.297 127.187 ;
     RECT  245.415 46.103 245.697 127.187 ;
     RECT  250.815 79.181 251.097 127.187 ;
     RECT  256.215 48.929 256.497 127.187 ;
     RECT  2.415 127.187 2.505 127.457 ;
     RECT  7.815 127.187 7.905 127.457 ;
     RECT  13.215 127.187 13.305 127.457 ;
     RECT  18.615 127.187 18.705 127.457 ;
     RECT  24.015 127.187 24.105 127.457 ;
     RECT  29.415 127.187 29.505 127.457 ;
     RECT  34.815 127.187 34.905 127.457 ;
     RECT  40.215 127.187 40.305 127.457 ;
     RECT  45.615 127.187 45.705 127.457 ;
     RECT  51.015 127.187 51.105 127.457 ;
     RECT  56.415 127.187 56.505 127.457 ;
     RECT  61.815 127.187 61.905 127.457 ;
     RECT  67.215 127.187 67.305 127.457 ;
     RECT  72.615 127.187 72.705 127.457 ;
     RECT  78.015 127.187 78.105 127.457 ;
     RECT  83.415 127.187 83.505 127.457 ;
     RECT  88.815 127.187 88.905 127.457 ;
     RECT  94.215 127.187 94.305 127.457 ;
     RECT  99.615 127.187 99.705 127.457 ;
     RECT  105.015 127.187 105.105 127.457 ;
     RECT  110.415 127.187 110.505 127.457 ;
     RECT  115.815 127.187 115.905 127.457 ;
     RECT  121.215 127.187 121.305 127.457 ;
     RECT  126.615 127.187 126.705 127.457 ;
     RECT  132.015 127.187 132.105 127.457 ;
     RECT  137.415 127.187 137.505 127.457 ;
     RECT  142.815 127.187 142.905 127.457 ;
     RECT  148.215 127.187 148.305 127.457 ;
     RECT  153.615 127.187 153.705 127.457 ;
     RECT  159.015 127.187 159.105 127.457 ;
     RECT  164.415 127.187 164.505 127.457 ;
     RECT  169.815 127.187 169.905 127.457 ;
     RECT  175.215 127.187 175.305 127.457 ;
     RECT  180.615 127.187 180.705 127.457 ;
     RECT  186.015 127.187 186.105 127.457 ;
     RECT  191.415 127.187 191.505 127.457 ;
     RECT  196.815 127.187 196.905 127.457 ;
     RECT  202.215 127.187 202.305 127.457 ;
     RECT  207.615 127.187 207.705 127.457 ;
     RECT  213.015 127.187 213.105 127.457 ;
     RECT  218.415 127.187 218.505 127.457 ;
     RECT  223.815 127.187 223.905 127.457 ;
     RECT  229.215 127.187 229.305 127.457 ;
     RECT  234.615 127.187 234.705 127.457 ;
     RECT  240.015 127.187 240.105 127.457 ;
     RECT  245.415 127.187 245.505 127.457 ;
     RECT  250.815 127.187 250.905 127.457 ;
     RECT  256.215 127.187 256.305 127.457 ;
    LAYER M4 ;
     RECT  0.025 84.336 0.06 84.36 ;
     RECT  0.084 81.264 0.097 81.288 ;
     RECT  0.06 81.288 0.097 81.36 ;
     RECT  0.084 81.36 0.097 81.384 ;
     RECT  0.06 81.384 0.097 81.456 ;
     RECT  0.084 81.456 0.097 81.48 ;
     RECT  0.06 81.48 0.097 81.552 ;
     RECT  0.084 81.552 0.097 81.576 ;
     RECT  0.06 81.576 0.097 81.648 ;
     RECT  0.084 81.648 0.097 81.672 ;
     RECT  0.06 81.672 0.097 81.744 ;
     RECT  0.084 81.744 0.097 81.768 ;
     RECT  0.06 81.768 0.097 81.84 ;
     RECT  0.084 81.84 0.097 81.864 ;
     RECT  0.06 81.864 0.097 81.936 ;
     RECT  0.084 81.936 0.097 81.96 ;
     RECT  0.06 81.96 0.097 82.032 ;
     RECT  0.084 82.032 0.097 82.056 ;
     RECT  0.06 82.056 0.097 82.128 ;
     RECT  0.084 82.128 0.097 82.152 ;
     RECT  0.06 82.152 0.097 82.224 ;
     RECT  0.084 82.224 0.097 82.248 ;
     RECT  0.06 82.248 0.097 82.32 ;
     RECT  0.084 82.32 0.097 82.344 ;
     RECT  0.06 82.344 0.097 82.416 ;
     RECT  0.084 82.416 0.097 82.44 ;
     RECT  0.06 82.44 0.097 82.512 ;
     RECT  0.084 82.512 0.097 82.536 ;
     RECT  0.06 82.536 0.097 82.608 ;
     RECT  0.084 82.608 0.097 82.632 ;
     RECT  0.06 82.632 0.097 82.704 ;
     RECT  0.084 82.704 0.097 82.728 ;
     RECT  0.06 82.728 0.097 82.8 ;
     RECT  0.084 82.8 0.097 82.824 ;
     RECT  0.06 82.824 0.097 82.896 ;
     RECT  0.084 82.896 0.097 82.92 ;
     RECT  0.06 82.92 0.097 82.992 ;
     RECT  0.084 82.992 0.097 83.016 ;
     RECT  0.06 83.016 0.097 83.088 ;
     RECT  0.084 83.088 0.097 83.112 ;
     RECT  0.06 83.112 0.097 83.184 ;
     RECT  0.084 83.184 0.097 83.208 ;
     RECT  0.06 83.208 0.097 83.28 ;
     RECT  0.084 83.28 0.097 83.304 ;
     RECT  0.06 83.304 0.097 83.376 ;
     RECT  0.084 83.376 0.097 83.4 ;
     RECT  0.06 83.4 0.097 83.472 ;
     RECT  0.084 83.472 0.097 83.496 ;
     RECT  0.06 83.496 0.097 83.568 ;
     RECT  0.084 83.568 0.097 83.592 ;
     RECT  0.06 83.592 0.097 83.664 ;
     RECT  0.084 83.664 0.097 83.688 ;
     RECT  0.06 83.688 0.097 83.76 ;
     RECT  0.084 83.76 0.097 83.784 ;
     RECT  0.06 83.784 0.097 83.856 ;
     RECT  0.084 83.856 0.097 83.88 ;
     RECT  0.06 83.88 0.097 83.952 ;
     RECT  0.084 83.952 0.097 83.976 ;
     RECT  0.06 83.976 0.097 84.048 ;
     RECT  0.084 84.048 0.097 84.072 ;
     RECT  0.06 84.072 0.097 84.144 ;
     RECT  0.084 84.144 0.097 84.168 ;
     RECT  0.06 84.168 0.097 84.24 ;
     RECT  0.084 84.24 0.097 84.264 ;
     RECT  0.06 84.264 0.097 84.36 ;
     RECT  0.084 97.2 0.097 97.224 ;
     RECT  0.06 97.224 0.097 97.296 ;
     RECT  0.084 97.296 0.097 97.32 ;
     RECT  0.06 97.32 0.097 97.392 ;
     RECT  0.084 97.392 0.097 97.416 ;
     RECT  0.06 97.416 0.097 97.488 ;
     RECT  0.084 97.488 0.097 97.512 ;
     RECT  0.06 97.512 0.097 97.584 ;
     RECT  0.084 97.584 0.097 97.608 ;
     RECT  0.084 54.864 0.137 54.888 ;
     RECT  0.06 54.888 0.137 54.96 ;
     RECT  0.084 54.96 0.137 54.984 ;
     RECT  0.06 54.984 0.137 55.056 ;
     RECT  0.084 55.056 0.137 55.08 ;
     RECT  0.06 55.08 0.137 55.152 ;
     RECT  0.084 55.152 0.137 55.176 ;
     RECT  0.06 55.176 0.137 55.248 ;
     RECT  0.084 55.248 0.137 55.272 ;
     RECT  0.06 55.272 0.137 55.344 ;
     RECT  0.084 55.344 0.137 55.368 ;
     RECT  0.06 55.368 0.137 55.44 ;
     RECT  0.084 55.44 0.137 55.464 ;
     RECT  0.06 55.464 0.137 55.536 ;
     RECT  0.084 55.536 0.137 55.56 ;
     RECT  0.06 55.56 0.137 55.632 ;
     RECT  0.084 55.632 0.137 55.656 ;
     RECT  0.06 55.656 0.137 55.728 ;
     RECT  0.084 55.728 0.137 55.752 ;
     RECT  0.06 55.752 0.137 55.824 ;
     RECT  0.084 55.824 0.137 55.848 ;
     RECT  0.097 97.2 0.137 97.848 ;
     RECT  0.137 97.296 0.173 97.848 ;
     RECT  0.137 54.912 0.317 55.848 ;
     RECT  0.097 81.168 2.365 84.36 ;
     RECT  0.317 54.912 2.408 55.704 ;
     RECT  0.084 58.992 2.408 59.016 ;
     RECT  0.06 59.016 2.408 59.088 ;
     RECT  0.084 59.088 2.408 59.112 ;
     RECT  0.06 59.112 2.408 59.184 ;
     RECT  0.084 59.184 2.408 59.208 ;
     RECT  0.06 59.208 2.408 59.28 ;
     RECT  0.084 59.28 2.408 59.304 ;
     RECT  0.06 59.304 2.408 59.376 ;
     RECT  0.084 59.376 2.408 59.4 ;
     RECT  0.06 59.4 2.408 59.472 ;
     RECT  0.084 59.472 2.408 59.496 ;
     RECT  0.06 59.496 2.408 59.568 ;
     RECT  0.084 59.568 2.408 59.592 ;
     RECT  0.06 59.592 2.408 59.664 ;
     RECT  0.084 59.664 2.408 59.688 ;
     RECT  0.06 59.688 2.408 59.76 ;
     RECT  0.084 59.76 2.408 59.784 ;
     RECT  0.06 59.784 2.408 59.856 ;
     RECT  0.084 59.856 2.408 59.88 ;
     RECT  0.06 59.88 2.408 59.952 ;
     RECT  0.084 59.952 2.408 59.976 ;
     RECT  2.365 81.168 2.408 84.6 ;
     RECT  0.173 97.392 2.408 97.848 ;
     RECT  2.408 2.148 2.512 127.452 ;
     RECT  2.512 2.418 2.704 127.182 ;
     RECT  2.704 81.168 2.909 85.512 ;
     RECT  2.909 81.504 3.629 85.512 ;
     RECT  2.704 86.928 3.769 87.768 ;
     RECT  3.629 84.144 3.913 85.512 ;
     RECT  3.769 86.64 3.913 87.768 ;
     RECT  3.629 81.504 4.097 83.112 ;
     RECT  2.704 58.992 4.201 60.312 ;
     RECT  3.913 84.144 4.345 87.768 ;
     RECT  2.704 97.584 4.381 97.656 ;
     RECT  2.704 80.112 4.417 80.136 ;
     RECT  4.097 81.504 4.417 83.016 ;
     RECT  4.417 80.112 4.421 83.016 ;
     RECT  4.345 64.848 4.525 64.872 ;
     RECT  4.381 97.104 4.633 97.656 ;
     RECT  4.453 90.528 4.669 90.552 ;
     RECT  4.093 91.776 4.669 91.8 ;
     RECT  4.669 90.528 4.741 91.8 ;
     RECT  4.345 84.144 4.813 88.728 ;
     RECT  4.525 95.088 5.029 95.112 ;
     RECT  4.813 84.144 5.033 88.92 ;
     RECT  4.885 98.688 5.033 98.712 ;
     RECT  4.993 102.768 5.065 102.792 ;
     RECT  5.029 95.088 5.101 95.16 ;
     RECT  5.125 57.024 5.249 57.048 ;
     RECT  4.201 58.656 5.249 60.312 ;
     RECT  4.633 96.864 5.281 97.656 ;
     RECT  5.101 95.04 5.317 95.16 ;
     RECT  4.741 89.952 5.321 91.8 ;
     RECT  2.704 54.912 5.357 55.848 ;
     RECT  5.281 96.672 5.389 97.656 ;
     RECT  4.309 93.36 5.429 93.384 ;
     RECT  5.317 94.608 5.429 95.16 ;
     RECT  5.065 102.768 5.465 102.84 ;
     RECT  4.421 80.112 5.533 81.528 ;
     RECT  4.421 82.56 5.533 83.016 ;
     RECT  5.321 91.776 5.533 91.8 ;
     RECT  5.357 55.392 5.573 55.848 ;
     RECT  5.033 84.144 5.573 88.728 ;
     RECT  5.533 80.112 5.605 83.016 ;
     RECT  5.321 89.952 5.681 90.552 ;
     RECT  4.525 64.8 5.939 64.872 ;
     RECT  5.317 57.552 5.987 57.576 ;
     RECT  5.821 107.52 6.073 107.544 ;
     RECT  6.073 106.992 6.181 107.544 ;
     RECT  5.429 94.608 6.188 95.112 ;
     RECT  5.249 58.992 6.257 60.312 ;
     RECT  5.681 90.048 6.325 90.552 ;
     RECT  5.533 91.776 6.325 92.328 ;
     RECT  5.389 108.864 6.329 108.888 ;
     RECT  6.325 90.048 6.517 92.328 ;
     RECT  5.389 96.672 6.581 98.232 ;
     RECT  5.101 101.04 6.613 101.064 ;
     RECT  5.573 84.912 6.649 88.728 ;
     RECT  6.181 106.992 6.649 107.832 ;
     RECT  5.465 102.816 6.653 102.84 ;
     RECT  6.257 59.712 6.761 60.312 ;
     RECT  6.649 106.608 6.761 107.832 ;
     RECT  5.605 80.112 6.793 83.496 ;
     RECT  6.649 84.864 6.793 88.728 ;
     RECT  6.793 80.112 6.797 88.728 ;
     RECT  6.721 115.104 6.829 115.128 ;
     RECT  6.181 112.848 6.853 112.872 ;
     RECT  6.581 96.864 6.937 98.232 ;
     RECT  6.188 93.936 6.973 95.112 ;
     RECT  6.973 93.936 7.009 95.16 ;
     RECT  7.009 93.312 7.045 95.16 ;
     RECT  6.797 84.144 7.117 88.728 ;
     RECT  7.045 102.384 7.189 102.408 ;
     RECT  6.853 112.272 7.189 112.872 ;
     RECT  7.045 93.312 7.225 95.544 ;
     RECT  5.713 104.304 7.297 104.328 ;
     RECT  6.517 90.096 7.369 92.328 ;
     RECT  7.225 93.312 7.369 95.88 ;
     RECT  6.613 100.992 7.513 101.064 ;
     RECT  7.369 90.096 7.585 95.88 ;
     RECT  6.937 96.864 7.585 98.616 ;
     RECT  7.513 100.896 7.621 101.064 ;
     RECT  7.621 100.08 7.657 101.064 ;
     RECT  7.189 102.24 7.657 102.408 ;
     RECT  6.761 106.992 7.657 107.832 ;
     RECT  6.797 80.112 7.765 83.016 ;
     RECT  7.117 84.144 7.765 88.92 ;
     RECT  5.573 55.392 7.808 55.56 ;
     RECT  6.761 60 7.808 60.312 ;
     RECT  5.939 64.848 7.808 64.872 ;
     RECT  7.765 80.112 7.808 88.92 ;
     RECT  7.585 90.096 7.808 98.616 ;
     RECT  7.657 100.08 7.808 102.408 ;
     RECT  7.297 103.776 7.808 104.328 ;
     RECT  7.153 105.456 7.808 105.48 ;
     RECT  7.657 106.992 7.808 108.216 ;
     RECT  5.965 110.592 7.808 110.616 ;
     RECT  7.189 111.648 7.808 112.872 ;
     RECT  6.829 115.104 7.808 116.04 ;
     RECT  6.853 118.176 7.808 118.2 ;
     RECT  7.808 2.148 7.912 127.452 ;
     RECT  7.912 2.418 8.104 127.182 ;
     RECT  8.104 93.168 8.309 95.4 ;
     RECT  8.104 90.096 8.417 92.184 ;
     RECT  8.417 90.096 8.633 91.992 ;
     RECT  8.104 107.52 8.705 108.312 ;
     RECT  8.104 60 8.741 60.312 ;
     RECT  8.104 116.16 8.777 118.2 ;
     RECT  8.741 60.288 8.813 60.312 ;
     RECT  8.777 116.832 8.957 118.2 ;
     RECT  8.104 112.656 9.173 112.872 ;
     RECT  8.104 105.264 9.277 105.48 ;
     RECT  8.957 117.408 9.353 118.2 ;
     RECT  8.309 93.168 9.493 95.064 ;
     RECT  8.104 111.648 9.493 111.672 ;
     RECT  9.173 112.656 9.493 112.824 ;
     RECT  8.633 91.968 9.529 91.992 ;
     RECT  9.493 93.168 9.529 95.496 ;
     RECT  8.104 96.528 9.529 99.816 ;
     RECT  8.104 100.896 9.529 104.04 ;
     RECT  8.104 55.68 9.605 55.704 ;
     RECT  9.529 91.968 9.673 95.496 ;
     RECT  9.529 96.528 9.673 104.04 ;
     RECT  9.277 105.264 9.685 105.768 ;
     RECT  9.673 91.968 9.709 104.04 ;
     RECT  8.705 107.808 9.709 108.312 ;
     RECT  9.601 109.536 9.709 109.56 ;
     RECT  8.104 79.2 9.745 88.968 ;
     RECT  9.709 107.808 9.745 109.56 ;
     RECT  9.745 79.2 9.781 89.064 ;
     RECT  8.633 90.096 9.781 90.408 ;
     RECT  9.685 105.264 9.781 105.912 ;
     RECT  9.745 107.808 9.781 109.608 ;
     RECT  9.353 117.792 9.785 118.2 ;
     RECT  9.709 91.968 9.877 104.136 ;
     RECT  9.785 118.176 9.877 118.2 ;
     RECT  8.104 114.768 9.889 114.792 ;
     RECT  9.877 118.176 9.889 118.584 ;
     RECT  9.889 118.176 9.923 119.16 ;
     RECT  9.877 91.728 9.925 104.136 ;
     RECT  9.781 105.12 9.925 106.008 ;
     RECT  9.923 118.56 9.964 119.16 ;
     RECT  9.925 91.728 9.997 106.632 ;
     RECT  9.781 79.2 10.033 90.408 ;
     RECT  9.997 91.44 10.033 106.632 ;
     RECT  9.781 107.808 10.033 110.088 ;
     RECT  10.033 79.2 10.165 106.632 ;
     RECT  10.033 107.712 10.165 110.088 ;
     RECT  9.493 111.648 10.213 112.824 ;
     RECT  10.213 111.072 10.249 112.824 ;
     RECT  10.033 116.4 10.249 116.424 ;
     RECT  10.249 111.072 10.261 113.592 ;
     RECT  9.889 114.768 10.261 114.936 ;
     RECT  10.261 111.072 10.357 114.936 ;
     RECT  9.601 78.048 10.405 78.072 ;
     RECT  10.165 79.2 10.405 110.088 ;
     RECT  10.357 111.072 10.421 114.984 ;
     RECT  10.393 74.64 10.429 74.664 ;
     RECT  10.405 78.048 10.492 110.088 ;
     RECT  10.492 79.2 10.501 110.088 ;
     RECT  10.421 111.072 10.501 115.176 ;
     RECT  10.501 79.2 10.537 115.176 ;
     RECT  10.249 116.4 10.537 116.808 ;
     RECT  10.753 73.056 10.789 73.08 ;
     RECT  10.429 74.064 10.789 74.664 ;
     RECT  10.789 73.056 10.835 75.24 ;
     RECT  10.753 77.04 10.861 77.064 ;
     RECT  10.835 73.056 11.189 73.512 ;
     RECT  10.537 79.2 11.267 116.808 ;
     RECT  10.861 76.896 11.293 77.064 ;
     RECT  10.492 78.048 11.293 78.072 ;
     RECT  11.267 106.512 11.363 116.808 ;
     RECT  11.293 76.896 11.405 78.072 ;
     RECT  11.363 111.648 11.473 116.808 ;
     RECT  11.267 79.2 11.477 105.384 ;
     RECT  11.405 76.896 11.513 76.92 ;
     RECT  11.363 106.512 11.513 110.376 ;
     RECT  11.473 111.648 11.585 116.856 ;
     RECT  10.429 71.712 11.657 71.736 ;
     RECT  9.964 119.136 11.869 119.16 ;
     RECT  11.189 73.344 11.941 73.512 ;
     RECT  10.835 74.64 11.941 75.24 ;
     RECT  11.941 73.344 12.053 75.24 ;
     RECT  12.053 73.344 12.193 74.712 ;
     RECT  12.157 76.464 12.229 76.488 ;
     RECT  12.193 73.296 12.265 74.712 ;
     RECT  12.265 73.2 12.373 74.712 ;
     RECT  11.513 106.512 12.373 108.6 ;
     RECT  11.513 109.92 12.517 110.376 ;
     RECT  12.517 109.872 12.589 110.376 ;
     RECT  11.477 79.776 12.661 105.384 ;
     RECT  12.373 106.368 12.661 108.6 ;
     RECT  11.585 111.648 12.697 116.76 ;
     RECT  11.869 118.224 12.697 119.16 ;
     RECT  12.697 111.648 12.769 119.16 ;
     RECT  12.661 79.776 12.805 108.6 ;
     RECT  12.589 109.872 12.805 110.472 ;
     RECT  12.805 79.056 12.877 110.472 ;
     RECT  12.769 111.648 12.877 119.496 ;
     RECT  12.877 79.056 13.057 119.496 ;
     RECT  10.429 58.896 13.208 58.92 ;
     RECT  8.104 64.848 13.208 64.872 ;
     RECT  13.201 71.184 13.208 71.208 ;
     RECT  12.373 72.816 13.208 74.712 ;
     RECT  12.229 76.176 13.208 76.488 ;
     RECT  11.405 78.048 13.208 78.072 ;
     RECT  13.057 79.056 13.208 119.544 ;
     RECT  13.208 2.148 13.312 127.452 ;
     RECT  13.312 2.418 13.504 127.182 ;
     RECT  13.504 112.656 13.997 119.544 ;
     RECT  13.504 104.928 14.003 111.672 ;
     RECT  14.003 104.928 14.285 111.336 ;
     RECT  13.504 73.344 14.497 74.04 ;
     RECT  13.504 75.168 14.497 75.384 ;
     RECT  14.533 70.848 14.569 70.872 ;
     RECT  14.285 111.312 14.573 111.336 ;
     RECT  14.497 73.344 14.645 75.384 ;
     RECT  14.285 104.928 14.645 110.184 ;
     RECT  14.569 69.888 14.677 71.544 ;
     RECT  14.677 69.888 14.749 72.36 ;
     RECT  14.645 73.344 14.749 75.192 ;
     RECT  14.749 69.888 14.789 75.192 ;
     RECT  13.504 76.512 14.821 103.896 ;
     RECT  14.645 105.504 15.011 110.184 ;
     RECT  15.011 105.504 15.221 110.136 ;
     RECT  15.221 105.504 15.365 110.088 ;
     RECT  15.365 105.792 15.401 110.088 ;
     RECT  14.821 76.512 15.577 104.424 ;
     RECT  15.401 105.792 15.617 109.32 ;
     RECT  15.577 76.368 15.797 104.424 ;
     RECT  13.997 112.656 15.865 119.16 ;
     RECT  14.789 69.888 16.213 74.856 ;
     RECT  16.213 69.504 16.259 74.856 ;
     RECT  15.865 112.656 16.297 120.12 ;
     RECT  16.259 69.504 16.301 69.528 ;
     RECT  16.259 70.656 16.333 74.856 ;
     RECT  15.797 76.368 16.373 103.896 ;
     RECT  16.297 112.32 16.549 120.12 ;
     RECT  16.333 70.656 16.595 74.904 ;
     RECT  16.595 70.656 16.697 73.8 ;
     RECT  16.621 105.024 16.729 105.048 ;
     RECT  15.617 106.512 16.729 109.32 ;
     RECT  16.369 110.592 16.729 110.616 ;
     RECT  16.549 111.6 16.805 120.12 ;
     RECT  16.373 77.136 17.021 103.896 ;
     RECT  16.729 105.024 17.053 105.096 ;
     RECT  16.729 106.512 17.053 110.616 ;
     RECT  16.697 70.656 17.057 71.832 ;
     RECT  17.021 100.512 17.089 103.896 ;
     RECT  17.053 104.976 17.089 105.096 ;
     RECT  16.805 111.6 17.093 119.832 ;
     RECT  17.021 77.136 17.165 99.528 ;
     RECT  17.089 100.512 17.197 105.096 ;
     RECT  17.053 106.416 17.197 110.616 ;
     RECT  17.093 111.84 17.381 119.832 ;
     RECT  17.197 100.512 17.525 110.616 ;
     RECT  16.595 74.88 17.633 74.904 ;
     RECT  17.057 70.848 17.665 71.832 ;
     RECT  16.697 72.96 17.665 73.8 ;
     RECT  17.665 70.848 17.773 73.8 ;
     RECT  17.773 70.848 17.893 73.896 ;
     RECT  17.525 105.168 18.181 110.616 ;
     RECT  17.165 77.712 18.277 99.528 ;
     RECT  18.097 76.272 18.385 76.296 ;
     RECT  17.381 111.84 18.385 118.92 ;
     RECT  17.893 70.848 18.469 74.328 ;
     RECT  13.504 58.896 18.608 58.92 ;
     RECT  13.504 64.848 18.608 64.872 ;
     RECT  18.469 70.656 18.608 74.328 ;
     RECT  18.385 75.696 18.608 76.296 ;
     RECT  18.277 77.376 18.608 99.528 ;
     RECT  17.525 100.512 18.608 104.136 ;
     RECT  18.181 105.168 18.608 110.76 ;
     RECT  18.385 111.84 18.608 119.16 ;
     RECT  18.608 2.148 18.712 127.452 ;
     RECT  18.712 2.418 18.904 127.182 ;
     RECT  18.904 70.08 18.929 77.4 ;
     RECT  18.929 73.2 19.145 77.4 ;
     RECT  18.929 70.08 19.325 72.168 ;
     RECT  19.145 76.272 19.613 77.4 ;
     RECT  18.904 78.432 19.897 110.616 ;
     RECT  18.904 111.84 19.897 119.688 ;
     RECT  19.145 73.2 20.003 74.904 ;
     RECT  20.003 73.2 20.005 74.328 ;
     RECT  19.897 78.432 20.149 119.688 ;
     RECT  18.904 120.768 20.149 120.792 ;
     RECT  20.149 78.432 20.243 120.792 ;
     RECT  19.325 70.08 20.485 71.832 ;
     RECT  20.005 72.96 20.485 74.328 ;
     RECT  20.243 78.432 20.513 117.336 ;
     RECT  19.613 76.272 20.693 76.296 ;
     RECT  20.243 118.512 20.725 120.792 ;
     RECT  20.485 70.08 20.729 74.328 ;
     RECT  20.725 118.512 20.867 120.984 ;
     RECT  20.867 120.096 20.908 120.792 ;
     RECT  20.729 72.912 20.977 74.328 ;
     RECT  20.908 120.624 21.053 120.792 ;
     RECT  20.977 72.912 21.107 75.288 ;
     RECT  19.613 77.376 21.193 77.4 ;
     RECT  20.867 118.512 21.197 118.728 ;
     RECT  21.197 118.512 21.305 118.584 ;
     RECT  20.729 70.08 21.341 71.688 ;
     RECT  20.513 78.432 21.341 101.016 ;
     RECT  21.341 79.44 21.733 101.016 ;
     RECT  20.513 102.048 21.733 117.336 ;
     RECT  21.733 79.44 21.737 117.336 ;
     RECT  21.341 70.08 21.772 71.64 ;
     RECT  21.107 74.064 21.917 74.904 ;
     RECT  21.772 70.08 22.129 71.256 ;
     RECT  21.917 74.304 22.169 74.904 ;
     RECT  21.107 72.912 22.201 73.032 ;
     RECT  21.193 76.464 22.273 77.448 ;
     RECT  21.341 78.432 22.345 78.456 ;
     RECT  21.737 79.44 22.345 112.008 ;
     RECT  22.201 72.912 22.421 73.08 ;
     RECT  21.053 120.768 22.561 120.792 ;
     RECT  22.273 75.984 22.669 77.448 ;
     RECT  22.561 120.096 22.673 120.792 ;
     RECT  22.345 78.432 22.777 112.008 ;
     RECT  21.737 113.04 22.777 117.336 ;
     RECT  22.129 69.84 22.921 71.256 ;
     RECT  22.421 72.912 22.921 73.032 ;
     RECT  22.777 78.432 22.957 117.432 ;
     RECT  21.305 118.56 22.957 118.584 ;
     RECT  22.957 78.432 22.997 118.584 ;
     RECT  22.669 75.408 23.029 77.448 ;
     RECT  22.997 78.432 23.029 101.016 ;
     RECT  22.673 120.096 23.641 120.12 ;
     RECT  23.533 121.296 23.641 121.32 ;
     RECT  18.904 55.68 24.008 55.704 ;
     RECT  22.921 69.84 24.008 73.032 ;
     RECT  22.169 74.304 24.008 74.328 ;
     RECT  23.029 75.408 24.008 101.016 ;
     RECT  22.997 102.048 24.008 118.584 ;
     RECT  23.641 120.096 24.008 121.32 ;
     RECT  24.008 2.148 24.112 127.452 ;
     RECT  24.112 2.418 24.304 127.182 ;
     RECT  24.304 78.192 24.401 120.312 ;
     RECT  24.401 78.384 24.545 120.312 ;
     RECT  24.304 69.84 24.563 74.328 ;
     RECT  24.563 70.56 24.617 74.328 ;
     RECT  24.545 78.624 24.707 120.312 ;
     RECT  24.617 70.608 24.725 74.328 ;
     RECT  24.725 70.704 24.761 74.328 ;
     RECT  24.761 71.472 24.941 74.328 ;
     RECT  24.707 78.624 25.165 111.192 ;
     RECT  24.941 71.472 25.229 71.832 ;
     RECT  24.707 112.176 25.235 120.312 ;
     RECT  25.235 119.184 25.333 120.312 ;
     RECT  24.304 121.296 25.333 121.32 ;
     RECT  24.304 55.68 25.573 55.704 ;
     RECT  24.941 73.056 25.621 74.328 ;
     RECT  24.304 75.408 25.621 75.816 ;
     RECT  25.573 55.248 25.661 55.704 ;
     RECT  25.165 79.44 25.729 111.192 ;
     RECT  25.235 112.176 25.729 118.104 ;
     RECT  25.621 73.056 25.985 75.816 ;
     RECT  25.229 71.472 26.197 71.784 ;
     RECT  24.304 77.136 26.197 77.16 ;
     RECT  25.729 79.44 26.197 118.104 ;
     RECT  26.197 71.472 26.284 72.072 ;
     RECT  25.985 73.296 26.309 75.816 ;
     RECT  26.197 78.624 26.413 118.104 ;
     RECT  26.413 78.48 26.485 118.104 ;
     RECT  25.333 119.184 26.485 121.32 ;
     RECT  26.309 73.488 26.525 75.816 ;
     RECT  26.197 77.136 26.549 77.352 ;
     RECT  26.549 76.368 26.633 77.352 ;
     RECT  26.633 76.944 26.737 77.352 ;
     RECT  26.485 78.48 26.737 121.32 ;
     RECT  26.737 76.944 26.885 121.32 ;
     RECT  26.525 73.488 26.993 74.664 ;
     RECT  26.885 76.944 27.029 78.504 ;
     RECT  26.885 79.536 27.281 121.32 ;
     RECT  27.281 79.536 27.395 119.544 ;
     RECT  26.284 71.472 27.533 71.544 ;
     RECT  25.661 55.68 27.749 55.704 ;
     RECT  27.395 112.368 27.749 119.544 ;
     RECT  26.993 74.304 27.884 74.664 ;
     RECT  27.884 74.304 27.971 75.24 ;
     RECT  27.029 76.944 27.997 78.168 ;
     RECT  27.395 79.536 28.117 111.24 ;
     RECT  27.997 76.512 28.253 78.168 ;
     RECT  28.253 76.944 28.501 78.168 ;
     RECT  28.117 79.2 28.501 111.24 ;
     RECT  27.533 71.472 28.556 71.496 ;
     RECT  28.556 71.472 28.597 71.928 ;
     RECT  28.501 76.944 28.609 111.24 ;
     RECT  27.749 112.368 28.609 117.672 ;
     RECT  27.749 119.136 28.645 119.544 ;
     RECT  27.281 120.96 28.645 121.32 ;
     RECT  27.971 74.304 29.005 74.328 ;
     RECT  29.005 74.112 29.041 74.328 ;
     RECT  28.645 119.136 29.113 121.32 ;
     RECT  29.113 119.088 29.125 121.32 ;
     RECT  28.609 76.944 29.149 117.672 ;
     RECT  29.125 118.704 29.149 121.32 ;
     RECT  29.041 74.112 29.185 74.664 ;
     RECT  29.185 73.344 29.401 74.664 ;
     RECT  26.557 59.28 29.408 59.304 ;
     RECT  28.597 71.184 29.408 71.928 ;
     RECT  29.401 73.104 29.408 74.664 ;
     RECT  29.041 75.696 29.408 75.72 ;
     RECT  29.149 76.944 29.408 121.32 ;
     RECT  29.408 2.148 29.512 127.452 ;
     RECT  29.512 2.418 29.704 127.182 ;
     RECT  29.704 71.184 30.089 119.592 ;
     RECT  30.089 72.96 30.377 119.592 ;
     RECT  30.377 72.96 30.413 74.616 ;
     RECT  29.704 120.576 30.733 120.6 ;
     RECT  29.704 59.088 30.769 59.496 ;
     RECT  30.733 120.576 30.805 120.888 ;
     RECT  30.377 75.6 30.841 119.592 ;
     RECT  30.805 120.576 30.841 121.176 ;
     RECT  30.841 75.6 31.061 121.176 ;
     RECT  30.769 58.848 31.565 59.496 ;
     RECT  31.061 118.464 31.573 121.176 ;
     RECT  31.061 75.6 31.709 117.48 ;
     RECT  30.413 72.96 31.741 74.472 ;
     RECT  31.709 75.6 31.741 76.392 ;
     RECT  31.709 77.424 31.961 117.48 ;
     RECT  31.741 72.96 32.725 76.392 ;
     RECT  32.725 72.912 32.965 76.392 ;
     RECT  31.961 77.52 32.965 117.48 ;
     RECT  31.573 118.464 32.969 121.416 ;
     RECT  32.965 72.912 33.001 117.48 ;
     RECT  32.969 118.464 33.001 120.792 ;
     RECT  33.001 72.912 33.107 120.792 ;
     RECT  30.089 71.184 33.149 71.208 ;
     RECT  33.107 72.912 33.221 117.96 ;
     RECT  32.209 56.208 33.683 56.232 ;
     RECT  31.565 59.472 33.717 59.496 ;
     RECT  33.221 72.912 33.721 117.864 ;
     RECT  33.637 54.72 33.865 54.744 ;
     RECT  33.721 71.376 34.189 117.864 ;
     RECT  33.107 119.328 34.189 120.792 ;
     RECT  34.189 71.376 34.225 120.792 ;
     RECT  33.865 54.72 34.405 55.704 ;
     RECT  34.225 71.328 34.477 120.792 ;
     RECT  34.477 71.328 34.621 120.888 ;
     RECT  34.405 54.192 34.808 55.704 ;
     RECT  34.693 59.568 34.808 59.592 ;
     RECT  34.621 70.848 34.808 120.888 ;
     RECT  34.808 2.148 34.912 127.452 ;
     RECT  34.912 2.418 35.104 127.182 ;
     RECT  35.104 54.192 35.201 55.896 ;
     RECT  35.104 71.712 35.381 74.952 ;
     RECT  35.104 106.8 35.891 121.32 ;
     RECT  35.891 118.944 35.921 121.32 ;
     RECT  35.104 76.32 36.029 105.432 ;
     RECT  35.891 106.8 36.029 117.96 ;
     RECT  35.381 72 36.093 74.952 ;
     RECT  36.029 106.8 36.241 117.912 ;
     RECT  35.921 118.944 36.497 120.312 ;
     RECT  35.201 54.192 36.529 54.744 ;
     RECT  35.201 55.872 36.529 55.896 ;
     RECT  36.029 76.32 36.569 100.872 ;
     RECT  36.241 106.56 36.637 117.912 ;
     RECT  35.104 49.536 36.709 49.56 ;
     RECT  35.104 59.568 36.745 59.592 ;
     RECT  36.569 76.32 36.785 76.344 ;
     RECT  35.921 121.296 36.785 121.32 ;
     RECT  36.673 63.216 36.812 63.24 ;
     RECT  36.745 59.568 36.829 60.456 ;
     RECT  36.029 101.856 36.893 105.432 ;
     RECT  36.812 62.256 36.899 63.24 ;
     RECT  36.893 102.24 37.033 105.432 ;
     RECT  36.637 106.416 37.033 117.912 ;
     RECT  37.033 102.24 37.109 117.912 ;
     RECT  36.829 59.568 37.141 59.64 ;
     RECT  36.709 49.536 37.189 49.944 ;
     RECT  37.189 49.536 37.235 50.328 ;
     RECT  36.497 118.944 37.235 119.976 ;
     RECT  36.529 123.696 37.235 123.72 ;
     RECT  37.235 49.92 37.276 50.328 ;
     RECT  37.109 102.288 37.289 117.912 ;
     RECT  36.093 73.008 37.325 74.952 ;
     RECT  37.349 53.04 37.388 53.064 ;
     RECT  36.529 54.192 37.388 55.896 ;
     RECT  37.388 53.04 37.393 55.896 ;
     RECT  37.393 53.04 37.433 56.52 ;
     RECT  37.381 51.504 37.468 51.528 ;
     RECT  37.433 53.952 37.475 55.416 ;
     RECT  37.285 67.152 37.525 67.176 ;
     RECT  37.325 74.928 37.573 74.952 ;
     RECT  36.569 77.472 37.573 100.872 ;
     RECT  37.525 67.152 37.613 68.184 ;
     RECT  37.613 67.152 37.619 67.8 ;
     RECT  37.573 74.928 37.619 75.528 ;
     RECT  36.853 60.672 37.649 60.696 ;
     RECT  37.433 56.4 37.825 56.52 ;
     RECT  37.141 58.128 37.829 59.64 ;
     RECT  37.829 58.656 37.897 59.64 ;
     RECT  36.899 62.976 37.969 63.24 ;
     RECT  37.619 75.216 37.969 75.528 ;
     RECT  37.573 77.136 37.973 100.872 ;
     RECT  36.093 72 38.005 72.024 ;
     RECT  37.325 73.008 38.005 73.56 ;
     RECT  37.825 56.4 38.012 57.048 ;
     RECT  37.969 75.216 38.041 75.816 ;
     RECT  37.973 77.136 38.041 77.496 ;
     RECT  37.681 120.72 38.077 120.744 ;
     RECT  37.969 62.736 38.081 63.24 ;
     RECT  38.012 56.4 38.099 57.288 ;
     RECT  37.619 67.152 38.113 67.272 ;
     RECT  37.789 65.952 38.149 65.976 ;
     RECT  38.113 67.056 38.149 67.272 ;
     RECT  38.077 120.72 38.149 120.792 ;
     RECT  38.149 65.952 38.189 67.272 ;
     RECT  37.973 78.624 38.221 100.872 ;
     RECT  37.289 102.288 38.221 117.864 ;
     RECT  37.235 118.944 38.257 119.688 ;
     RECT  38.149 120.72 38.257 120.84 ;
     RECT  38.081 62.976 38.261 63.24 ;
     RECT  38.189 65.952 38.293 67.08 ;
     RECT  37.276 49.92 38.401 49.944 ;
     RECT  38.401 49.728 38.441 49.944 ;
     RECT  38.441 49.728 38.473 49.752 ;
     RECT  37.861 40.848 38.485 40.872 ;
     RECT  38.473 49.584 38.557 49.752 ;
     RECT  38.221 78.624 38.653 117.864 ;
     RECT  38.257 118.944 38.653 120.84 ;
     RECT  38.557 49.728 38.801 49.752 ;
     RECT  38.041 75.216 38.801 77.496 ;
     RECT  38.653 78.624 38.873 120.84 ;
     RECT  38.113 61.2 38.905 61.224 ;
     RECT  38.005 72 38.905 73.56 ;
     RECT  38.873 79.296 38.909 120.6 ;
     RECT  38.261 63.216 38.972 63.24 ;
     RECT  38.293 65.808 39.013 67.08 ;
     RECT  37.475 54.864 39.053 55.416 ;
     RECT  38.972 63.216 39.059 63.576 ;
     RECT  37.897 58.656 39.085 60.168 ;
     RECT  38.905 61.2 39.085 61.752 ;
     RECT  38.761 46.32 39.121 46.344 ;
     RECT  39.085 58.656 39.121 61.752 ;
     RECT  39.053 55.392 39.157 55.416 ;
     RECT  38.099 56.4 39.157 56.424 ;
     RECT  39.085 57.408 39.157 57.432 ;
     RECT  39.121 58.656 39.157 62.184 ;
     RECT  38.801 75.696 39.229 77.496 ;
     RECT  39.157 55.392 39.337 62.184 ;
     RECT  39.26 51.12 39.397 51.144 ;
     RECT  39.121 45.696 39.553 46.344 ;
     RECT  38.905 72 39.625 74.136 ;
     RECT  39.625 72 39.913 74.232 ;
     RECT  39.397 51.12 39.949 51.288 ;
     RECT  39.049 53.568 39.98 53.592 ;
     RECT  39.337 55.392 40.021 62.76 ;
     RECT  39.913 72 40.021 74.664 ;
     RECT  39.229 75.696 40.021 77.976 ;
     RECT  38.485 40.032 40.069 40.872 ;
     RECT  39.553 45.696 40.069 46.536 ;
     RECT  38.909 79.296 40.129 119.688 ;
     RECT  39.625 4.128 40.208 4.152 ;
     RECT  40.069 40.032 40.208 40.92 ;
     RECT  40.069 45.024 40.208 46.536 ;
     RECT  39.949 50.88 40.208 51.288 ;
     RECT  39.98 53.568 40.208 54.216 ;
     RECT  40.021 55.296 40.208 62.76 ;
     RECT  39.013 64.992 40.208 67.08 ;
     RECT  37.525 70.032 40.208 70.056 ;
     RECT  40.021 72 40.208 77.976 ;
     RECT  40.129 79.248 40.208 119.688 ;
     RECT  40.208 2.148 40.312 127.452 ;
     RECT  40.312 2.418 40.504 127.182 ;
     RECT  40.504 73.056 40.565 73.656 ;
     RECT  40.504 75.12 40.601 119.448 ;
     RECT  40.504 57.696 40.745 61.08 ;
     RECT  40.601 75.504 40.889 119.448 ;
     RECT  40.504 44.16 40.961 48.504 ;
     RECT  40.961 44.16 41.033 47.928 ;
     RECT  41.033 44.16 41.069 46.728 ;
     RECT  40.889 75.504 41.141 117.864 ;
     RECT  41.141 76.512 41.171 117.864 ;
     RECT  41.171 78.384 41.219 117.864 ;
     RECT  41.171 76.512 41.249 77.16 ;
     RECT  41.219 78.672 41.249 117.864 ;
     RECT  40.889 118.944 41.321 119.448 ;
     RECT  40.504 120.72 41.321 120.792 ;
     RECT  40.745 58.08 41.605 61.08 ;
     RECT  40.504 62.832 41.605 63.48 ;
     RECT  41.605 58.08 41.749 64.344 ;
     RECT  41.321 119.376 41.897 119.448 ;
     RECT  41.249 78.96 41.929 117.864 ;
     RECT  41.069 44.16 42.073 46.488 ;
     RECT  41.749 58.08 42.109 64.632 ;
     RECT  42.073 44.16 42.145 46.872 ;
     RECT  42.109 57.696 42.145 64.632 ;
     RECT  40.504 42.48 42.421 43.032 ;
     RECT  41.321 120.72 42.433 120.744 ;
     RECT  42.433 120.72 42.437 121.272 ;
     RECT  41.929 78.96 42.577 118.344 ;
     RECT  42.145 57.6 42.721 64.92 ;
     RECT  42.577 78.528 42.757 118.344 ;
     RECT  41.897 119.376 42.757 119.4 ;
     RECT  41.249 76.512 42.812 77.064 ;
     RECT  42.721 57.504 42.973 64.92 ;
     RECT  42.757 78.528 43.049 119.4 ;
     RECT  42.145 44.064 43.081 46.872 ;
     RECT  41.033 47.904 43.081 47.928 ;
     RECT  42.421 42.432 43.093 43.032 ;
     RECT  43.081 44.064 43.093 47.928 ;
     RECT  42.812 76.272 43.117 77.064 ;
     RECT  43.049 118.656 43.121 119.4 ;
     RECT  40.504 39.744 43.189 41.016 ;
     RECT  43.049 78.528 43.193 117.576 ;
     RECT  43.093 42.432 43.2 47.928 ;
     RECT  42.973 57.312 43.2 64.92 ;
     RECT  43.193 78.528 43.235 117.48 ;
     RECT  43.2 42.432 43.272 64.92 ;
     RECT  40.565 73.056 43.272 73.08 ;
     RECT  43.189 38.784 43.285 41.016 ;
     RECT  43.235 78.576 43.324 117.48 ;
     RECT  43.285 38.16 43.331 41.016 ;
     RECT  42.437 121.248 43.373 121.272 ;
     RECT  43.117 76.272 43.729 77.4 ;
     RECT  43.121 118.704 44.237 119.4 ;
     RECT  43.324 83.328 44.243 117.48 ;
     RECT  43.729 75.744 44.305 77.4 ;
     RECT  44.243 83.328 44.453 117.384 ;
     RECT  44.305 75.408 44.483 77.4 ;
     RECT  44.237 118.704 44.525 119.112 ;
     RECT  44.483 76.368 44.561 77.4 ;
     RECT  44.561 76.464 44.773 77.4 ;
     RECT  43.324 78.576 44.773 82.2 ;
     RECT  44.773 76.464 45.385 82.2 ;
     RECT  44.453 83.328 45.568 91.32 ;
     RECT  45.568 83.28 45.601 91.32 ;
     RECT  44.453 92.448 45.601 117.384 ;
     RECT  40.504 4.128 45.608 4.152 ;
     RECT  43.331 38.16 45.608 38.184 ;
     RECT  43.331 39.744 45.608 41.016 ;
     RECT  45.385 76.464 45.608 82.248 ;
     RECT  45.601 83.28 45.608 117.384 ;
     RECT  44.525 118.704 45.608 118.728 ;
     RECT  45.608 2.148 45.712 41.052 ;
     RECT  45.608 75.048 45.712 127.452 ;
     RECT  45.712 2.418 45.904 41.016 ;
     RECT  45.712 75.318 45.904 127.182 ;
     RECT  45.904 118.704 46.001 118.728 ;
     RECT  45.904 92.64 46.037 94.632 ;
     RECT  45.904 99.168 46.037 107.064 ;
     RECT  46.037 92.64 46.181 94.536 ;
     RECT  45.904 108.144 46.211 117.384 ;
     RECT  45.904 95.904 46.253 98.088 ;
     RECT  46.037 99.168 46.289 106.584 ;
     RECT  46.211 108.144 46.307 111.192 ;
     RECT  46.289 99.264 46.325 106.584 ;
     RECT  45.904 79.056 46.361 91.224 ;
     RECT  46.325 99.696 46.361 106.584 ;
     RECT  45.904 37.632 46.477 38.184 ;
     RECT  46.253 97.536 46.505 98.088 ;
     RECT  46.361 85.104 46.541 91.224 ;
     RECT  46.361 103.152 46.547 106.584 ;
     RECT  46.541 85.2 46.721 91.224 ;
     RECT  46.211 112.272 46.721 117.384 ;
     RECT  46.477 38.16 46.757 38.184 ;
     RECT  46.253 95.904 46.793 96.504 ;
     RECT  46.547 104.208 46.793 106.584 ;
     RECT  46.721 115.104 46.828 117.384 ;
     RECT  46.828 116.832 46.937 117.384 ;
     RECT  46.361 79.056 46.973 84.072 ;
     RECT  46.361 99.696 47.009 102.168 ;
     RECT  45.904 75.744 47.185 76.824 ;
     RECT  46.721 112.272 47.257 113.976 ;
     RECT  46.973 79.056 47.297 82.104 ;
     RECT  46.307 108.144 47.333 110.904 ;
     RECT  47.185 75.744 47.369 77.016 ;
     RECT  46.721 85.44 47.372 91.224 ;
     RECT  46.181 92.64 47.372 94.44 ;
     RECT  47.372 85.44 47.441 94.44 ;
     RECT  47.441 85.44 47.459 93.576 ;
     RECT  47.369 75.744 47.513 76.824 ;
     RECT  46.547 103.152 47.545 103.176 ;
     RECT  46.793 104.208 47.545 105.144 ;
     RECT  47.513 75.744 47.549 76.536 ;
     RECT  47.459 92.304 47.549 93.576 ;
     RECT  47.257 111.936 47.549 113.976 ;
     RECT  46.793 96.048 47.581 96.504 ;
     RECT  46.505 97.536 47.581 97.56 ;
     RECT  47.545 103.152 47.585 105.144 ;
     RECT  46.937 116.832 47.801 116.856 ;
     RECT  46.973 83.184 47.833 84.072 ;
     RECT  47.459 85.44 47.833 91.224 ;
     RECT  47.581 96.048 47.869 97.56 ;
     RECT  47.333 110.496 47.893 110.904 ;
     RECT  47.549 112.272 47.893 113.976 ;
     RECT  46.828 115.104 47.909 115.128 ;
     RECT  47.893 112.272 47.939 114.024 ;
     RECT  47.297 80.352 48.017 82.104 ;
     RECT  47.893 110.496 48.035 110.952 ;
     RECT  48.017 80.832 48.085 82.104 ;
     RECT  47.833 83.184 48.085 91.224 ;
     RECT  47.333 108.144 48.197 109.416 ;
     RECT  48.035 110.88 48.269 110.952 ;
     RECT  47.549 92.304 48.377 92.952 ;
     RECT  47.869 95.184 48.377 97.56 ;
     RECT  47.009 99.696 48.377 102.024 ;
     RECT  47.297 79.152 48.445 79.272 ;
     RECT  46.793 106.56 48.449 106.584 ;
     RECT  48.085 80.832 48.557 91.224 ;
     RECT  47.585 103.872 48.557 105.144 ;
     RECT  48.377 92.88 48.593 92.952 ;
     RECT  48.445 79.152 48.665 79.8 ;
     RECT  48.377 99.696 48.665 101.352 ;
     RECT  48.665 79.152 48.707 79.176 ;
     RECT  47.939 114 48.773 114.024 ;
     RECT  48.197 108.144 48.809 109.368 ;
     RECT  48.377 95.184 49.061 97.464 ;
     RECT  47.549 75.936 49.165 76.536 ;
     RECT  48.661 102.48 49.283 102.504 ;
     RECT  48.269 110.88 49.313 110.904 ;
     RECT  48.633 78.096 49.381 78.12 ;
     RECT  48.557 80.832 49.385 90.792 ;
     RECT  48.665 99.936 49.421 101.352 ;
     RECT  45.904 32.448 49.525 32.472 ;
     RECT  48.809 108.864 49.529 109.368 ;
     RECT  49.385 82.608 49.565 90.792 ;
     RECT  49.421 99.936 49.601 101.064 ;
     RECT  49.525 31.92 49.609 32.472 ;
     RECT  48.557 103.872 49.637 104.952 ;
     RECT  48.593 92.928 49.669 92.952 ;
     RECT  49.628 106.128 49.669 106.152 ;
     RECT  49.529 108.864 49.673 109.272 ;
     RECT  49.669 105.408 49.715 106.152 ;
     RECT  49.061 96.048 49.765 97.464 ;
     RECT  49.381 78.096 49.885 78.648 ;
     RECT  49.609 32.448 49.889 32.472 ;
     RECT  49.165 75.936 49.921 77.064 ;
     RECT  49.385 80.832 50.029 81.336 ;
     RECT  49.765 96.048 50.101 97.896 ;
     RECT  49.637 103.872 50.137 104.28 ;
     RECT  49.669 92.304 50.317 92.952 ;
     RECT  49.885 78.096 50.389 79.464 ;
     RECT  50.029 80.64 50.389 81.336 ;
     RECT  50.101 95.184 50.425 97.896 ;
     RECT  49.921 75.84 50.533 77.064 ;
     RECT  50.389 78.096 50.533 81.336 ;
     RECT  49.601 99.936 50.605 99.96 ;
     RECT  50.605 107.712 50.629 107.736 ;
     RECT  49.673 108.864 50.629 108.888 ;
     RECT  50.605 99.552 50.677 99.96 ;
     RECT  50.533 75.84 50.684 81.336 ;
     RECT  49.565 82.608 50.684 83.208 ;
     RECT  50.137 103.488 50.713 104.28 ;
     RECT  50.629 107.712 50.749 108.888 ;
     RECT  45.904 4.128 51.008 4.152 ;
     RECT  49.525 27.12 51.008 27.144 ;
     RECT  45.904 39.744 51.008 41.016 ;
     RECT  50.684 75.84 51.008 83.208 ;
     RECT  49.565 84.336 51.008 90.792 ;
     RECT  50.317 92.304 51.008 93.144 ;
     RECT  50.677 94.128 51.008 94.152 ;
     RECT  50.425 95.184 51.008 98.136 ;
     RECT  50.677 99.216 51.008 99.96 ;
     RECT  49.601 101.04 51.008 101.064 ;
     RECT  50.713 102.624 51.008 104.28 ;
     RECT  49.715 105.408 51.008 105.432 ;
     RECT  50.749 106.992 51.008 108.888 ;
     RECT  51.008 2.148 51.112 41.052 ;
     RECT  51.008 75.048 51.112 127.452 ;
     RECT  51.112 2.418 51.304 41.016 ;
     RECT  51.112 75.318 51.304 127.182 ;
     RECT  51.304 94.128 51.329 96.744 ;
     RECT  51.329 94.176 51.437 96.744 ;
     RECT  51.304 84.24 51.473 90.792 ;
     RECT  51.437 95.952 51.491 96.744 ;
     RECT  51.304 75.792 51.509 82.488 ;
     RECT  51.304 105.36 51.587 106.056 ;
     RECT  51.304 98.112 51.653 104.136 ;
     RECT  51.509 75.792 52.013 82.056 ;
     RECT  51.653 98.928 52.309 104.136 ;
     RECT  51.587 105.36 52.309 105.432 ;
     RECT  52.309 98.928 52.355 105.432 ;
     RECT  52.355 105.024 52.396 105.432 ;
     RECT  52.396 105.36 52.417 105.432 ;
     RECT  51.473 84.24 52.445 87.624 ;
     RECT  52.417 105.36 52.553 105.384 ;
     RECT  52.508 83.232 52.595 83.256 ;
     RECT  52.445 84.24 52.697 86.328 ;
     RECT  51.304 27.12 52.729 27.144 ;
     RECT  52.697 85.728 52.805 86.328 ;
     RECT  52.729 26.784 52.813 27.144 ;
     RECT  52.697 84.24 52.837 84.36 ;
     RECT  51.437 94.176 52.885 94.68 ;
     RECT  51.491 95.952 52.885 96.504 ;
     RECT  52.013 75.792 52.931 79.704 ;
     RECT  52.885 94.176 52.979 96.504 ;
     RECT  52.355 98.928 52.981 103.272 ;
     RECT  52.445 87.408 53.021 87.624 ;
     RECT  52.979 94.656 53.021 96.504 ;
     RECT  52.813 27.12 53.057 27.144 ;
     RECT  52.931 78.672 53.057 79.704 ;
     RECT  52.981 98.592 53.057 103.272 ;
     RECT  52.013 81.312 53.125 82.056 ;
     RECT  53.057 98.592 53.129 102.984 ;
     RECT  53.021 95.952 53.237 96.504 ;
     RECT  52.885 97.488 53.273 97.512 ;
     RECT  53.057 78.72 53.345 79.704 ;
     RECT  53.345 79.44 53.449 79.704 ;
     RECT  53.125 81.312 53.449 82.68 ;
     RECT  52.357 110.016 53.453 110.04 ;
     RECT  51.304 92.928 53.845 92.952 ;
     RECT  52.805 85.776 53.941 86.328 ;
     RECT  52.931 75.792 53.987 77.688 ;
     RECT  53.129 98.928 53.993 102.984 ;
     RECT  53.449 79.44 54.061 82.68 ;
     RECT  52.837 83.664 54.061 84.36 ;
     RECT  51.304 108.144 54.085 108.168 ;
     RECT  54.085 107.808 54.131 108.168 ;
     RECT  54.085 110.16 54.172 110.184 ;
     RECT  53.993 98.928 54.173 101.88 ;
     RECT  53.987 76.512 54.373 77.688 ;
     RECT  54.061 79.44 54.373 84.36 ;
     RECT  54.385 74.688 54.469 74.712 ;
     RECT  53.993 102.912 54.53 102.984 ;
     RECT  52.741 21.6 54.709 21.624 ;
     RECT  53.021 87.6 54.709 87.624 ;
     RECT  51.473 88.608 54.709 90.792 ;
     RECT  54.529 91.776 54.709 91.8 ;
     RECT  53.021 94.656 54.745 94.728 ;
     RECT  54.709 21.504 54.749 21.624 ;
     RECT  54.173 98.928 54.785 101.064 ;
     RECT  54.745 94.608 54.893 94.728 ;
     RECT  54.373 76.512 54.901 84.36 ;
     RECT  53.941 85.632 54.901 86.328 ;
     RECT  54.901 76.512 55.073 86.328 ;
     RECT  53.237 96.048 55.1 96.504 ;
     RECT  54.893 94.704 55.141 94.728 ;
     RECT  55.1 95.904 55.141 96.504 ;
     RECT  55.141 94.704 55.187 96.504 ;
     RECT  54.785 98.928 55.213 100.056 ;
     RECT  55.073 76.512 55.253 83.544 ;
     RECT  55.213 97.872 55.325 100.056 ;
     RECT  55.187 94.704 55.361 94.968 ;
     RECT  55.073 85.104 55.537 86.328 ;
     RECT  54.709 87.6 55.537 91.8 ;
     RECT  53.845 92.928 55.753 93.48 ;
     RECT  55.187 96.048 55.765 96.504 ;
     RECT  55.325 97.872 55.765 98.664 ;
     RECT  54.749 21.504 55.861 21.528 ;
     RECT  55.537 85.104 55.933 91.8 ;
     RECT  55.753 92.88 55.933 93.48 ;
     RECT  55.253 76.512 56.005 81.816 ;
     RECT  55.933 85.104 56.293 93.48 ;
     RECT  55.325 99.744 56.293 100.056 ;
     RECT  54.785 101.04 56.293 101.064 ;
     RECT  56.293 85.104 56.365 93.528 ;
     RECT  51.304 4.128 56.408 4.152 ;
     RECT  55.861 16.368 56.408 16.392 ;
     RECT  55.861 21.12 56.408 21.528 ;
     RECT  51.304 39.744 56.408 41.016 ;
     RECT  56.005 76.464 56.408 81.816 ;
     RECT  55.253 82.8 56.408 83.544 ;
     RECT  56.365 85.104 56.408 93.768 ;
     RECT  55.361 94.944 56.408 94.968 ;
     RECT  55.765 96.048 56.408 98.664 ;
     RECT  56.293 99.744 56.408 101.064 ;
     RECT  54.53 102.912 56.408 102.936 ;
     RECT  54.131 107.808 56.408 107.832 ;
     RECT  56.408 2.148 56.512 41.052 ;
     RECT  56.408 75.048 56.512 127.452 ;
     RECT  56.512 2.418 56.704 41.016 ;
     RECT  56.512 75.318 56.704 127.182 ;
     RECT  56.704 85.44 57.161 87 ;
     RECT  57.161 85.44 57.197 86.616 ;
     RECT  56.704 88.464 57.233 90.888 ;
     RECT  56.704 99.504 57.521 100.056 ;
     RECT  56.704 96.48 57.557 97.896 ;
     RECT  56.704 75.936 57.629 84.312 ;
     RECT  57.521 100.032 57.841 100.056 ;
     RECT  56.704 101.04 57.841 101.112 ;
     RECT  57.629 83.568 57.877 84.312 ;
     RECT  57.197 85.44 57.877 86.328 ;
     RECT  57.841 100.032 57.881 101.112 ;
     RECT  56.704 103.728 58.076 103.752 ;
     RECT  58.076 103.392 58.117 103.752 ;
     RECT  57.557 97.248 58.129 97.896 ;
     RECT  58.117 103.392 58.163 104.232 ;
     RECT  43.272 42.432 58.165 73.08 ;
     RECT  56.704 92.256 58.205 94.68 ;
     RECT  57.877 83.568 58.268 86.328 ;
     RECT  58.205 94.368 58.277 94.68 ;
     RECT  58.163 103.728 58.277 104.232 ;
     RECT  57.233 88.608 58.309 90.888 ;
     RECT  58.309 87.792 58.349 90.888 ;
     RECT  58.165 42.432 58.403 73.512 ;
     RECT  58.205 92.256 58.417 92.808 ;
     RECT  58.277 94.56 58.493 94.68 ;
     RECT  56.704 16.368 58.501 16.392 ;
     RECT  58.129 97.248 58.525 98.376 ;
     RECT  58.349 87.792 58.529 90.072 ;
     RECT  57.629 75.936 58.633 82.488 ;
     RECT  58.525 97.248 58.633 99 ;
     RECT  56.704 39.744 58.645 41.016 ;
     RECT  58.633 75.744 58.669 82.488 ;
     RECT  58.268 83.568 58.669 86.616 ;
     RECT  58.501 16.272 58.705 16.392 ;
     RECT  58.669 75.744 58.705 86.616 ;
     RECT  58.633 97.104 58.813 99 ;
     RECT  57.881 100.032 58.813 101.064 ;
     RECT  58.813 97.104 58.849 101.064 ;
     RECT  58.277 103.824 58.925 104.232 ;
     RECT  58.705 16.272 59.029 16.536 ;
     RECT  58.849 96.816 59.101 101.064 ;
     RECT  59.029 15.984 59.113 16.536 ;
     RECT  58.417 91.68 59.209 92.808 ;
     RECT  59.101 96.576 59.209 101.064 ;
     RECT  59.209 91.68 59.249 93.48 ;
     RECT  59.209 96.576 59.321 101.208 ;
     RECT  59.113 16.272 59.393 16.536 ;
     RECT  59.321 100.224 59.461 101.208 ;
     RECT  59.221 102.336 59.461 102.36 ;
     RECT  58.705 75.264 59.497 86.616 ;
     RECT  58.529 88.608 59.497 90.072 ;
     RECT  59.249 92.4 59.605 93.48 ;
     RECT  58.493 94.56 59.605 94.632 ;
     RECT  59.497 75.264 59.753 87.192 ;
     RECT  59.461 100.224 59.825 102.36 ;
     RECT  59.425 105.888 59.893 105.912 ;
     RECT  59.753 76.464 59.933 87.192 ;
     RECT  59.825 100.224 59.933 101.064 ;
     RECT  58.925 104.208 59.965 104.232 ;
     RECT  59.965 103.44 60.005 104.232 ;
     RECT  59.321 96.576 60.361 99 ;
     RECT  59.497 88.224 60.371 90.072 ;
     RECT  60.371 88.608 60.433 90.072 ;
     RECT  59.785 91.152 60.433 91.176 ;
     RECT  59.753 75.264 60.517 75.432 ;
     RECT  60.433 88.608 60.572 91.176 ;
     RECT  59.605 92.4 60.572 94.632 ;
     RECT  59.933 76.512 60.797 87.192 ;
     RECT  60.361 95.904 60.973 99 ;
     RECT  60.572 88.608 60.997 94.632 ;
     RECT  60.973 95.904 60.997 99.192 ;
     RECT  59.933 100.608 61.009 101.064 ;
     RECT  59.825 102.336 61.009 102.36 ;
     RECT  60.997 88.608 61.045 99.192 ;
     RECT  61.009 100.608 61.045 102.36 ;
     RECT  61.045 88.608 61.117 102.36 ;
     RECT  60.005 103.44 61.117 103.896 ;
     RECT  60.517 75.216 61.261 75.432 ;
     RECT  60.797 76.512 61.261 85.944 ;
     RECT  59.893 105.36 61.261 105.912 ;
     RECT  60.797 87.168 61.441 87.192 ;
     RECT  61.117 88.608 61.441 103.896 ;
     RECT  61.261 105.36 61.513 106.008 ;
     RECT  61.261 75.216 61.588 85.944 ;
     RECT  61.441 87.168 61.669 103.896 ;
     RECT  61.513 105.216 61.669 106.008 ;
     RECT  56.704 4.128 61.808 4.152 ;
     RECT  59.029 11.232 61.808 11.256 ;
     RECT  59.393 16.272 61.808 16.296 ;
     RECT  58.645 39.456 61.808 41.016 ;
     RECT  61.588 75.168 61.808 85.944 ;
     RECT  61.669 87.168 61.808 106.008 ;
     RECT  56.704 107.808 61.808 107.832 ;
     RECT  61.808 2.148 61.912 41.052 ;
     RECT  61.808 75.048 61.912 127.452 ;
     RECT  61.912 2.418 62.104 41.016 ;
     RECT  61.912 75.168 62.104 127.182 ;
     RECT  62.104 10.848 62.291 11.256 ;
     RECT  62.104 75.168 62.309 106.632 ;
     RECT  62.291 11.232 62.525 11.256 ;
     RECT  62.309 102.384 62.857 106.632 ;
     RECT  62.857 102.384 62.885 106.536 ;
     RECT  62.885 104.832 63.065 106.536 ;
     RECT  62.309 75.168 63.101 101.16 ;
     RECT  63.101 88.512 63.245 101.16 ;
     RECT  63.245 88.512 63.497 101.112 ;
     RECT  63.101 75.168 63.731 87.192 ;
     RECT  63.731 75.264 63.749 87.192 ;
     RECT  62.885 102.384 63.853 103.752 ;
     RECT  63.065 104.832 63.853 105.432 ;
     RECT  63.853 102.384 63.889 105.432 ;
     RECT  63.749 86.832 64.069 87.192 ;
     RECT  63.497 88.512 64.069 90.648 ;
     RECT  63.497 91.68 64.364 101.112 ;
     RECT  63.889 102.336 64.433 105.432 ;
     RECT  64.433 102.336 64.469 105.384 ;
     RECT  63.065 106.464 64.501 106.536 ;
     RECT  62.104 107.808 64.501 107.832 ;
     RECT  64.469 103.536 64.613 105.384 ;
     RECT  64.501 106.464 64.721 108.312 ;
     RECT  63.749 75.264 64.825 85.8 ;
     RECT  64.069 86.832 64.825 90.648 ;
     RECT  64.721 106.512 64.865 108.312 ;
     RECT  64.364 91.68 64.969 101.352 ;
     RECT  64.469 102.336 64.969 102.504 ;
     RECT  64.825 75.264 65.041 90.648 ;
     RECT  64.969 91.68 65.041 102.504 ;
     RECT  64.865 107.376 65.117 108.312 ;
     RECT  65.117 107.376 65.333 107.64 ;
     RECT  62.104 5.616 65.509 5.64 ;
     RECT  65.509 5.472 65.693 5.64 ;
     RECT  64.613 103.536 65.833 105.24 ;
     RECT  65.041 75.264 65.869 102.504 ;
     RECT  65.833 103.536 65.869 105.432 ;
     RECT  65.869 75.264 65.909 105.432 ;
     RECT  65.909 75.264 66.197 103.608 ;
     RECT  65.333 107.616 66.901 107.64 ;
     RECT  65.909 104.64 67.057 105.432 ;
     RECT  66.901 106.56 67.057 107.64 ;
     RECT  62.104 4.128 67.208 4.152 ;
     RECT  65.693 5.472 67.208 5.496 ;
     RECT  62.104 16.272 67.208 16.296 ;
     RECT  62.104 39.744 67.208 41.016 ;
     RECT  66.197 75.264 67.208 90.072 ;
     RECT  66.197 91.056 67.208 103.608 ;
     RECT  67.057 104.64 67.208 107.64 ;
     RECT  67.208 2.148 67.312 41.052 ;
     RECT  67.208 75.048 67.312 127.452 ;
     RECT  67.312 2.418 67.504 41.016 ;
     RECT  67.312 75.318 67.504 127.182 ;
     RECT  67.504 75.456 67.961 107.64 ;
     RECT  67.504 3.36 68.099 4.152 ;
     RECT  68.099 3.36 68.141 3.384 ;
     RECT  67.961 104.64 68.249 107.64 ;
     RECT  67.504 5.472 68.485 5.496 ;
     RECT  68.249 104.832 68.497 107.64 ;
     RECT  68.485 5.472 68.531 5.688 ;
     RECT  68.173 0.576 68.627 0.6 ;
     RECT  67.961 75.456 68.629 103.56 ;
     RECT  68.497 104.832 68.645 107.736 ;
     RECT  68.531 5.664 68.675 5.688 ;
     RECT  67.504 108.864 69.005 108.888 ;
     RECT  68.645 104.88 69.397 107.736 ;
     RECT  68.629 75.264 69.865 103.56 ;
     RECT  69.865 75.264 69.901 103.752 ;
     RECT  69.397 104.88 69.901 108.312 ;
     RECT  69.901 75.264 70.049 108.312 ;
     RECT  70.049 105.312 70.297 108.312 ;
     RECT  69.109 109.392 70.297 109.416 ;
     RECT  67.504 39.744 70.657 41.016 ;
     RECT  70.049 75.264 70.913 104.28 ;
     RECT  70.297 105.312 71.053 109.416 ;
     RECT  70.913 75.312 71.161 104.28 ;
     RECT  71.053 105.312 71.161 109.464 ;
     RECT  71.161 75.312 71.365 109.464 ;
     RECT  71.365 75.312 71.489 109.944 ;
     RECT  71.489 75.312 71.633 107.016 ;
     RECT  71.489 108.288 72.205 109.944 ;
     RECT  67.504 16.272 72.608 16.68 ;
     RECT  70.657 39.744 72.608 41.16 ;
     RECT  71.633 75.312 72.608 85.512 ;
     RECT  71.633 86.64 72.608 107.016 ;
     RECT  72.205 108.288 72.608 110.04 ;
     RECT  72.608 2.148 72.712 41.16 ;
     RECT  72.608 75.048 72.712 127.452 ;
     RECT  72.712 2.418 72.904 41.16 ;
     RECT  72.712 75.264 72.904 127.182 ;
     RECT  72.904 105.984 72.965 108.36 ;
     RECT  72.904 109.44 73.001 109.8 ;
     RECT  72.965 106.032 73.964 108.36 ;
     RECT  72.904 77.856 73.973 104.904 ;
     RECT  73.973 104.88 74.053 104.904 ;
     RECT  73.964 105.888 74.053 108.36 ;
     RECT  74.053 104.88 74.14 108.36 ;
     RECT  74.14 106.512 74.221 108.36 ;
     RECT  73.001 109.44 74.221 109.704 ;
     RECT  74.221 106.512 74.297 109.704 ;
     RECT  74.297 106.512 74.369 109.464 ;
     RECT  73.973 77.856 74.513 103.8 ;
     RECT  74.369 108.816 74.531 109.464 ;
     RECT  72.904 75.264 74.657 76.776 ;
     RECT  74.657 75.264 74.915 75.816 ;
     RECT  74.531 109.104 75.155 109.464 ;
     RECT  75.155 109.44 75.341 109.464 ;
     RECT  74.14 104.88 75.541 105.432 ;
     RECT  74.369 106.512 75.541 107.832 ;
     RECT  75.541 104.88 75.593 107.832 ;
     RECT  75.593 105.984 75.628 107.832 ;
     RECT  74.869 76.8 75.661 76.824 ;
     RECT  74.513 77.856 75.661 103.464 ;
     RECT  75.661 76.8 75.913 103.464 ;
     RECT  75.593 104.88 75.913 104.952 ;
     RECT  72.904 39.744 76.345 41.16 ;
     RECT  75.628 106.56 76.457 107.832 ;
     RECT  75.913 76.8 76.673 104.952 ;
     RECT  76.673 77.616 77.065 104.952 ;
     RECT  76.457 106.752 77.209 107.832 ;
     RECT  76.813 108.864 77.209 108.888 ;
     RECT  72.904 16.272 78.008 16.68 ;
     RECT  76.345 39.744 78.008 41.208 ;
     RECT  74.915 75.264 78.008 75.48 ;
     RECT  77.065 77.616 78.008 105.096 ;
     RECT  77.209 106.752 78.008 108.888 ;
     RECT  78.008 2.148 78.112 41.208 ;
     RECT  78.008 75.048 78.112 127.452 ;
     RECT  78.112 2.418 78.221 41.208 ;
     RECT  78.221 2.418 78.304 41.16 ;
     RECT  78.112 75.264 78.304 127.182 ;
     RECT  78.304 78.432 78.419 105.48 ;
     RECT  78.304 106.752 78.419 108.744 ;
     RECT  78.419 106.992 78.437 108.744 ;
     RECT  78.419 78.432 78.509 102.744 ;
     RECT  78.419 104.256 78.707 105.48 ;
     RECT  78.437 106.992 78.725 108.168 ;
     RECT  78.509 78.432 78.851 101.496 ;
     RECT  78.851 84.144 79.013 101.496 ;
     RECT  79.013 84.144 79.085 101.448 ;
     RECT  79.085 87.696 79.337 101.448 ;
     RECT  78.725 106.992 79.441 107.832 ;
     RECT  79.441 106.608 79.481 107.832 ;
     RECT  79.481 106.608 79.525 107.736 ;
     RECT  79.525 106.992 79.805 107.736 ;
     RECT  78.509 102.48 79.873 102.744 ;
     RECT  79.085 84.144 80.057 86.712 ;
     RECT  79.805 106.992 80.093 107.016 ;
     RECT  79.873 102.48 80.101 103.224 ;
     RECT  78.707 104.256 80.101 105.432 ;
     RECT  80.057 86.544 80.161 86.712 ;
     RECT  79.337 87.696 80.161 101.064 ;
     RECT  80.101 102.48 80.188 105.432 ;
     RECT  78.851 78.432 80.417 83.16 ;
     RECT  80.417 78.624 80.489 83.16 ;
     RECT  80.188 102.48 80.489 102.744 ;
     RECT  80.489 78.624 80.561 83.016 ;
     RECT  80.489 102.48 80.737 102.696 ;
     RECT  78.304 16.272 80.849 16.68 ;
     RECT  80.561 78.912 80.921 83.016 ;
     RECT  80.188 104.496 80.993 105.432 ;
     RECT  80.161 86.544 81.065 101.064 ;
     RECT  80.993 104.928 81.173 105.432 ;
     RECT  81.065 86.544 81.209 99.144 ;
     RECT  79.585 76.944 81.241 76.968 ;
     RECT  81.241 76.944 81.281 77.496 ;
     RECT  80.057 84.144 81.313 85.416 ;
     RECT  81.065 100.32 81.445 101.064 ;
     RECT  81.209 91.872 81.461 99.144 ;
     RECT  80.737 102.384 81.491 102.696 ;
     RECT  81.491 102.624 81.493 102.696 ;
     RECT  80.921 78.912 81.497 78.936 ;
     RECT  81.313 84.144 81.533 85.512 ;
     RECT  81.493 102.624 81.533 102.936 ;
     RECT  81.533 84.288 81.637 85.512 ;
     RECT  81.209 86.544 81.637 90.6 ;
     RECT  81.637 84.288 81.677 90.6 ;
     RECT  81.461 91.872 81.677 97.368 ;
     RECT  81.461 98.64 81.821 99.144 ;
     RECT  81.677 84.336 81.929 90.6 ;
     RECT  81.821 98.88 82.033 99.144 ;
     RECT  80.849 16.656 82.105 16.68 ;
     RECT  81.929 84.336 82.109 84.696 ;
     RECT  81.281 77.472 82.115 77.496 ;
     RECT  82.105 16.416 82.145 16.68 ;
     RECT  80.921 80.016 82.145 83.016 ;
     RECT  82.069 78.672 82.153 78.696 ;
     RECT  82.145 16.416 82.355 16.44 ;
     RECT  81.677 96.864 82.397 97.368 ;
     RECT  81.929 86.064 82.501 90.6 ;
     RECT  81.677 91.872 82.501 95.736 ;
     RECT  82.397 97.056 82.573 97.368 ;
     RECT  81.445 100.32 82.609 101.304 ;
     RECT  81.533 102.672 82.609 102.936 ;
     RECT  82.501 86.064 83.185 95.736 ;
     RECT  83.185 85.824 83.269 95.736 ;
     RECT  78.304 39.744 83.408 41.16 ;
     RECT  78.304 75.264 83.408 75.48 ;
     RECT  83.208 79.152 83.408 79.176 ;
     RECT  82.145 81.024 83.408 83.016 ;
     RECT  82.109 84.672 83.408 84.696 ;
     RECT  83.269 85.824 83.408 96.024 ;
     RECT  82.573 97.056 83.408 97.56 ;
     RECT  82.033 98.88 83.408 99.24 ;
     RECT  82.609 100.32 83.408 102.936 ;
     RECT  81.173 105.408 83.408 105.432 ;
     RECT  83.408 2.148 83.512 41.16 ;
     RECT  83.408 75.048 83.512 127.452 ;
     RECT  83.512 2.418 83.704 41.16 ;
     RECT  83.512 75.264 83.704 127.182 ;
     RECT  83.704 81.456 83.837 81.48 ;
     RECT  83.704 102.096 83.837 102.792 ;
     RECT  83.704 87.072 83.843 92.28 ;
     RECT  83.704 93.504 83.873 95.736 ;
     RECT  83.704 98.928 83.945 99.24 ;
     RECT  83.704 84.336 84.025 85.896 ;
     RECT  83.704 97.536 84.089 97.56 ;
     RECT  83.704 100.224 84.161 101.064 ;
     RECT  84.161 100.32 84.449 101.064 ;
     RECT  84.025 84.96 84.557 85.896 ;
     RECT  83.843 87.072 84.629 89.496 ;
     RECT  83.843 90.624 84.665 92.28 ;
     RECT  84.665 90.624 84.908 91.176 ;
     RECT  84.629 87.168 84.949 89.496 ;
     RECT  84.908 90.576 84.949 91.176 ;
     RECT  84.949 87.168 84.997 91.176 ;
     RECT  83.873 93.504 85.021 94.44 ;
     RECT  83.873 95.424 85.021 95.736 ;
     RECT  83.837 102.096 85.021 102.648 ;
     RECT  85.021 93.504 85.025 95.736 ;
     RECT  85.021 102.048 85.165 102.648 ;
     RECT  85.165 102.048 85.313 103.08 ;
     RECT  84.997 88.08 85.421 91.176 ;
     RECT  85.421 88.08 85.493 90.6 ;
     RECT  85.313 102.048 85.493 102.072 ;
     RECT  84.557 85.392 85.525 85.896 ;
     RECT  85.493 88.08 85.565 89.256 ;
     RECT  85.561 96.96 85.597 96.984 ;
     RECT  85.525 85.392 85.717 85.944 ;
     RECT  85.025 93.84 85.777 95.736 ;
     RECT  85.597 96.96 85.813 97.512 ;
     RECT  83.945 98.928 85.813 99.192 ;
     RECT  84.449 100.752 85.813 101.064 ;
     RECT  85.813 96.96 85.985 99.192 ;
     RECT  85.813 100.608 85.985 101.064 ;
     RECT  85.717 85.392 86.005 86.232 ;
     RECT  85.313 103.056 86.005 103.08 ;
     RECT  83.704 104.256 86.005 104.28 ;
     RECT  86.005 103.056 86.051 104.28 ;
     RECT  85.985 96.96 86.069 101.064 ;
     RECT  86.051 103.056 86.105 103.368 ;
     RECT  86.069 97.008 86.249 101.064 ;
     RECT  85.777 93.84 86.285 95.928 ;
     RECT  85.993 92.688 86.304 92.712 ;
     RECT  86.249 97.008 86.393 97.032 ;
     RECT  86.105 103.344 86.393 103.368 ;
     RECT  86.317 91.632 86.641 91.656 ;
     RECT  86.249 98.064 86.645 101.064 ;
     RECT  86.641 91.632 86.677 91.752 ;
     RECT  86.677 90.528 86.681 91.752 ;
     RECT  86.285 93.84 86.681 94.92 ;
     RECT  85.565 88.08 86.717 89.208 ;
     RECT  86.005 85.392 86.789 86.664 ;
     RECT  86.681 90.528 86.789 90.696 ;
     RECT  86.789 90.528 86.825 90.552 ;
     RECT  86.645 99.168 87.02 101.064 ;
     RECT  87.02 99.168 87.107 101.544 ;
     RECT  87.107 99.168 87.113 101.064 ;
     RECT  86.681 94.896 87.365 94.92 ;
     RECT  86.681 91.728 87.401 91.752 ;
     RECT  87.073 93.504 87.577 93.528 ;
     RECT  86.717 88.08 87.685 88.44 ;
     RECT  87.113 99.888 87.725 101.064 ;
     RECT  86.645 98.064 87.757 98.088 ;
     RECT  87.685 88.08 87.781 89.112 ;
     RECT  87.577 96.912 87.781 96.936 ;
     RECT  87.757 98.064 87.781 98.424 ;
     RECT  87.781 88.08 87.827 89.976 ;
     RECT  87.827 88.08 87.833 88.44 ;
     RECT  87.827 89.952 87.98 89.976 ;
     RECT  83.704 39.744 88.808 41.16 ;
     RECT  83.704 75.264 88.808 75.48 ;
     RECT  83.704 82.992 88.808 83.016 ;
     RECT  86.789 85.392 88.808 86.232 ;
     RECT  87.833 88.416 88.808 88.44 ;
     RECT  87.98 89.952 88.808 90.744 ;
     RECT  87.577 93.024 88.808 93.528 ;
     RECT  88.652 94.608 88.808 94.632 ;
     RECT  88.369 95.76 88.808 95.784 ;
     RECT  87.781 96.912 88.808 98.424 ;
     RECT  87.725 100.32 88.808 101.064 ;
     RECT  88.808 2.148 88.912 41.16 ;
     RECT  88.808 75.048 88.912 127.452 ;
     RECT  88.912 2.418 89.104 41.16 ;
     RECT  88.912 75.264 89.104 127.182 ;
     RECT  89.104 75.264 93.013 75.48 ;
     RECT  89.104 39.744 94.208 41.16 ;
     RECT  93.013 74.928 94.208 75.48 ;
     RECT  89.104 82.992 94.208 83.016 ;
     RECT  89.104 85.392 94.208 86.232 ;
     RECT  89.104 88.416 94.208 88.44 ;
     RECT  89.104 101.04 94.208 101.064 ;
     RECT  94.208 2.148 94.312 41.16 ;
     RECT  94.208 74.928 94.312 127.452 ;
     RECT  94.312 2.418 94.504 41.16 ;
     RECT  94.312 74.928 94.504 127.182 ;
     RECT  94.504 88.416 95.105 88.44 ;
     RECT  94.504 101.04 96.611 101.064 ;
     RECT  96.565 94.032 96.613 94.056 ;
     RECT  96.613 88.896 96.697 88.92 ;
     RECT  96.613 93.936 96.755 94.056 ;
     RECT  94.504 39.744 99.608 41.16 ;
     RECT  94.504 74.928 99.608 75.288 ;
     RECT  94.504 82.992 99.608 83.016 ;
     RECT  94.504 85.392 99.608 86.232 ;
     RECT  96.755 94.032 99.608 94.056 ;
     RECT  99.608 2.148 99.712 41.16 ;
     RECT  99.608 74.928 99.712 127.452 ;
     RECT  99.712 2.418 99.904 41.16 ;
     RECT  99.712 74.928 99.904 127.182 ;
     RECT  99.904 39.744 105.008 41.16 ;
     RECT  99.904 74.928 105.008 75.288 ;
     RECT  99.904 82.992 105.008 83.016 ;
     RECT  99.904 85.392 105.008 86.232 ;
     RECT  99.904 94.032 105.008 94.056 ;
     RECT  105.008 2.148 105.112 41.16 ;
     RECT  105.008 74.928 105.112 127.452 ;
     RECT  105.112 2.418 105.304 41.16 ;
     RECT  105.112 74.928 105.304 127.182 ;
     RECT  105.304 39.744 110.408 41.16 ;
     RECT  105.304 74.928 110.408 75.288 ;
     RECT  105.304 82.992 110.408 83.016 ;
     RECT  105.304 85.392 110.408 86.232 ;
     RECT  105.304 94.032 110.408 94.056 ;
     RECT  110.408 2.148 110.512 41.16 ;
     RECT  110.408 74.928 110.512 127.452 ;
     RECT  110.512 2.418 110.704 41.16 ;
     RECT  110.512 74.928 110.704 127.182 ;
     RECT  110.704 85.392 111.161 86.232 ;
     RECT  110.704 94.032 111.305 94.056 ;
     RECT  110.704 39.744 112.385 41.16 ;
     RECT  111.161 85.392 112.835 86.04 ;
     RECT  112.777 93.504 112.861 93.528 ;
     RECT  112.385 40.56 113.461 41.16 ;
     RECT  113.461 39.744 115.808 41.16 ;
     RECT  110.704 74.928 115.808 75.288 ;
     RECT  112.693 80.496 115.808 80.52 ;
     RECT  110.704 82.992 115.808 83.016 ;
     RECT  112.835 85.392 115.808 85.416 ;
     RECT  115.808 2.148 115.912 41.16 ;
     RECT  115.808 74.928 115.912 127.452 ;
     RECT  115.912 2.418 116.104 41.16 ;
     RECT  115.912 74.928 116.104 127.182 ;
     RECT  116.104 39.744 121.208 41.16 ;
     RECT  116.104 74.928 121.208 75.288 ;
     RECT  116.104 80.496 121.208 80.52 ;
     RECT  116.104 82.992 121.208 83.016 ;
     RECT  116.104 85.392 121.208 85.416 ;
     RECT  121.208 2.148 121.312 41.16 ;
     RECT  121.208 74.928 121.312 127.452 ;
     RECT  121.312 2.418 121.504 41.16 ;
     RECT  121.312 74.928 121.504 127.182 ;
     RECT  121.504 74.928 126.529 75.288 ;
     RECT  121.504 39.744 126.608 41.16 ;
     RECT  126.529 74.928 126.608 75.48 ;
     RECT  121.504 80.496 126.608 80.52 ;
     RECT  121.504 82.992 126.608 83.016 ;
     RECT  121.504 85.392 126.608 85.416 ;
     RECT  126.608 2.148 126.712 41.16 ;
     RECT  126.608 74.928 126.712 127.452 ;
     RECT  126.712 2.418 126.904 41.16 ;
     RECT  126.712 74.928 126.904 127.182 ;
     RECT  126.904 74.928 128.441 75.48 ;
     RECT  128.441 75.264 128.477 75.48 ;
     RECT  128.477 75.264 128.765 75.288 ;
     RECT  126.904 80.496 130.547 80.52 ;
     RECT  126.904 85.392 131.893 85.416 ;
     RECT  126.904 39.744 132.008 41.16 ;
     RECT  130.501 79.2 132.008 79.224 ;
     RECT  131.713 80.928 132.008 80.952 ;
     RECT  126.904 82.992 132.008 83.016 ;
     RECT  131.893 85.392 132.008 85.512 ;
     RECT  132.008 2.148 132.112 41.16 ;
     RECT  132.008 75.048 132.112 127.452 ;
     RECT  132.112 2.418 132.304 41.16 ;
     RECT  132.112 75.318 132.304 127.182 ;
     RECT  132.304 85.488 132.401 85.656 ;
     RECT  132.304 82.992 133.333 83.016 ;
     RECT  133.333 82.992 134.867 83.784 ;
     RECT  132.304 39.744 137.408 41.16 ;
     RECT  132.304 79.152 137.408 79.176 ;
     RECT  134.867 82.992 137.408 83.016 ;
     RECT  132.401 85.632 137.408 85.656 ;
     RECT  137.408 2.148 137.512 41.16 ;
     RECT  137.408 75.048 137.512 127.452 ;
     RECT  137.512 2.418 137.704 41.16 ;
     RECT  137.512 75.318 137.704 127.182 ;
     RECT  137.704 85.632 142.513 85.656 ;
     RECT  137.704 39.744 142.808 41.16 ;
     RECT  137.704 79.152 142.808 79.176 ;
     RECT  137.704 82.992 142.808 83.016 ;
     RECT  142.513 85.632 142.808 85.752 ;
     RECT  142.369 91.344 142.808 91.368 ;
     RECT  142.808 2.148 142.912 41.16 ;
     RECT  142.808 75.048 142.912 127.452 ;
     RECT  142.912 2.418 143.104 41.16 ;
     RECT  142.912 75.318 143.104 127.182 ;
     RECT  143.104 82.992 143.273 83.784 ;
     RECT  143.273 83.76 144.611 83.784 ;
     RECT  143.104 78.096 144.925 78.12 ;
     RECT  144.925 77.76 144.965 78.12 ;
     RECT  143.104 91.344 145.177 91.368 ;
     RECT  145.177 91.2 145.331 91.368 ;
     RECT  144.965 77.76 145.333 77.784 ;
     RECT  143.104 85.728 145.469 85.752 ;
     RECT  145.333 76.896 145.757 77.784 ;
     RECT  143.104 79.152 145.765 79.176 ;
     RECT  145.757 77.76 145.811 77.784 ;
     RECT  145.724 85.584 145.811 85.608 ;
     RECT  145.285 88.224 145.901 88.248 ;
     RECT  145.331 91.2 146.396 91.224 ;
     RECT  143.104 39.744 146.473 41.16 ;
     RECT  146.396 91.2 146.483 91.512 ;
     RECT  146.833 87.792 146.917 87.816 ;
     RECT  145.765 79.152 146.945 79.752 ;
     RECT  146.473 39.744 148.208 41.256 ;
     RECT  147.98 76.512 148.208 76.536 ;
     RECT  146.945 79.152 148.208 79.272 ;
     RECT  146.483 91.2 148.208 91.224 ;
     RECT  146.437 93.504 148.208 93.528 ;
     RECT  148.208 2.148 148.312 41.256 ;
     RECT  148.208 75.048 148.312 127.452 ;
     RECT  148.312 2.418 148.504 41.256 ;
     RECT  148.312 75.318 148.504 127.182 ;
     RECT  148.504 39.744 148.835 41.256 ;
     RECT  148.504 93.504 149.363 93.528 ;
     RECT  148.835 39.744 153.608 41.112 ;
     RECT  148.504 79.152 153.608 79.176 ;
     RECT  153.608 2.148 153.712 41.112 ;
     RECT  153.608 75.048 153.712 127.452 ;
     RECT  153.712 2.418 153.904 41.112 ;
     RECT  153.712 75.318 153.904 127.182 ;
     RECT  153.904 39.744 159.008 41.112 ;
     RECT  153.904 79.152 159.008 79.176 ;
     RECT  159.008 2.148 159.112 41.112 ;
     RECT  159.008 75.048 159.112 127.452 ;
     RECT  159.112 2.418 159.304 41.112 ;
     RECT  159.112 75.318 159.304 127.182 ;
     RECT  159.304 39.744 162.457 41.112 ;
     RECT  162.457 39.744 164.408 41.208 ;
     RECT  159.304 79.152 164.408 79.176 ;
     RECT  164.408 2.148 164.512 41.208 ;
     RECT  164.408 75.048 164.512 127.452 ;
     RECT  164.512 2.418 164.704 41.208 ;
     RECT  164.512 75.318 164.704 127.182 ;
     RECT  164.704 39.744 164.819 41.208 ;
     RECT  164.819 39.744 169.808 41.016 ;
     RECT  164.704 79.152 169.808 79.176 ;
     RECT  169.808 2.148 169.912 41.052 ;
     RECT  169.808 75.048 169.912 127.452 ;
     RECT  169.912 2.418 170.104 41.016 ;
     RECT  169.912 75.318 170.104 127.182 ;
     RECT  170.104 39.744 175.208 41.016 ;
     RECT  170.104 79.152 175.208 79.176 ;
     RECT  175.208 2.148 175.312 41.052 ;
     RECT  175.208 75.048 175.312 127.452 ;
     RECT  175.312 2.418 175.504 41.016 ;
     RECT  175.312 75.318 175.504 127.182 ;
     RECT  175.504 39.744 180.608 41.016 ;
     RECT  175.504 79.152 180.608 79.176 ;
     RECT  180.608 2.148 180.712 41.052 ;
     RECT  180.608 75.048 180.712 127.452 ;
     RECT  180.712 2.418 180.904 41.016 ;
     RECT  180.712 75.318 180.904 127.182 ;
     RECT  180.904 39.744 182.837 41.016 ;
     RECT  58.403 42.432 183.593 72.936 ;
     RECT  182.837 40.992 184.889 41.016 ;
     RECT  182.837 39.744 186.008 39.768 ;
     RECT  180.904 79.152 186.008 79.176 ;
     RECT  186.008 2.148 186.112 41.052 ;
     RECT  186.008 75.048 186.112 127.452 ;
     RECT  186.112 2.418 186.304 40.782 ;
     RECT  186.112 75.318 186.304 127.182 ;
     RECT  186.304 39.744 191.408 39.768 ;
     RECT  186.304 79.152 191.408 79.176 ;
     RECT  191.408 2.148 191.512 41.052 ;
     RECT  191.408 75.048 191.512 127.452 ;
     RECT  191.512 2.418 191.704 40.782 ;
     RECT  191.512 75.318 191.704 127.182 ;
     RECT  191.704 39.744 196.808 39.768 ;
     RECT  191.704 79.152 196.808 79.176 ;
     RECT  196.808 2.148 196.912 41.052 ;
     RECT  196.808 75.048 196.912 127.452 ;
     RECT  196.912 2.418 197.104 40.782 ;
     RECT  196.912 75.318 197.104 127.182 ;
     RECT  197.104 39.744 202.208 39.768 ;
     RECT  197.104 79.152 202.208 79.176 ;
     RECT  202.208 2.148 202.312 41.052 ;
     RECT  202.208 75.048 202.312 127.452 ;
     RECT  202.312 2.418 202.504 40.782 ;
     RECT  202.312 75.318 202.504 127.182 ;
     RECT  202.504 39.744 207.608 39.768 ;
     RECT  202.504 79.152 207.608 79.176 ;
     RECT  207.608 2.148 207.712 41.052 ;
     RECT  207.608 75.048 207.712 127.452 ;
     RECT  207.712 2.418 207.904 40.782 ;
     RECT  207.712 75.318 207.904 127.182 ;
     RECT  207.904 39.744 213.008 39.768 ;
     RECT  207.904 79.152 213.008 79.176 ;
     RECT  213.008 2.148 213.112 41.052 ;
     RECT  213.008 75.048 213.112 127.452 ;
     RECT  213.112 2.418 213.304 40.782 ;
     RECT  213.112 75.318 213.304 127.182 ;
     RECT  183.593 43.2 217.248 72.936 ;
     RECT  217.248 43.968 217.757 64.824 ;
     RECT  213.304 39.744 218.408 39.768 ;
     RECT  213.304 79.152 218.408 79.176 ;
     RECT  217.757 48 218.477 59.832 ;
     RECT  218.408 2.148 218.512 41.052 ;
     RECT  218.408 75.048 218.512 127.452 ;
     RECT  218.512 2.418 218.704 40.782 ;
     RECT  218.512 75.318 218.704 127.182 ;
     RECT  218.477 48 218.909 58.776 ;
     RECT  217.757 60.864 218.909 64.824 ;
     RECT  217.757 43.968 219.413 46.968 ;
     RECT  219.413 43.968 219.449 46.776 ;
     RECT  218.909 48.096 219.449 58.776 ;
     RECT  218.909 60.864 219.449 63.384 ;
     RECT  218.909 64.512 219.485 64.824 ;
     RECT  219.449 50.016 219.557 58.68 ;
     RECT  219.485 64.512 219.557 64.632 ;
     RECT  219.557 51.168 219.593 58.68 ;
     RECT  219.593 54.24 219.629 54.264 ;
     RECT  219.449 44.448 219.665 44.856 ;
     RECT  219.593 51.552 219.665 53.112 ;
     RECT  219.593 55.392 219.665 58.68 ;
     RECT  219.449 60.864 219.665 63.288 ;
     RECT  219.665 51.552 219.737 52.92 ;
     RECT  219.665 58.08 219.737 58.68 ;
     RECT  219.665 60.864 219.737 62.664 ;
     RECT  219.737 51.552 219.773 52.44 ;
     RECT  219.665 56.832 219.773 56.952 ;
     RECT  218.477 59.808 219.773 59.832 ;
     RECT  219.737 60.864 219.773 62.136 ;
     RECT  219.773 52.32 219.809 52.44 ;
     RECT  219.773 60.96 219.809 62.136 ;
     RECT  219.809 52.416 219.953 52.44 ;
     RECT  219.665 55.392 219.953 55.704 ;
     RECT  219.809 60.96 219.953 61.848 ;
     RECT  219.557 64.512 219.953 64.536 ;
     RECT  219.953 55.68 219.989 55.704 ;
     RECT  219.773 56.928 219.989 56.952 ;
     RECT  219.953 61.824 219.989 61.848 ;
     RECT  219.877 42.864 220.025 42.888 ;
     RECT  219.449 46.032 220.025 46.056 ;
     RECT  219.665 44.832 220.313 44.856 ;
     RECT  218.704 39.744 223.808 39.768 ;
     RECT  218.704 79.152 223.808 79.176 ;
     RECT  223.808 2.148 223.912 127.452 ;
     RECT  223.912 2.418 224.104 127.182 ;
     RECT  224.104 39.744 229.208 39.768 ;
     RECT  224.104 79.152 229.208 79.176 ;
     RECT  229.208 2.148 229.312 127.452 ;
     RECT  229.312 2.418 229.504 127.182 ;
     RECT  229.504 39.744 234.608 39.768 ;
     RECT  229.504 79.152 234.608 79.176 ;
     RECT  234.608 2.148 234.712 127.452 ;
     RECT  234.712 2.418 234.904 127.182 ;
     RECT  234.904 39.744 240.008 39.768 ;
     RECT  234.904 79.152 240.008 79.176 ;
     RECT  240.008 2.148 240.112 127.452 ;
     RECT  240.112 2.418 240.304 127.182 ;
     RECT  240.304 39.744 245.408 39.768 ;
     RECT  240.304 79.152 245.408 79.176 ;
     RECT  245.408 2.148 245.512 127.452 ;
     RECT  245.512 2.418 245.704 127.182 ;
     RECT  245.704 79.152 250.225 79.176 ;
     RECT  249.757 46.608 250.693 46.632 ;
     RECT  250.693 46.32 250.765 46.632 ;
     RECT  245.704 39.744 250.808 39.768 ;
     RECT  249.721 45.168 250.808 45.192 ;
     RECT  250.765 46.32 250.808 46.824 ;
     RECT  250.549 48.768 250.808 48.792 ;
     RECT  250.225 79.008 250.808 79.176 ;
     RECT  250.808 2.148 250.912 127.452 ;
     RECT  250.912 2.418 251.104 127.182 ;
     RECT  251.104 48.432 251.219 48.792 ;
     RECT  251.219 48.528 252.173 48.792 ;
     RECT  251.104 39.744 252.277 40.584 ;
     RECT  252.173 48.768 252.277 48.792 ;
     RECT  251.104 45.168 252.284 47.352 ;
     RECT  252.284 45.168 252.371 47.592 ;
     RECT  251.104 79.008 252.371 79.032 ;
     RECT  252.332 43.872 252.419 43.896 ;
     RECT  252.371 45.168 252.419 47.352 ;
     RECT  252.419 45.168 252.497 47.16 ;
     RECT  252.277 39.6 252.563 40.584 ;
     RECT  252.517 43.728 252.677 43.752 ;
     RECT  252.277 48.768 252.929 48.84 ;
     RECT  252.497 45.168 253.325 46.776 ;
     RECT  252.563 39.6 253.973 39.768 ;
     RECT  253.325 46.272 254.117 46.776 ;
     RECT  252.929 48.816 254.117 48.84 ;
     RECT  253.325 45.168 254.333 45.192 ;
     RECT  254.117 46.752 254.549 46.776 ;
     RECT  255.085 46.896 255.193 46.92 ;
     RECT  255.193 46.896 255.769 47.352 ;
     RECT  255.769 46.896 255.949 47.4 ;
     RECT  255.949 46.608 256.165 47.4 ;
     RECT  253.973 39.744 256.208 39.768 ;
     RECT  256.165 46.608 256.208 47.448 ;
     RECT  256.208 2.148 256.312 127.452 ;
     RECT  256.312 2.418 256.504 127.182 ;
     RECT  256.504 46.416 257.569 48.264 ;
     RECT  257.569 45.456 257.605 48.264 ;
     RECT  256.504 39.12 258.181 39.24 ;
     RECT  257.605 45.36 258.253 48.264 ;
     RECT  258.181 39.12 259.116 39.144 ;
     RECT  258.181 39.144 259.164 39.216 ;
     RECT  258.181 39.216 259.116 39.24 ;
     RECT  258.181 39.24 259.164 39.312 ;
     RECT  258.181 39.312 259.116 39.336 ;
     RECT  258.181 39.336 259.164 39.408 ;
     RECT  258.181 39.408 259.116 39.432 ;
     RECT  258.253 45.264 259.116 45.288 ;
     RECT  258.253 45.288 259.164 45.36 ;
     RECT  258.253 45.36 259.116 45.384 ;
     RECT  258.253 45.384 259.164 45.456 ;
     RECT  258.253 45.456 259.116 45.48 ;
     RECT  258.253 45.48 259.164 45.552 ;
     RECT  258.253 45.552 259.116 45.576 ;
     RECT  258.253 45.576 259.164 45.648 ;
     RECT  258.253 45.648 259.116 45.672 ;
     RECT  258.253 45.672 259.164 45.744 ;
     RECT  258.253 45.744 259.116 45.768 ;
     RECT  258.253 45.768 259.164 45.84 ;
     RECT  258.253 45.84 259.116 45.864 ;
     RECT  258.253 45.864 259.164 45.936 ;
     RECT  258.253 45.936 259.116 45.96 ;
     RECT  258.253 45.96 259.164 46.032 ;
     RECT  258.253 46.032 259.116 46.056 ;
     RECT  258.253 46.056 259.164 46.128 ;
     RECT  258.253 46.128 259.116 46.152 ;
     RECT  258.253 46.152 259.164 46.224 ;
     RECT  258.253 46.224 259.116 46.248 ;
     RECT  258.253 46.248 259.164 46.32 ;
     RECT  258.253 46.32 259.116 46.344 ;
     RECT  258.253 46.344 259.164 46.416 ;
     RECT  258.253 46.416 259.116 46.44 ;
     RECT  258.253 46.44 259.164 46.512 ;
     RECT  258.253 46.512 259.116 46.536 ;
     RECT  258.253 46.536 259.164 46.608 ;
     RECT  258.253 46.608 259.116 46.632 ;
     RECT  258.253 46.632 259.164 46.704 ;
     RECT  258.253 46.704 259.116 46.728 ;
     RECT  258.253 46.728 259.164 46.8 ;
     RECT  258.253 46.8 259.116 46.824 ;
     RECT  258.253 46.824 259.164 46.896 ;
     RECT  258.253 46.896 259.116 46.92 ;
     RECT  258.253 46.92 259.164 46.992 ;
     RECT  258.253 46.992 259.116 47.016 ;
     RECT  258.253 47.016 259.164 47.088 ;
     RECT  258.253 47.088 259.116 47.112 ;
     RECT  258.253 47.112 259.164 47.184 ;
     RECT  258.253 47.184 259.116 47.208 ;
     RECT  258.253 47.208 259.164 47.28 ;
     RECT  258.253 47.28 259.116 47.304 ;
     RECT  258.253 47.304 259.164 47.376 ;
     RECT  258.253 47.376 259.116 47.4 ;
     RECT  258.253 47.4 259.164 47.472 ;
     RECT  258.253 47.472 259.116 47.496 ;
     RECT  258.253 47.496 259.164 47.568 ;
     RECT  258.253 47.568 259.116 47.592 ;
     RECT  258.253 47.592 259.164 47.664 ;
     RECT  258.253 47.664 259.116 47.688 ;
     RECT  258.253 47.688 259.164 47.76 ;
     RECT  258.253 47.76 259.116 47.784 ;
     RECT  258.253 47.784 259.164 47.856 ;
     RECT  258.253 47.856 259.116 47.88 ;
     RECT  258.253 47.88 259.164 47.952 ;
     RECT  258.253 47.952 259.116 47.976 ;
     RECT  258.253 47.976 259.164 48.048 ;
     RECT  258.253 48.048 259.116 48.072 ;
     RECT  258.253 48.072 259.164 48.144 ;
     RECT  258.253 48.144 259.116 48.168 ;
     RECT  258.253 48.168 259.164 48.24 ;
     RECT  258.253 48.24 259.116 48.264 ;
    LAYER M5 ;
     RECT  68.52 0.016 68.592 0.084 ;
     RECT  68.496 0.084 68.616 0.611 ;
     RECT  2.4 2.137 2.52 2.151 ;
     RECT  7.8 2.137 7.92 2.151 ;
     RECT  13.2 2.137 13.32 2.151 ;
     RECT  18.6 2.137 18.72 2.151 ;
     RECT  24 2.137 24.12 2.151 ;
     RECT  29.4 2.137 29.52 2.151 ;
     RECT  34.8 2.137 34.92 2.151 ;
     RECT  40.2 2.137 40.32 2.151 ;
     RECT  45.6 2.137 45.72 2.151 ;
     RECT  51 2.137 51.12 2.151 ;
     RECT  56.4 2.137 56.52 2.151 ;
     RECT  61.8 2.137 61.92 2.151 ;
     RECT  67.2 2.137 67.32 2.151 ;
     RECT  72.6 2.137 72.72 2.151 ;
     RECT  78 2.137 78.12 2.151 ;
     RECT  83.4 2.137 83.52 2.151 ;
     RECT  88.8 2.137 88.92 2.151 ;
     RECT  94.2 2.137 94.32 2.151 ;
     RECT  99.6 2.137 99.72 2.151 ;
     RECT  105 2.137 105.12 2.151 ;
     RECT  110.4 2.137 110.52 2.151 ;
     RECT  115.8 2.137 115.92 2.151 ;
     RECT  121.2 2.137 121.32 2.151 ;
     RECT  126.6 2.137 126.72 2.151 ;
     RECT  132 2.137 132.12 2.151 ;
     RECT  137.4 2.137 137.52 2.151 ;
     RECT  142.8 2.137 142.92 2.151 ;
     RECT  148.2 2.137 148.32 2.151 ;
     RECT  153.6 2.137 153.72 2.151 ;
     RECT  159 2.137 159.12 2.151 ;
     RECT  164.4 2.137 164.52 2.151 ;
     RECT  169.8 2.137 169.92 2.151 ;
     RECT  175.2 2.137 175.32 2.151 ;
     RECT  180.6 2.137 180.72 2.151 ;
     RECT  186 2.137 186.12 2.151 ;
     RECT  191.4 2.137 191.52 2.151 ;
     RECT  196.8 2.137 196.92 2.151 ;
     RECT  202.2 2.137 202.32 2.151 ;
     RECT  207.6 2.137 207.72 2.151 ;
     RECT  213 2.137 213.12 2.151 ;
     RECT  218.4 2.137 218.52 2.151 ;
     RECT  223.8 2.137 223.92 2.151 ;
     RECT  229.2 2.137 229.32 2.151 ;
     RECT  234.6 2.137 234.72 2.151 ;
     RECT  240 2.137 240.12 2.151 ;
     RECT  245.4 2.137 245.52 2.151 ;
     RECT  250.8 2.137 250.92 2.151 ;
     RECT  256.2 2.137 256.32 2.151 ;
     RECT  67.2 2.151 67.512 3.349 ;
     RECT  68.496 0.611 68.52 3.349 ;
     RECT  61.8 2.151 62.112 5.605 ;
     RECT  67.2 3.349 68.52 5.653 ;
     RECT  61.8 5.605 62.28 10.883 ;
     RECT  59.04 11.221 59.064 16.019 ;
     RECT  56.4 2.151 56.712 16.357 ;
     RECT  67.2 5.653 68.664 16.691 ;
     RECT  55.872 16.357 56.712 21.155 ;
     RECT  52.752 21.589 52.776 26.819 ;
     RECT  49.536 27.109 49.56 31.955 ;
     RECT  45.6 2.151 45.912 32.437 ;
     RECT  45.6 32.437 46.44 37.667 ;
     RECT  43.296 38.149 43.32 38.773 ;
     RECT  43.2 38.773 43.32 38.819 ;
     RECT  58.512 16.261 58.536 39.445 ;
     RECT  40.2 2.151 40.512 39.733 ;
     RECT  58.512 39.445 58.68 40.067 ;
     RECT  58.512 40.067 58.536 40.405 ;
     RECT  148.2 2.151 148.512 40.405 ;
     RECT  40.2 39.733 41.016 40.499 ;
     RECT  43.2 38.819 43.224 40.499 ;
     RECT  58.176 40.405 58.536 40.499 ;
     RECT  45.6 37.667 45.912 40.597 ;
     RECT  56.4 21.155 56.712 40.597 ;
     RECT  38.496 40.021 38.52 40.837 ;
     RECT  61.8 10.883 62.112 40.837 ;
     RECT  147.408 40.405 148.512 40.837 ;
     RECT  45.6 40.597 46.104 40.883 ;
     RECT  82.32 16.405 82.344 40.883 ;
     RECT  40.2 40.499 40.872 40.885 ;
     RECT  70.704 40.645 70.728 40.931 ;
     RECT  44.496 40.837 44.52 40.933 ;
     RECT  146.496 40.837 148.824 40.933 ;
     RECT  146.496 40.933 148.872 40.979 ;
     RECT  146.88 40.979 148.872 40.981 ;
     RECT  164.4 2.151 164.712 40.981 ;
     RECT  164.4 40.981 164.808 41.219 ;
     RECT  43.104 40.693 43.128 42.421 ;
     RECT  61.8 40.837 62.232 42.515 ;
     RECT  40.08 40.885 40.872 42.517 ;
     RECT  56.4 40.597 57.048 42.563 ;
     RECT  44.448 40.933 44.52 42.611 ;
     RECT  40.08 42.517 40.968 42.661 ;
     RECT  53.808 40.549 53.832 42.757 ;
     RECT  44.496 42.611 44.52 43.043 ;
     RECT  252.528 39.589 252.552 43.763 ;
     RECT  42.432 42.421 43.128 44.723 ;
     RECT  40.08 42.661 41.016 45.059 ;
     RECT  250.8 2.151 251.112 47.317 ;
     RECT  40.2 45.059 41.016 47.363 ;
     RECT  252.384 43.861 252.408 47.363 ;
     RECT  42.432 44.723 42.456 47.939 ;
     RECT  40.2 47.363 40.92 48.515 ;
     RECT  250.8 47.317 251.208 48.803 ;
     RECT  37.872 40.837 38.52 49.525 ;
     RECT  37.2 49.525 38.52 49.619 ;
     RECT  37.2 49.619 37.896 49.909 ;
     RECT  36.72 49.909 37.896 50.339 ;
     RECT  40.2 48.515 40.728 51.109 ;
     RECT  36.72 50.339 36.744 51.493 ;
     RECT  37.872 50.339 37.896 51.493 ;
     RECT  36.72 51.493 37.896 54.227 ;
     RECT  0.144 54.901 0.168 55.187 ;
     RECT  37.44 54.227 37.896 55.187 ;
     RECT  25.584 55.237 25.608 55.715 ;
     RECT  37.872 55.187 37.896 56.389 ;
     RECT  39.312 51.109 40.728 56.917 ;
     RECT  5.136 55.813 5.16 57.059 ;
     RECT  37.872 56.389 38.088 57.059 ;
     RECT  39.168 56.917 40.728 57.059 ;
     RECT  38.064 57.059 38.088 57.299 ;
     RECT  29.4 2.151 29.712 59.077 ;
     RECT  27.024 55.669 27.048 59.315 ;
     RECT  39.168 57.059 39.192 59.461 ;
     RECT  29.4 59.077 30.6 59.507 ;
     RECT  33.648 54.709 33.672 59.507 ;
     RECT  43.104 59.461 43.128 59.701 ;
     RECT  42.96 59.701 43.128 59.843 ;
     RECT  5.952 57.541 5.976 59.989 ;
     RECT  38.784 59.461 39.192 60.035 ;
     RECT  5.952 59.989 6.264 60.085 ;
     RECT  5.904 60.085 6.264 60.131 ;
     RECT  36.768 55.813 36.792 60.467 ;
     RECT  40.2 57.059 40.728 60.515 ;
     RECT  39.168 60.035 39.192 62.195 ;
     RECT  36.864 60.661 36.888 62.291 ;
     RECT  42.72 62.677 42.744 62.867 ;
     RECT  5.904 60.131 5.928 64.789 ;
     RECT  5.04 64.789 5.928 64.835 ;
     RECT  18.6 2.151 18.912 64.837 ;
     RECT  39.024 63.541 39.048 65.027 ;
     RECT  37.536 67.141 37.56 67.765 ;
     RECT  24 2.151 24.312 69.829 ;
     RECT  24 69.829 24.552 70.549 ;
     RECT  17.904 64.837 18.912 70.645 ;
     RECT  23.568 70.549 24.552 70.739 ;
     RECT  16.224 69.493 16.248 70.837 ;
     RECT  23.568 70.739 24.312 71.077 ;
     RECT  29.4 59.507 29.712 71.173 ;
     RECT  21.696 70.837 21.72 71.651 ;
     RECT  26.736 71.509 26.76 71.749 ;
     RECT  28.608 71.173 29.712 71.939 ;
     RECT  23.136 71.077 24.312 71.987 ;
     RECT  34.8 2.151 35.112 71.989 ;
     RECT  37.536 67.765 37.608 72.035 ;
     RECT  34.8 71.989 36.024 72.371 ;
     RECT  15.36 70.837 16.248 72.467 ;
     RECT  20.496 71.797 20.52 72.467 ;
     RECT  40.2 60.515 40.512 72.709 ;
     RECT  13.2 2.151 13.512 72.805 ;
     RECT  23.568 71.987 24.312 73.043 ;
     RECT  17.904 70.645 19.032 73.235 ;
     RECT  39.552 72.709 40.512 73.235 ;
     RECT  15.552 72.467 16.248 73.283 ;
     RECT  26.208 71.749 26.76 73.331 ;
     RECT  58.176 40.499 58.2 73.477 ;
     RECT  58.176 73.477 58.392 73.523 ;
     RECT  16.224 73.283 16.248 73.765 ;
     RECT  32.736 72.901 32.76 74.101 ;
     RECT  12.528 72.805 13.512 74.147 ;
     RECT  17.904 73.235 18.912 74.147 ;
     RECT  10.8 74.053 10.824 74.675 ;
     RECT  16.224 73.765 16.584 74.723 ;
     RECT  53.808 42.757 54.456 74.723 ;
     RECT  34.8 72.371 35.112 74.869 ;
     RECT  94.2 2.151 94.512 75.157 ;
     RECT  34.176 74.869 35.112 75.251 ;
     RECT  72.6 2.151 72.912 75.253 ;
     RECT  21.072 73.765 21.096 75.299 ;
     RECT  68.64 16.691 68.664 75.299 ;
     RECT  72.6 75.253 73.032 75.301 ;
     RECT  60.528 75.205 60.552 75.445 ;
     RECT  61.8 42.515 62.112 75.445 ;
     RECT  72.096 75.301 73.032 75.445 ;
     RECT  40.2 73.235 40.512 75.493 ;
     RECT  70.08 75.349 70.728 75.587 ;
     RECT  63.696 39.877 63.72 75.683 ;
     RECT  67.2 16.691 67.512 75.685 ;
     RECT  72.096 75.445 73.128 75.779 ;
     RECT  53.808 74.723 53.832 75.781 ;
     RECT  60.528 75.445 62.112 75.781 ;
     RECT  74.112 40.405 74.136 75.781 ;
     RECT  53.808 75.781 53.976 75.827 ;
     RECT  66.672 75.685 67.512 76.069 ;
     RECT  31.92 74.101 32.76 76.259 ;
     RECT  19.968 73.477 19.992 76.307 ;
     RECT  26.736 73.331 26.76 76.357 ;
     RECT  44.448 75.397 44.472 76.403 ;
     RECT  70.08 75.587 70.2 76.549 ;
     RECT  68.544 76.549 68.568 76.741 ;
     RECT  72.096 75.779 72.912 76.787 ;
     RECT  74.112 75.781 74.904 76.835 ;
     RECT  144.576 40.981 144.6 76.885 ;
     RECT  58.368 73.523 58.392 76.933 ;
     RECT  58.368 76.933 58.632 76.979 ;
     RECT  70.08 76.549 70.536 76.979 ;
     RECT  13.2 74.147 13.512 77.125 ;
     RECT  40.2 75.493 41.064 77.125 ;
     RECT  26.592 76.357 26.76 77.171 ;
     RECT  37.584 72.035 37.608 77.171 ;
     RECT  21.312 76.885 21.336 77.411 ;
     RECT  27.936 75.205 27.96 77.555 ;
     RECT  60.528 75.781 62.664 77.557 ;
     RECT  53.952 75.827 53.976 77.653 ;
     RECT  144.576 76.885 145.368 77.749 ;
     RECT  144.576 77.749 145.8 77.795 ;
     RECT  39.984 77.125 41.064 77.941 ;
     RECT  60.528 77.557 62.712 78.037 ;
     RECT  36.192 77.557 36.216 78.371 ;
     RECT  39.984 77.941 41.16 78.373 ;
     RECT  13.2 77.125 14.136 78.421 ;
     RECT  66.432 76.069 67.512 78.421 ;
     RECT  42.864 76.261 42.888 78.517 ;
     RECT  45.6 40.883 45.912 78.517 ;
     RECT  32.736 76.259 32.76 78.565 ;
     RECT  16.56 74.723 16.584 78.613 ;
     RECT  18.096 74.147 18.912 78.613 ;
     RECT  24 73.043 24.312 78.613 ;
     RECT  26.736 77.171 26.76 78.613 ;
     RECT  56.4 42.563 56.712 78.613 ;
     RECT  70.176 76.979 70.536 78.613 ;
     RECT  76.176 78.085 76.2 78.613 ;
     RECT  16.56 78.613 19.656 78.659 ;
     RECT  53.952 77.653 54.408 78.659 ;
     RECT  66.192 78.421 67.512 78.661 ;
     RECT  39.984 78.373 41.208 78.707 ;
     RECT  82.08 77.461 82.104 78.707 ;
     RECT  65.808 78.661 67.512 78.803 ;
     RECT  70.176 78.613 70.728 78.901 ;
     RECT  78 2.151 78.312 78.901 ;
     RECT  52.896 77.653 52.92 78.947 ;
     RECT  252.336 47.557 252.36 79.043 ;
     RECT  13.2 78.421 15.096 79.045 ;
     RECT  42.864 78.517 43.224 79.045 ;
     RECT  60.096 78.037 62.712 79.045 ;
     RECT  20.976 78.613 21 79.139 ;
     RECT  83.4 2.151 83.712 79.141 ;
     RECT  48.672 78.085 48.696 79.187 ;
     RECT  76.08 78.613 76.2 79.187 ;
     RECT  10.416 78.661 10.44 79.189 ;
     RECT  58.608 76.979 58.632 79.189 ;
     RECT  10.416 79.189 11.064 79.235 ;
     RECT  42.144 79.045 43.224 79.285 ;
     RECT  68.496 76.741 68.568 79.333 ;
     RECT  45.264 78.517 45.912 79.475 ;
     RECT  60.096 79.045 62.904 79.477 ;
     RECT  74.112 76.835 74.136 79.477 ;
     RECT  60.096 79.477 62.952 79.619 ;
     RECT  32.064 78.565 32.76 79.621 ;
     RECT  24 78.613 25.128 79.715 ;
     RECT  26.208 78.613 26.76 79.715 ;
     RECT  32.064 79.621 33.432 79.717 ;
     RECT  34.8 75.251 35.112 79.717 ;
     RECT  32.064 79.717 35.112 79.765 ;
     RECT  56.112 78.613 56.712 79.765 ;
     RECT  72.6 76.787 72.912 79.765 ;
     RECT  68.496 79.333 68.616 79.811 ;
     RECT  70.176 78.901 70.968 79.813 ;
     RECT  29.4 71.939 29.712 80.053 ;
     RECT  31.104 79.765 35.112 80.053 ;
     RECT  42.144 79.285 43.416 80.101 ;
     RECT  69.792 79.813 70.968 80.149 ;
     RECT  72.096 79.765 72.912 80.149 ;
     RECT  16.992 78.659 19.656 80.291 ;
     RECT  29.4 80.053 35.112 80.291 ;
     RECT  42.144 80.101 44.328 80.291 ;
     RECT  22.368 79.621 22.392 80.339 ;
     RECT  66.432 78.803 67.512 80.341 ;
     RECT  68.496 79.811 68.568 80.341 ;
     RECT  80.16 78.517 80.184 80.341 ;
     RECT  28.128 79.189 28.152 80.389 ;
     RECT  60.096 79.619 62.904 80.389 ;
     RECT  37.488 79.717 37.512 80.435 ;
     RECT  74.112 79.477 74.712 80.435 ;
     RECT  11.04 79.235 11.064 80.483 ;
     RECT  66.432 80.341 68.568 80.483 ;
     RECT  26.208 79.715 26.232 80.531 ;
     RECT  130.512 79.189 130.536 80.531 ;
     RECT  20.928 79.189 20.952 80.579 ;
     RECT  74.688 80.435 74.712 80.579 ;
     RECT  58.176 79.189 58.632 80.675 ;
     RECT  42.864 80.291 44.328 80.773 ;
     RECT  45.6 79.475 45.912 80.773 ;
     RECT  59.904 80.389 62.904 80.773 ;
     RECT  80.16 80.341 80.568 80.819 ;
     RECT  24 79.715 24.312 80.821 ;
     RECT  76.08 79.187 76.104 80.821 ;
     RECT  16.992 80.291 18.912 80.867 ;
     RECT  5.04 64.835 5.064 80.917 ;
     RECT  27.888 80.389 28.152 80.917 ;
     RECT  29.4 80.291 33.432 80.917 ;
     RECT  55.248 79.765 56.712 80.917 ;
     RECT  132 2.151 132.312 80.917 ;
     RECT  5.04 80.917 5.4 80.963 ;
     RECT  76.08 80.821 76.968 80.963 ;
     RECT  39.984 78.707 41.16 80.965 ;
     RECT  16.992 80.867 17.016 81.011 ;
     RECT  59.616 80.773 62.904 81.011 ;
     RECT  82.08 80.245 82.104 81.011 ;
     RECT  68.496 80.483 68.568 81.013 ;
     RECT  69.792 80.149 72.912 81.013 ;
     RECT  58.176 80.675 58.584 81.059 ;
     RECT  24 80.821 25.176 81.157 ;
     RECT  34.8 80.291 35.112 81.157 ;
     RECT  23.184 81.157 25.176 81.205 ;
     RECT  34.8 81.157 35.208 81.205 ;
     RECT  36.384 78.517 36.408 81.205 ;
     RECT  42.864 80.773 45.912 81.205 ;
     RECT  27.888 80.917 33.432 81.349 ;
     RECT  34.8 81.205 36.408 81.349 ;
     RECT  68.496 81.013 72.912 81.395 ;
     RECT  68.496 81.395 68.568 81.443 ;
     RECT  39.984 80.965 41.256 81.445 ;
     RECT  59.616 81.011 60.552 81.539 ;
     RECT  68.496 81.443 68.52 81.539 ;
     RECT  51 2.151 51.312 81.589 ;
     RECT  39.072 81.445 41.256 81.685 ;
     RECT  55.248 80.917 57 81.731 ;
     RECT  20.64 81.733 20.808 82.021 ;
     RECT  66.432 80.483 67.512 82.115 ;
     RECT  27.888 81.349 36.408 82.117 ;
     RECT  50.736 81.589 51.312 82.211 ;
     RECT  18.48 80.867 18.912 82.261 ;
     RECT  23.184 81.205 25.464 82.357 ;
     RECT  76.08 80.963 76.104 82.405 ;
     RECT  6.624 81.685 6.648 82.451 ;
     RECT  56.4 81.731 57 82.451 ;
     RECT  12.816 79.045 15.096 82.453 ;
     RECT  69.648 81.395 72.912 82.453 ;
     RECT  61.584 81.011 62.904 82.501 ;
     RECT  61.584 82.501 63.096 82.547 ;
     RECT  12.528 82.453 15.096 82.549 ;
     RECT  39.072 81.685 41.736 82.549 ;
     RECT  23.04 82.357 26.328 82.595 ;
     RECT  61.68 82.547 63.096 82.595 ;
     RECT  23.04 82.595 25.56 82.597 ;
     RECT  27.792 82.117 36.408 82.597 ;
     RECT  16.752 82.309 16.776 82.643 ;
     RECT  18.336 82.261 19.176 82.645 ;
     RECT  59.616 81.539 60.36 82.691 ;
     RECT  38.64 82.549 41.736 82.693 ;
     RECT  42.864 81.205 46.728 82.693 ;
     RECT  22.944 82.597 25.56 82.739 ;
     RECT  55.248 81.731 55.272 82.835 ;
     RECT  23.52 82.739 25.56 82.883 ;
     RECT  23.52 82.883 25.176 82.931 ;
     RECT  17.088 82.645 19.176 82.979 ;
     RECT  38.64 82.693 46.728 82.979 ;
     RECT  59.616 82.691 60.12 82.979 ;
     RECT  78 78.901 78.648 82.981 ;
     RECT  80.16 80.819 80.328 82.981 ;
     RECT  9.936 81.829 9.96 83.029 ;
     RECT  9.936 83.029 10.44 83.125 ;
     RECT  11.808 82.549 15.096 83.125 ;
     RECT  20.64 82.021 21.624 83.171 ;
     RECT  23.52 82.931 25.128 83.171 ;
     RECT  27.696 82.597 36.408 83.173 ;
     RECT  27.504 83.173 36.408 83.221 ;
     RECT  76.08 82.405 76.2 83.221 ;
     RECT  17.664 82.979 19.176 83.267 ;
     RECT  52.56 82.021 52.584 83.267 ;
     RECT  56.4 82.451 56.808 83.267 ;
     RECT  61.8 82.595 63.096 83.317 ;
     RECT  27.504 83.221 36.648 83.603 ;
     RECT  58.176 81.059 58.536 83.603 ;
     RECT  20.976 83.171 21.624 83.699 ;
     RECT  9.936 83.125 15.096 83.701 ;
     RECT  24 83.171 25.128 83.747 ;
     RECT  7.8 2.151 8.112 83.749 ;
     RECT  9.936 83.701 15.768 83.749 ;
     RECT  20.976 83.699 21.144 83.795 ;
     RECT  134.832 40.981 134.856 83.795 ;
     RECT  144.576 77.795 144.6 83.795 ;
     RECT  67.2 82.115 67.512 83.797 ;
     RECT  18.336 83.267 19.176 83.987 ;
     RECT  38.64 82.979 45.912 84.083 ;
     RECT  58.176 83.603 58.2 84.131 ;
     RECT  18.48 83.987 19.176 84.179 ;
     RECT  20.976 83.795 21.096 84.181 ;
     RECT  39.072 84.083 45.912 84.227 ;
     RECT  67.2 83.797 67.608 84.229 ;
     RECT  36.288 83.603 36.648 84.277 ;
     RECT  20.4 84.181 21.096 84.323 ;
     RECT  61.8 83.317 63.336 84.323 ;
     RECT  53.952 78.659 53.976 84.325 ;
     RECT  83.28 79.141 83.712 84.325 ;
     RECT  20.496 84.323 21.096 84.371 ;
     RECT  69.648 82.453 73.032 84.467 ;
     RECT  18.48 84.179 19.032 84.563 ;
     RECT  61.8 84.323 63.096 84.563 ;
     RECT  69.648 84.467 71.256 84.563 ;
     RECT  67.056 84.229 67.608 84.565 ;
     RECT  7.8 83.749 15.768 84.611 ;
     RECT  67.056 84.565 67.656 84.613 ;
     RECT  24 83.747 24.984 84.659 ;
     RECT  69.648 84.563 71.064 84.659 ;
     RECT  51 82.211 51.312 84.661 ;
     RECT  52.416 84.373 52.44 84.661 ;
     RECT  61.8 84.563 62.112 84.661 ;
     RECT  24 84.659 24.504 84.709 ;
     RECT  40.08 84.227 45.912 84.755 ;
     RECT  51 84.661 52.44 84.803 ;
     RECT  72.6 84.467 73.032 84.805 ;
     RECT  67.008 84.613 67.656 84.899 ;
     RECT  5.376 80.963 5.4 84.901 ;
     RECT  27.504 83.603 35.208 84.901 ;
     RECT  23.568 84.709 24.504 84.949 ;
     RECT  67.2 84.899 67.656 84.949 ;
     RECT  27.456 84.901 35.208 84.997 ;
     RECT  52.416 84.803 52.44 85.091 ;
     RECT  61.584 84.661 62.112 85.091 ;
     RECT  69.648 84.659 70.776 85.091 ;
     RECT  9.936 84.611 15.768 85.093 ;
     RECT  27.456 84.997 35.304 85.093 ;
     RECT  9.936 85.093 15.864 85.235 ;
     RECT  45.312 84.755 45.912 85.237 ;
     RECT  26.928 85.093 35.304 85.331 ;
     RECT  83.28 84.325 83.976 85.379 ;
     RECT  36.288 84.277 37.128 85.427 ;
     RECT  53.952 84.325 54.936 85.427 ;
     RECT  131.76 80.917 132.312 85.427 ;
     RECT  18.48 84.563 18.912 85.429 ;
     RECT  56.4 83.267 56.712 85.477 ;
     RECT  69.648 85.091 70.68 85.477 ;
     RECT  131.904 85.427 132.312 85.523 ;
     RECT  5.376 84.901 5.688 85.525 ;
     RECT  20.976 84.371 21.096 85.571 ;
     RECT  49.536 85.093 49.56 85.667 ;
     RECT  53.952 85.427 53.976 85.667 ;
     RECT  69.36 85.477 70.68 85.715 ;
     RECT  40.08 84.755 44.328 85.765 ;
     RECT  45.312 85.237 46.104 85.765 ;
     RECT  83.28 85.379 83.712 85.813 ;
     RECT  70.128 85.715 70.68 85.859 ;
     RECT  23.184 84.949 24.504 85.909 ;
     RECT  86.016 85.765 86.04 85.909 ;
     RECT  72.6 84.805 73.464 85.955 ;
     RECT  23.04 85.909 24.504 85.957 ;
     RECT  56.304 85.477 56.712 85.957 ;
     RECT  22.8 85.957 24.504 86.005 ;
     RECT  112.704 80.485 112.728 86.005 ;
     RECT  67.2 84.949 67.752 86.051 ;
     RECT  112.704 86.005 112.824 86.051 ;
     RECT  27.456 85.331 35.304 86.099 ;
     RECT  27.504 86.099 35.304 86.101 ;
     RECT  36.288 85.427 36.408 86.101 ;
     RECT  5.376 85.525 6.648 86.195 ;
     RECT  75.792 83.221 76.2 86.293 ;
     RECT  70.368 85.859 70.68 86.533 ;
     RECT  20.976 85.571 21 86.581 ;
     RECT  67.2 86.051 67.608 86.581 ;
     RECT  78 82.981 80.328 86.627 ;
     RECT  27.504 86.101 36.408 86.675 ;
     RECT  64.992 86.005 65.016 86.675 ;
     RECT  85.536 85.909 86.04 86.675 ;
     RECT  22.704 86.005 24.504 86.677 ;
     RECT  17.664 85.429 18.912 86.771 ;
     RECT  27.504 86.675 35.304 86.771 ;
     RECT  22.224 86.677 24.504 86.773 ;
     RECT  25.632 86.725 25.656 86.773 ;
     RECT  22.224 86.773 25.656 86.819 ;
     RECT  18.192 86.771 18.912 86.821 ;
     RECT  61.8 85.091 62.112 86.821 ;
     RECT  72.6 85.955 73.416 86.867 ;
     RECT  27.504 86.771 35.112 87.107 ;
     RECT  51 84.803 51.312 87.109 ;
     RECT  7.8 84.611 8.112 87.157 ;
     RECT  85.536 86.675 85.752 87.157 ;
     RECT  56.304 85.957 56.808 87.203 ;
     RECT  5.376 86.195 5.688 87.205 ;
     RECT  5.376 87.205 6.504 87.251 ;
     RECT  18.192 86.821 19.272 87.253 ;
     RECT  67.104 86.581 67.608 87.253 ;
     RECT  9.936 85.235 15.768 87.589 ;
     RECT  18.192 87.253 19.464 87.683 ;
     RECT  36.288 86.675 36.408 87.781 ;
     RECT  37.584 86.581 37.608 87.781 ;
     RECT  22.464 86.819 25.656 87.827 ;
     RECT  36.288 87.781 37.608 87.827 ;
     RECT  58.32 85.477 58.344 87.827 ;
     RECT  67.104 87.253 67.656 87.827 ;
     RECT  81.648 86.053 81.672 87.827 ;
     RECT  146.88 40.981 149.352 87.827 ;
     RECT  78 86.627 80.184 87.875 ;
     RECT  9.936 87.589 16.008 87.877 ;
     RECT  27.648 87.107 35.112 87.925 ;
     RECT  36.288 87.827 37.08 87.925 ;
     RECT  9.936 87.877 16.104 88.115 ;
     RECT  18.192 87.683 19.032 88.115 ;
     RECT  20.736 86.581 21 88.115 ;
     RECT  67.2 87.827 67.656 88.115 ;
     RECT  59.616 82.979 59.64 88.213 ;
     RECT  145.776 77.795 145.8 88.213 ;
     RECT  145.296 88.213 145.8 88.259 ;
     RECT  39.072 84.227 39.096 88.309 ;
     RECT  40.08 85.765 46.92 88.309 ;
     RECT  84.96 87.157 85.752 88.309 ;
     RECT  22.464 87.827 25.176 88.403 ;
     RECT  50.544 87.109 51.312 88.403 ;
     RECT  39.072 88.309 46.92 88.405 ;
     RECT  94.08 75.157 94.512 88.451 ;
     RECT  75.696 86.293 76.2 88.501 ;
     RECT  38.304 88.405 46.92 88.547 ;
     RECT  84.96 88.309 86.04 88.595 ;
     RECT  72.6 86.867 72.912 88.789 ;
     RECT  27.648 87.925 37.08 88.883 ;
     RECT  74.496 87.925 74.52 88.885 ;
     RECT  75.696 88.501 76.632 88.885 ;
     RECT  83.232 85.813 83.712 88.885 ;
     RECT  9.936 88.115 16.008 88.931 ;
     RECT  20.832 88.115 21 88.931 ;
     RECT  28.128 88.883 37.08 88.979 ;
     RECT  72.24 88.789 72.912 88.979 ;
     RECT  23.136 88.403 25.176 89.123 ;
     RECT  55.296 88.309 55.32 89.125 ;
     RECT  56.4 87.203 56.808 89.125 ;
     RECT  55.296 89.125 56.808 89.171 ;
     RECT  67.2 88.115 67.608 89.413 ;
     RECT  82.32 88.885 83.712 89.413 ;
     RECT  51 88.403 51.312 89.461 ;
     RECT  74.496 88.885 76.632 89.507 ;
     RECT  28.224 88.979 37.08 89.651 ;
     RECT  59.616 88.213 60.36 89.699 ;
     RECT  82.32 89.413 83.832 89.699 ;
     RECT  7.8 87.157 8.952 89.941 ;
     RECT  9.936 88.931 15.672 89.941 ;
     RECT  87.792 88.069 87.816 89.941 ;
     RECT  88.8 2.151 89.112 89.941 ;
     RECT  87.792 89.941 89.112 89.987 ;
     RECT  28.224 89.651 36.408 89.989 ;
     RECT  72.6 88.979 72.912 89.989 ;
     RECT  85.2 88.595 86.04 89.989 ;
     RECT  6.48 87.251 6.504 90.083 ;
     RECT  20.88 88.931 21 90.083 ;
     RECT  5.376 87.251 5.4 90.131 ;
     RECT  64.224 88.501 64.248 90.323 ;
     RECT  39.072 88.547 46.92 90.419 ;
     RECT  20.976 90.083 21 90.517 ;
     RECT  55.536 89.171 56.808 90.517 ;
     RECT  74.496 89.507 76.2 90.517 ;
     RECT  84.96 89.989 86.04 90.611 ;
     RECT  83.28 89.699 83.832 90.613 ;
     RECT  20.976 90.517 21.144 90.659 ;
     RECT  67.2 89.413 68.376 90.659 ;
     RECT  73.92 90.517 76.2 90.661 ;
     RECT  39.072 90.419 44.376 90.755 ;
     RECT  88.032 89.987 89.112 90.755 ;
     RECT  28.032 89.989 36.408 90.853 ;
     RECT  23.136 89.123 25.128 90.949 ;
     RECT  7.8 89.941 15.672 90.995 ;
     RECT  45.6 90.419 46.92 91.043 ;
     RECT  78 87.875 79.224 91.093 ;
     RECT  83.28 90.613 84.024 91.093 ;
     RECT  4.704 90.517 4.728 91.235 ;
     RECT  55.536 90.517 57.288 91.235 ;
     RECT  147.408 87.827 149.352 91.235 ;
     RECT  145.296 88.259 145.32 91.379 ;
     RECT  83.232 91.093 84.024 91.571 ;
     RECT  83.232 91.571 83.712 91.619 ;
     RECT  61.8 86.821 62.952 91.621 ;
     RECT  70.368 86.533 70.968 91.621 ;
     RECT  72.48 89.989 72.912 91.621 ;
     RECT  27.984 90.853 36.408 91.667 ;
     RECT  37.584 91.621 37.608 91.717 ;
     RECT  27.984 91.667 30.072 91.763 ;
     RECT  22.704 90.949 25.128 91.811 ;
     RECT  68.976 91.285 69 91.811 ;
     RECT  73.92 90.661 76.344 91.811 ;
     RECT  80.592 90.613 80.616 91.811 ;
     RECT  18.6 88.115 19.032 91.813 ;
     RECT  47.424 91.189 47.448 92.099 ;
     RECT  70.368 91.621 72.912 92.245 ;
     RECT  56.4 91.235 57.288 92.291 ;
     RECT  61.8 91.621 63.288 92.435 ;
     RECT  83.28 91.619 83.712 92.435 ;
     RECT  77.904 91.093 79.224 92.485 ;
     RECT  37.392 91.717 37.608 92.533 ;
     RECT  39.072 90.755 44.232 92.533 ;
     RECT  77.856 92.485 79.224 92.533 ;
     RECT  70.08 92.245 72.912 92.581 ;
     RECT  7.8 90.995 15.48 92.677 ;
     RECT  16.608 92.581 16.632 92.677 ;
     RECT  85.536 90.611 86.04 92.677 ;
     RECT  77.76 92.533 79.224 92.725 ;
     RECT  56.4 92.291 56.808 92.771 ;
     RECT  69.12 92.581 72.912 92.867 ;
     RECT  18.6 91.813 19.32 92.869 ;
     RECT  56.4 92.771 56.712 92.869 ;
     RECT  77.232 92.725 79.224 92.869 ;
     RECT  20.976 90.659 21 92.963 ;
     RECT  45.6 91.043 46.296 93.013 ;
     RECT  61.8 92.435 62.112 93.013 ;
     RECT  60.624 91.141 60.648 93.059 ;
     RECT  70.08 92.867 72.912 93.061 ;
     RECT  74.016 91.811 76.2 93.061 ;
     RECT  22.704 91.811 24.552 93.109 ;
     RECT  51 89.461 51.48 93.109 ;
     RECT  63.216 92.435 63.288 93.155 ;
     RECT  37.392 92.533 44.232 93.349 ;
     RECT  45.36 93.013 46.296 93.349 ;
     RECT  26.928 92.821 26.952 93.445 ;
     RECT  59.616 89.699 59.64 93.445 ;
     RECT  22.704 93.109 25.416 93.493 ;
     RECT  88.8 90.755 89.112 93.493 ;
     RECT  70.08 93.061 76.2 93.539 ;
     RECT  112.8 86.051 112.824 93.539 ;
     RECT  146.448 91.477 146.472 93.539 ;
     RECT  148.2 91.235 149.352 93.539 ;
     RECT  26.88 93.445 26.952 93.589 ;
     RECT  28.032 91.763 30.072 93.589 ;
     RECT  61.68 93.013 62.112 93.779 ;
     RECT  67.2 90.659 67.704 93.829 ;
     RECT  18.6 92.869 19.368 93.925 ;
     RECT  83.4 92.435 83.712 93.925 ;
     RECT  96.624 88.885 96.648 93.925 ;
     RECT  6.24 93.925 6.264 94.021 ;
     RECT  7.8 92.677 16.632 94.021 ;
     RECT  31.056 91.667 36.408 94.021 ;
     RECT  37.392 93.349 46.296 94.021 ;
     RECT  96.624 93.925 96.744 94.021 ;
     RECT  96.576 94.021 96.744 94.067 ;
     RECT  18.6 93.925 19.992 94.069 ;
     RECT  70.704 93.539 76.2 94.115 ;
     RECT  53.856 93.445 53.88 94.165 ;
     RECT  22.704 93.493 25.704 94.259 ;
     RECT  26.88 93.589 30.072 94.261 ;
     RECT  31.056 94.021 46.296 94.261 ;
     RECT  26.88 94.261 46.296 94.499 ;
     RECT  22.704 94.259 25.416 94.547 ;
     RECT  6.24 94.021 16.632 94.597 ;
     RECT  18.6 94.069 20.136 94.645 ;
     RECT  52.944 94.165 53.88 94.691 ;
     RECT  85.536 92.677 86.232 94.691 ;
     RECT  52.944 94.691 52.968 94.739 ;
     RECT  5.328 94.597 16.632 94.787 ;
     RECT  70.704 94.115 70.968 94.837 ;
     RECT  26.88 94.499 36.408 94.883 ;
     RECT  67.104 93.829 67.704 94.885 ;
     RECT  55.776 92.869 56.712 94.933 ;
     RECT  61.8 93.779 62.112 94.981 ;
     RECT  22.704 94.547 25.128 95.029 ;
     RECT  7.8 94.787 16.632 95.075 ;
     RECT  77.232 92.869 79.32 95.077 ;
     RECT  5.328 94.787 6.264 95.123 ;
     RECT  22.272 95.029 25.128 95.171 ;
     RECT  83.232 93.925 83.712 95.171 ;
     RECT  50.688 93.109 51.48 95.219 ;
     RECT  33.312 94.883 36.408 95.315 ;
     RECT  67.056 94.885 67.704 95.317 ;
     RECT  22.512 95.171 25.128 95.507 ;
     RECT  67.056 95.317 68.52 95.507 ;
     RECT  72.6 94.115 76.2 95.605 ;
     RECT  77.232 95.077 79.944 95.605 ;
     RECT  63.216 93.155 63.24 95.653 ;
     RECT  67.056 95.507 67.704 95.653 ;
     RECT  72.6 95.605 79.944 95.701 ;
     RECT  72.336 95.701 79.944 95.747 ;
     RECT  68.928 95.557 68.952 95.795 ;
     RECT  88.704 93.493 89.112 95.795 ;
     RECT  55.152 94.933 56.712 95.939 ;
     RECT  86.016 94.691 86.232 95.939 ;
     RECT  83.28 95.171 83.712 96.035 ;
     RECT  22.512 95.507 24.552 96.131 ;
     RECT  37.392 94.499 46.296 96.131 ;
     RECT  77.232 95.747 79.944 96.131 ;
     RECT  7.8 95.075 15.672 96.133 ;
     RECT  18.6 94.645 21.096 96.371 ;
     RECT  37.392 96.131 37.608 96.371 ;
     RECT  63.168 95.653 63.24 96.419 ;
     RECT  66.096 95.653 67.704 96.419 ;
     RECT  70.32 94.837 70.968 96.467 ;
     RECT  67.056 96.419 67.704 96.469 ;
     RECT  51 95.219 51.48 96.755 ;
     RECT  55.776 95.939 56.712 96.853 ;
     RECT  59.232 93.445 59.64 96.853 ;
     RECT  67.056 96.469 67.752 96.899 ;
     RECT  77.232 96.131 78.744 96.899 ;
     RECT  26.88 94.883 32.088 96.901 ;
     RECT  79.92 96.131 79.944 96.901 ;
     RECT  79.92 96.901 80.568 96.997 ;
     RECT  55.776 96.853 57.048 97.139 ;
     RECT  58.896 96.853 59.64 97.139 ;
     RECT  61.008 94.981 62.112 97.139 ;
     RECT  79.92 96.997 81 97.139 ;
     RECT  77.232 96.899 78.696 97.187 ;
     RECT  59.232 97.139 59.64 97.235 ;
     RECT  6.24 95.123 6.264 97.283 ;
     RECT  33.408 95.315 36.408 97.475 ;
     RECT  52.896 95.125 52.92 97.523 ;
     RECT  61.8 97.139 62.112 97.573 ;
     RECT  63.216 96.419 63.24 97.573 ;
     RECT  7.8 96.133 16.008 97.715 ;
     RECT  36.288 97.475 36.408 97.717 ;
     RECT  37.536 96.371 37.608 97.717 ;
     RECT  36.288 97.717 37.608 97.763 ;
     RECT  36.288 97.763 37.56 97.907 ;
     RECT  49.776 96.565 49.8 97.907 ;
     RECT  56.4 97.139 57.048 97.907 ;
     RECT  72.336 95.747 76.2 97.909 ;
     RECT  72.048 97.909 76.2 97.957 ;
     RECT  77.232 97.187 78.648 97.957 ;
     RECT  7.8 97.715 15.48 98.051 ;
     RECT  87.792 96.901 87.816 98.099 ;
     RECT  22.512 96.131 24.504 98.243 ;
     RECT  38.64 96.131 46.296 98.339 ;
     RECT  67.056 96.899 67.704 98.339 ;
     RECT  22.512 98.243 22.728 98.341 ;
     RECT  65.76 96.613 65.784 98.435 ;
     RECT  59.616 97.235 59.64 98.581 ;
     RECT  59.28 98.581 59.64 98.627 ;
     RECT  61.8 97.573 63.24 98.675 ;
     RECT  79.92 97.139 80.568 98.675 ;
     RECT  72.048 97.957 78.648 98.915 ;
     RECT  26.88 96.901 32.232 98.963 ;
     RECT  52.992 98.581 53.016 98.963 ;
     RECT  7.8 98.051 13.656 99.155 ;
     RECT  83.4 96.035 83.712 99.157 ;
     RECT  24 98.243 24.504 99.203 ;
     RECT  72.048 98.915 76.056 99.203 ;
     RECT  39.072 98.339 46.296 99.251 ;
     RECT  21.84 98.341 22.728 99.299 ;
     RECT  36.288 97.907 36.408 99.395 ;
     RECT  33.408 97.475 35.256 99.443 ;
     RECT  37.536 97.907 37.56 99.491 ;
     RECT  63.216 98.675 63.24 99.491 ;
     RECT  69.552 98.005 69.576 99.587 ;
     RECT  36.336 99.395 36.408 99.685 ;
     RECT  59.28 98.627 59.304 99.685 ;
     RECT  33.408 99.443 35.112 99.731 ;
     RECT  56.4 97.907 56.712 99.733 ;
     RECT  29.136 98.963 32.232 99.779 ;
     RECT  86.016 95.939 86.04 99.779 ;
     RECT  59.232 99.685 59.304 99.827 ;
     RECT  77.232 98.915 78.648 99.925 ;
     RECT  14.688 98.051 15.48 99.971 ;
     RECT  75.648 99.203 76.056 100.019 ;
     RECT  77.184 99.925 78.648 100.021 ;
     RECT  22.512 99.299 22.728 100.261 ;
     RECT  67.056 98.339 67.656 100.261 ;
     RECT  51 96.755 51.312 100.597 ;
     RECT  18.6 96.371 20.136 100.787 ;
     RECT  36.336 99.685 37.32 100.787 ;
     RECT  56.304 99.733 56.712 100.787 ;
     RECT  29.28 99.779 32.232 100.789 ;
     RECT  51 100.597 51.432 100.789 ;
     RECT  67.056 100.261 68.52 100.883 ;
     RECT  83.4 99.157 84.408 100.883 ;
     RECT  59.232 99.827 59.256 100.885 ;
     RECT  24 99.203 24.408 100.931 ;
     RECT  54.432 100.069 54.456 100.931 ;
     RECT  75.648 100.019 75.816 100.931 ;
     RECT  7.8 99.155 8.112 100.933 ;
     RECT  9.696 99.155 13.656 100.933 ;
     RECT  96.576 94.067 96.6 101.075 ;
     RECT  39.504 99.251 46.296 101.125 ;
     RECT  7.8 100.933 13.752 101.171 ;
     RECT  15.072 99.971 15.48 101.173 ;
     RECT  26.88 98.963 28.152 101.317 ;
     RECT  29.232 100.789 32.232 101.317 ;
     RECT  18.6 100.787 19.368 101.413 ;
     RECT  39.216 101.125 46.296 101.413 ;
     RECT  51 100.789 51.816 101.413 ;
     RECT  22.512 100.261 22.92 101.507 ;
     RECT  76.896 100.021 78.648 101.507 ;
     RECT  87.072 100.837 87.096 101.555 ;
     RECT  9.696 101.171 13.752 101.605 ;
     RECT  15.072 101.173 16.008 101.605 ;
     RECT  26.88 101.317 32.232 101.651 ;
     RECT  67.2 100.883 68.52 101.845 ;
     RECT  70.944 96.467 70.968 101.941 ;
     RECT  39.216 101.413 46.536 102.035 ;
     RECT  59.232 100.885 59.544 102.083 ;
     RECT  51 101.413 52.296 102.179 ;
     RECT  70.656 101.941 70.968 102.277 ;
     RECT  61.8 98.675 62.112 102.325 ;
     RECT  39.216 102.035 46.296 102.371 ;
     RECT  59.232 102.083 59.256 102.371 ;
     RECT  64.416 101.317 64.44 102.419 ;
     RECT  75.648 100.931 75.672 102.421 ;
     RECT  76.896 101.507 78.552 102.421 ;
     RECT  75.648 102.421 78.552 102.515 ;
     RECT  22.512 101.507 22.632 102.565 ;
     RECT  61.68 102.325 62.112 102.565 ;
     RECT  9.696 101.605 16.008 102.611 ;
     RECT  29.184 101.651 32.232 102.611 ;
     RECT  75.648 102.515 78.408 102.611 ;
     RECT  18.24 101.413 19.368 102.659 ;
     RECT  81.456 101.269 81.48 102.659 ;
     RECT  17.088 102.661 17.112 102.757 ;
     RECT  16.8 102.757 17.112 102.803 ;
     RECT  26.88 101.651 28.152 102.851 ;
     RECT  28.128 102.851 28.152 102.949 ;
     RECT  29.184 102.611 30.84 102.949 ;
     RECT  70.32 102.277 70.968 103.093 ;
     RECT  21.696 102.565 22.632 103.139 ;
     RECT  39.504 102.371 46.296 103.141 ;
     RECT  69.84 103.093 70.968 103.187 ;
     RECT  22.608 103.139 22.632 103.189 ;
     RECT  24 100.931 24.312 103.189 ;
     RECT  70.944 103.187 70.968 103.235 ;
     RECT  79.92 98.675 79.944 103.235 ;
     RECT  39.504 103.141 46.536 103.429 ;
     RECT  66.24 101.845 68.52 103.475 ;
     RECT  76.368 102.611 78.408 103.475 ;
     RECT  38.976 103.429 46.536 103.477 ;
     RECT  38.256 103.477 46.536 103.571 ;
     RECT  77.184 103.475 78.408 103.571 ;
     RECT  66.24 103.475 67.8 103.619 ;
     RECT  28.128 102.949 30.84 103.715 ;
     RECT  20.832 103.381 21.192 103.763 ;
     RECT  26.88 102.851 27.144 103.763 ;
     RECT  29.184 103.715 30.84 103.907 ;
     RECT  61.296 102.565 62.112 103.907 ;
     RECT  18.336 102.659 19.368 104.003 ;
     RECT  49.248 100.501 49.272 104.051 ;
     RECT  36.336 100.787 36.36 104.147 ;
     RECT  22.608 103.189 24.312 104.243 ;
     RECT  58.128 103.381 58.152 104.243 ;
     RECT  86.016 103.333 86.04 104.291 ;
     RECT  61.68 103.907 62.112 104.339 ;
     RECT  24 104.243 24.312 104.773 ;
     RECT  38.256 103.571 38.52 104.819 ;
     RECT  31.92 102.611 32.232 104.867 ;
     RECT  63.792 103.717 63.816 104.867 ;
     RECT  24 104.773 24.696 104.869 ;
     RECT  27.024 103.763 27.144 104.869 ;
     RECT  28.128 103.715 28.152 104.869 ;
     RECT  33.984 99.731 35.112 104.869 ;
     RECT  77.184 103.571 78.312 104.869 ;
     RECT  67.2 103.619 67.8 104.915 ;
     RECT  72.336 99.203 74.52 104.915 ;
     RECT  80.112 103.621 80.136 104.963 ;
     RECT  27.024 104.869 28.152 105.059 ;
     RECT  39.504 103.571 46.536 105.059 ;
     RECT  77.184 104.869 78.696 105.107 ;
     RECT  24 104.869 24.744 105.253 ;
     RECT  51 102.179 51.312 105.349 ;
     RECT  52.32 102.229 52.344 105.349 ;
     RECT  51 105.349 52.344 105.397 ;
     RECT  67.2 104.915 67.512 105.397 ;
     RECT  78 105.107 78.696 105.397 ;
     RECT  7.8 101.171 8.112 105.445 ;
     RECT  29.184 103.907 29.712 105.445 ;
     RECT  27.024 105.059 27.144 105.491 ;
     RECT  33.696 104.869 35.112 105.491 ;
     RECT  78 105.397 79.512 105.491 ;
     RECT  74.064 104.915 74.52 105.877 ;
     RECT  9.696 102.611 15.096 105.923 ;
     RECT  29.136 105.445 29.712 105.971 ;
     RECT  18.6 104.003 19.368 105.973 ;
     RECT  20.832 103.763 20.856 105.973 ;
     RECT  29.184 105.971 29.712 105.973 ;
     RECT  30.816 103.907 30.84 105.973 ;
     RECT  61.8 104.339 62.112 105.973 ;
     RECT  39.504 105.059 46.488 106.019 ;
     RECT  9.744 105.923 15.096 106.067 ;
     RECT  39.504 106.019 46.296 106.067 ;
     RECT  51 105.397 52.392 106.067 ;
     RECT  71.28 105.397 71.304 106.067 ;
     RECT  18.192 105.973 20.856 106.115 ;
     RECT  49.68 105.397 49.704 106.163 ;
     RECT  29.184 105.973 30.84 106.211 ;
     RECT  22.608 104.243 22.632 106.213 ;
     RECT  18.192 106.115 19.368 106.643 ;
     RECT  61.8 105.973 62.808 106.643 ;
     RECT  79.488 105.491 79.512 106.643 ;
     RECT  66.912 105.397 67.512 106.691 ;
     RECT  18.6 106.643 19.368 106.739 ;
     RECT  29.232 106.211 30.84 106.739 ;
     RECT  78 105.491 78.312 106.741 ;
     RECT  75.552 105.973 75.576 106.787 ;
     RECT  39.504 106.067 40.512 106.979 ;
     RECT  7.344 105.445 8.112 107.027 ;
     RECT  78 106.741 78.408 107.027 ;
     RECT  40.08 106.979 40.512 107.029 ;
     RECT  38.496 104.819 38.52 107.173 ;
     RECT  27.024 105.491 27.096 107.317 ;
     RECT  38.208 107.173 38.52 107.413 ;
     RECT  31.92 104.867 32.184 107.507 ;
     RECT  22.32 106.213 22.632 107.557 ;
     RECT  37.056 106.981 37.08 107.557 ;
     RECT  38.208 107.413 38.664 107.557 ;
     RECT  31.968 107.507 32.184 107.651 ;
     RECT  16.8 102.803 16.824 107.653 ;
     RECT  51 106.067 51.312 107.701 ;
     RECT  74.016 105.877 74.52 107.701 ;
     RECT  20.832 106.115 20.856 107.749 ;
     RECT  21.984 107.557 22.632 107.749 ;
     RECT  72.336 104.915 72.912 107.797 ;
     RECT  74.016 107.701 75.144 107.797 ;
     RECT  33.984 105.491 35.112 107.843 ;
     RECT  20.832 107.749 22.632 107.987 ;
     RECT  37.056 107.557 38.664 108.227 ;
     RECT  20.832 107.987 20.952 108.229 ;
     RECT  21.984 107.987 22.632 108.229 ;
     RECT  24 105.253 25.176 108.277 ;
     RECT  32.064 107.651 32.184 108.277 ;
     RECT  69.84 103.187 69.864 108.323 ;
     RECT  72.336 107.797 75.144 108.371 ;
     RECT  34.176 107.843 35.112 108.517 ;
     RECT  24 108.277 25.224 108.565 ;
     RECT  40.08 107.029 40.728 108.565 ;
     RECT  41.712 106.067 46.296 108.565 ;
     RECT  9.744 106.067 14.376 108.613 ;
     RECT  29.28 106.739 30.84 108.613 ;
     RECT  32.064 108.277 32.328 108.613 ;
     RECT  29.28 108.613 32.328 108.659 ;
     RECT  16.32 107.653 16.824 108.851 ;
     RECT  20.4 108.229 20.952 108.851 ;
     RECT  21.984 108.229 22.68 108.851 ;
     RECT  74.496 108.371 75.144 108.851 ;
     RECT  28.128 105.059 28.152 108.853 ;
     RECT  29.28 108.659 29.928 108.853 ;
     RECT  72.336 108.371 72.912 108.853 ;
     RECT  50.64 107.701 51.312 108.899 ;
     RECT  9.744 108.613 14.712 109.091 ;
     RECT  40.08 108.565 46.296 109.091 ;
     RECT  9.792 109.091 14.712 109.093 ;
     RECT  75.12 108.851 75.144 109.139 ;
     RECT  24 108.565 25.32 109.141 ;
     RECT  26.592 107.317 27.096 109.141 ;
     RECT  24 109.141 27.096 109.283 ;
     RECT  18.6 106.739 18.912 109.285 ;
     RECT  24 109.283 25.32 109.381 ;
     RECT  40.08 109.091 40.728 109.381 ;
     RECT  16.8 108.851 16.824 109.477 ;
     RECT  16.8 109.477 17.016 109.523 ;
     RECT  21.984 108.851 22.008 109.621 ;
     RECT  23.28 109.381 25.32 109.715 ;
     RECT  21.696 109.621 22.008 109.811 ;
     RECT  34.176 108.517 35.352 109.955 ;
     RECT  71.376 108.853 72.912 109.955 ;
     RECT  52.368 106.067 52.392 110.051 ;
     RECT  72.336 109.955 72.912 110.051 ;
     RECT  9.792 109.093 15 110.099 ;
     RECT  10.464 110.099 15 110.195 ;
     RECT  34.176 109.955 35.208 110.195 ;
     RECT  54.096 107.797 54.12 110.195 ;
     RECT  28.128 108.853 29.928 110.485 ;
     RECT  23.28 109.715 25.224 110.531 ;
     RECT  48 108.853 48.024 110.531 ;
     RECT  21.984 109.811 22.008 110.627 ;
     RECT  18.48 109.285 18.912 110.725 ;
     RECT  37.488 108.227 38.664 110.869 ;
     RECT  26.592 109.283 27.096 110.917 ;
     RECT  28.128 110.485 29.976 110.917 ;
     RECT  10.464 110.195 14.712 111.011 ;
     RECT  26.592 110.917 29.976 111.157 ;
     RECT  31.296 108.659 32.328 111.157 ;
     RECT  40.032 109.381 40.728 111.157 ;
     RECT  41.712 109.091 46.296 111.157 ;
     RECT  40.032 111.157 46.296 111.203 ;
     RECT  26.592 111.157 32.328 111.251 ;
     RECT  34.704 110.195 35.208 111.301 ;
     RECT  29.4 111.251 32.328 111.443 ;
     RECT  31.296 111.443 32.328 111.445 ;
     RECT  34.272 111.301 35.208 111.541 ;
     RECT  16.992 109.523 17.016 111.589 ;
     RECT  34.176 111.541 35.928 111.683 ;
     RECT  31.296 111.445 33.096 111.685 ;
     RECT  34.176 111.683 35.256 111.685 ;
     RECT  24 110.531 25.224 111.733 ;
     RECT  40.032 111.203 46.2 111.827 ;
     RECT  23.856 111.733 25.224 111.925 ;
     RECT  40.032 111.827 40.728 112.115 ;
     RECT  7.8 107.027 8.112 112.261 ;
     RECT  41.76 111.827 46.2 112.499 ;
     RECT  16.704 111.589 17.016 112.691 ;
     RECT  23.52 111.925 25.224 112.691 ;
     RECT  31.296 111.685 35.256 112.691 ;
     RECT  29.4 111.443 30.312 112.741 ;
     RECT  31.296 112.691 32.184 112.741 ;
     RECT  37.488 110.869 38.712 112.741 ;
     RECT  6.864 112.261 8.112 112.883 ;
     RECT  23.52 112.691 25.128 113.075 ;
     RECT  23.52 113.075 24.888 113.125 ;
     RECT  12.192 111.011 14.712 113.171 ;
     RECT  37.488 112.741 39.144 113.173 ;
     RECT  41.76 112.499 46.104 113.219 ;
     RECT  33.984 112.691 35.256 113.315 ;
     RECT  10.464 111.011 11.016 113.317 ;
     RECT  10.368 113.317 11.016 113.365 ;
     RECT  16.992 112.691 17.016 113.365 ;
     RECT  18.192 110.725 18.912 113.365 ;
     RECT  20.496 111.685 20.52 113.365 ;
     RECT  20.208 113.365 20.52 113.411 ;
     RECT  26.592 111.251 28.152 113.459 ;
     RECT  10.272 113.365 11.016 113.891 ;
     RECT  26.592 113.459 27.336 113.987 ;
     RECT  13.2 113.171 14.712 113.989 ;
     RECT  47.904 110.917 47.928 114.035 ;
     RECT  23.472 113.125 24.888 114.083 ;
     RECT  26.592 113.987 27.048 114.083 ;
     RECT  41.856 113.219 46.104 114.085 ;
     RECT  13.2 113.989 15.576 114.131 ;
     RECT  16.992 113.365 18.912 114.131 ;
     RECT  22.416 110.629 22.44 114.227 ;
     RECT  36.576 113.173 39.144 114.275 ;
     RECT  40.2 112.115 40.728 114.277 ;
     RECT  41.856 114.085 46.152 114.277 ;
     RECT  36.576 114.275 38.808 114.371 ;
     RECT  17.568 114.131 18.912 114.419 ;
     RECT  29.4 112.741 32.184 114.421 ;
     RECT  23.856 114.083 24.888 114.467 ;
     RECT  40.2 114.277 46.152 114.467 ;
     RECT  18.6 114.419 18.912 114.517 ;
     RECT  26.736 114.083 27.048 114.611 ;
     RECT  36.576 114.371 38.712 114.611 ;
     RECT  41.856 114.467 46.152 114.611 ;
     RECT  40.2 114.467 40.872 114.661 ;
     RECT  17.568 114.419 17.592 114.707 ;
     RECT  10.368 113.891 11.016 114.803 ;
     RECT  36.576 114.611 38.232 114.803 ;
     RECT  12.192 113.171 12.216 114.851 ;
     RECT  33.984 113.315 35.208 114.853 ;
     RECT  40.08 114.661 40.872 115.043 ;
     RECT  7.8 112.883 8.112 115.093 ;
     RECT  33.6 114.853 35.208 115.139 ;
     RECT  10.464 114.803 11.016 115.187 ;
     RECT  33.984 115.139 35.208 115.187 ;
     RECT  36.576 114.803 37.992 115.187 ;
     RECT  42.288 114.611 46.152 115.187 ;
     RECT  18.6 114.517 19.032 115.573 ;
     RECT  20.208 113.411 20.232 115.573 ;
     RECT  42.288 115.187 44.616 115.573 ;
     RECT  10.992 115.187 11.016 115.763 ;
     RECT  29.28 114.421 32.184 115.763 ;
     RECT  13.2 114.131 14.712 115.909 ;
     RECT  17.04 115.669 17.064 115.909 ;
     RECT  24 114.467 24.888 116.005 ;
     RECT  26.736 114.611 26.76 116.051 ;
     RECT  45.6 115.187 46.152 116.053 ;
     RECT  16.992 115.909 17.064 116.147 ;
     RECT  42.192 115.573 44.616 116.147 ;
     RECT  34.704 115.187 35.208 116.149 ;
     RECT  13.2 115.909 14.808 116.195 ;
     RECT  24 116.005 24.936 116.197 ;
     RECT  16.992 116.147 17.016 116.243 ;
     RECT  40.08 115.043 40.512 116.293 ;
     RECT  42.192 116.147 44.568 116.339 ;
     RECT  29.28 115.763 32.088 116.341 ;
     RECT  36.576 115.187 37.512 116.389 ;
     RECT  27.888 116.197 27.912 116.531 ;
     RECT  29.04 116.341 32.088 116.531 ;
     RECT  34.32 116.149 35.208 116.579 ;
     RECT  24 116.197 25.32 116.581 ;
     RECT  29.04 116.531 30.264 116.627 ;
     RECT  32.064 116.531 32.088 116.627 ;
     RECT  38.784 115.813 38.808 116.627 ;
     RECT  34.704 116.579 35.208 116.675 ;
     RECT  39.984 116.293 40.512 116.771 ;
     RECT  23.28 116.581 25.32 116.819 ;
     RECT  14.784 116.195 14.808 116.867 ;
     RECT  44.112 116.339 44.568 116.867 ;
     RECT  45.6 116.053 46.776 116.867 ;
     RECT  29.4 116.627 30.264 116.963 ;
     RECT  45.6 116.867 46.056 117.011 ;
     RECT  36.576 116.389 37.608 117.109 ;
     RECT  29.4 116.963 29.88 117.155 ;
     RECT  36.576 117.109 38.232 117.299 ;
     RECT  42.192 116.339 43.08 117.299 ;
     RECT  36.576 117.299 37.608 117.349 ;
     RECT  44.208 116.867 44.568 117.349 ;
     RECT  45.6 117.011 45.912 117.349 ;
     RECT  18.6 115.573 20.232 117.443 ;
     RECT  42.192 117.299 42.312 117.443 ;
     RECT  44.208 117.349 45.912 117.491 ;
     RECT  24 116.819 25.32 117.539 ;
     RECT  13.2 116.195 13.512 117.637 ;
     RECT  29.4 117.155 29.712 117.637 ;
     RECT  20.208 117.443 20.232 117.827 ;
     RECT  36.528 117.349 37.608 117.875 ;
     RECT  33.168 116.245 33.192 117.925 ;
     RECT  34.8 116.675 35.208 117.925 ;
     RECT  36.528 117.875 36.6 117.925 ;
     RECT  40.2 116.771 40.512 117.925 ;
     RECT  33.072 117.925 33.192 117.971 ;
     RECT  6.864 115.093 8.112 118.211 ;
     RECT  12.864 117.637 13.512 118.213 ;
     RECT  12 118.213 13.512 118.259 ;
     RECT  39.552 117.925 40.512 118.451 ;
     RECT  33.072 117.971 33.096 118.453 ;
     RECT  34.8 117.925 36.6 118.547 ;
     RECT  9.888 118.165 9.912 118.595 ;
     RECT  22.992 117.925 23.016 118.595 ;
     RECT  32.16 118.453 33.096 118.595 ;
     RECT  45.024 117.491 45.912 118.739 ;
     RECT  24 117.539 25.224 119.027 ;
     RECT  12 118.259 12.024 119.171 ;
     RECT  42.288 117.443 42.312 119.411 ;
     RECT  29.136 117.637 29.712 119.413 ;
     RECT  13.056 118.259 13.512 119.507 ;
     RECT  29.136 119.413 30.072 119.509 ;
     RECT  33.072 118.595 33.096 119.555 ;
     RECT  36.576 118.547 36.6 119.941 ;
     RECT  34.8 118.547 35.208 119.987 ;
     RECT  26.448 119.269 26.472 120.131 ;
     RECT  28.656 119.509 30.072 120.275 ;
     RECT  24 119.027 24.408 120.323 ;
     RECT  28.704 120.275 30.072 120.611 ;
     RECT  20.832 119.653 20.856 120.995 ;
     RECT  28.704 120.611 29.712 121.331 ;
     RECT  31.584 120.229 31.608 121.427 ;
     RECT  36.576 119.941 37.224 123.731 ;
     RECT  2.4 2.151 2.712 127.449 ;
     RECT  7.8 118.211 8.112 127.449 ;
     RECT  13.2 119.507 13.512 127.449 ;
     RECT  18.6 117.443 18.912 127.449 ;
     RECT  24 120.323 24.312 127.449 ;
     RECT  29.4 121.331 29.712 127.449 ;
     RECT  34.8 119.987 35.112 127.449 ;
     RECT  40.2 118.451 40.512 127.449 ;
     RECT  45.6 118.739 45.912 127.449 ;
     RECT  51 108.899 51.312 127.449 ;
     RECT  56.4 100.787 56.712 127.449 ;
     RECT  61.8 106.643 62.112 127.449 ;
     RECT  67.2 106.691 67.512 127.449 ;
     RECT  72.6 110.051 72.912 127.449 ;
     RECT  78 107.027 78.312 127.449 ;
     RECT  83.4 100.883 83.712 127.449 ;
     RECT  88.8 95.795 89.112 127.449 ;
     RECT  94.2 88.451 94.512 127.449 ;
     RECT  99.6 2.151 99.912 127.449 ;
     RECT  105 2.151 105.312 127.449 ;
     RECT  110.4 2.151 110.712 127.449 ;
     RECT  115.8 2.151 116.112 127.449 ;
     RECT  121.2 2.151 121.512 127.449 ;
     RECT  126.6 2.151 126.912 127.449 ;
     RECT  132 85.523 132.312 127.449 ;
     RECT  137.4 2.151 137.712 127.449 ;
     RECT  142.8 2.151 143.112 127.449 ;
     RECT  148.2 93.539 148.512 127.449 ;
     RECT  153.6 2.151 153.912 127.449 ;
     RECT  159 2.151 159.312 127.449 ;
     RECT  164.4 41.219 164.712 127.449 ;
     RECT  169.8 2.151 170.112 127.449 ;
     RECT  175.2 2.151 175.512 127.449 ;
     RECT  180.6 2.151 180.912 127.449 ;
     RECT  186 2.151 186.312 127.449 ;
     RECT  191.4 2.151 191.712 127.449 ;
     RECT  196.8 2.151 197.112 127.449 ;
     RECT  202.2 2.151 202.512 127.449 ;
     RECT  207.6 2.151 207.912 127.449 ;
     RECT  213 2.151 213.312 127.449 ;
     RECT  218.4 2.151 218.712 127.449 ;
     RECT  223.8 2.151 224.112 127.449 ;
     RECT  229.2 2.151 229.512 127.449 ;
     RECT  234.6 2.151 234.912 127.449 ;
     RECT  240 2.151 240.312 127.449 ;
     RECT  245.4 2.151 245.712 127.449 ;
     RECT  250.8 48.803 251.112 127.449 ;
     RECT  256.2 2.151 256.512 127.449 ;
     RECT  2.4 127.449 2.52 127.463 ;
     RECT  7.8 127.449 7.92 127.463 ;
     RECT  13.2 127.449 13.32 127.463 ;
     RECT  18.6 127.449 18.72 127.463 ;
     RECT  24 127.449 24.12 127.463 ;
     RECT  29.4 127.449 29.52 127.463 ;
     RECT  34.8 127.449 34.92 127.463 ;
     RECT  40.2 127.449 40.32 127.463 ;
     RECT  45.6 127.449 45.72 127.463 ;
     RECT  51 127.449 51.12 127.463 ;
     RECT  56.4 127.449 56.52 127.463 ;
     RECT  61.8 127.449 61.92 127.463 ;
     RECT  67.2 127.449 67.32 127.463 ;
     RECT  72.6 127.449 72.72 127.463 ;
     RECT  78 127.449 78.12 127.463 ;
     RECT  83.4 127.449 83.52 127.463 ;
     RECT  88.8 127.449 88.92 127.463 ;
     RECT  94.2 127.449 94.32 127.463 ;
     RECT  99.6 127.449 99.72 127.463 ;
     RECT  105 127.449 105.12 127.463 ;
     RECT  110.4 127.449 110.52 127.463 ;
     RECT  115.8 127.449 115.92 127.463 ;
     RECT  121.2 127.449 121.32 127.463 ;
     RECT  126.6 127.449 126.72 127.463 ;
     RECT  132 127.449 132.12 127.463 ;
     RECT  137.4 127.449 137.52 127.463 ;
     RECT  142.8 127.449 142.92 127.463 ;
     RECT  148.2 127.449 148.32 127.463 ;
     RECT  153.6 127.449 153.72 127.463 ;
     RECT  159 127.449 159.12 127.463 ;
     RECT  164.4 127.449 164.52 127.463 ;
     RECT  169.8 127.449 169.92 127.463 ;
     RECT  175.2 127.449 175.32 127.463 ;
     RECT  180.6 127.449 180.72 127.463 ;
     RECT  186 127.449 186.12 127.463 ;
     RECT  191.4 127.449 191.52 127.463 ;
     RECT  196.8 127.449 196.92 127.463 ;
     RECT  202.2 127.449 202.32 127.463 ;
     RECT  207.6 127.449 207.72 127.463 ;
     RECT  213 127.449 213.12 127.463 ;
     RECT  218.4 127.449 218.52 127.463 ;
     RECT  223.8 127.449 223.92 127.463 ;
     RECT  229.2 127.449 229.32 127.463 ;
     RECT  234.6 127.449 234.72 127.463 ;
     RECT  240 127.449 240.12 127.463 ;
     RECT  245.4 127.449 245.52 127.463 ;
     RECT  250.8 127.449 250.92 127.463 ;
     RECT  256.2 127.449 256.32 127.463 ;
     RECT  67.32 2.137 68.496 2.151 ;
     RECT  67.512 2.151 68.496 3.349 ;
     RECT  82.344 16.405 83.4 40.883 ;
     RECT  67.512 16.691 68.64 75.299 ;
     RECT  51.312 21.589 52.752 26.819 ;
     RECT  49.56 27.109 51 31.955 ;
     RECT  251.112 39.589 252.528 43.763 ;
     RECT  56.712 40.405 58.176 40.597 ;
     RECT  72.912 40.405 74.112 75.253 ;
     RECT  43.2 40.499 43.224 40.693 ;
     RECT  57.048 40.597 58.176 42.563 ;
     RECT  43.128 40.693 43.224 40.837 ;
     RECT  43.128 40.837 44.496 40.933 ;
     RECT  44.52 40.837 45.6 43.043 ;
     RECT  62.232 40.837 63.696 42.515 ;
     RECT  43.128 40.933 44.448 42.611 ;
     RECT  143.112 40.981 144.576 83.795 ;
     RECT  40.968 42.517 42.432 42.661 ;
     RECT  56.712 42.563 58.176 73.523 ;
     RECT  43.128 42.611 44.496 43.043 ;
     RECT  41.016 42.661 42.432 47.363 ;
     RECT  251.112 43.763 252.408 43.861 ;
     RECT  251.112 43.861 252.384 47.317 ;
     RECT  251.208 47.317 252.384 47.363 ;
     RECT  40.92 47.363 42.432 47.939 ;
     RECT  251.208 47.363 252.36 47.557 ;
     RECT  251.208 47.557 252.336 48.803 ;
     RECT  251.112 48.803 252.336 79.043 ;
     RECT  37.896 49.619 38.52 51.109 ;
     RECT  36.744 50.339 37.872 51.493 ;
     RECT  37.896 51.109 39.312 56.389 ;
     RECT  33.672 54.709 34.8 59.507 ;
     RECT  37.44 55.187 37.872 55.813 ;
     RECT  24.312 55.237 25.584 55.715 ;
     RECT  25.608 55.669 27.024 55.715 ;
     RECT  36.792 55.813 37.872 57.059 ;
     RECT  38.088 56.389 39.312 56.917 ;
     RECT  38.088 56.917 39.168 57.299 ;
     RECT  36.792 57.059 38.064 57.299 ;
     RECT  39.192 57.059 40.2 62.195 ;
     RECT  39.168 62.195 40.2 63.541 ;
     RECT  39.048 63.541 40.2 65.027 ;
     RECT  21.72 71.077 23.136 71.651 ;
     RECT  19.032 71.797 20.496 72.467 ;
     RECT  36.024 71.989 37.536 72.035 ;
     RECT  19.032 72.467 20.52 73.235 ;
     RECT  18.912 73.235 20.52 73.477 ;
     RECT  18.912 73.477 19.968 76.307 ;
     RECT  19.992 73.477 20.52 73.765 ;
     RECT  16.584 73.765 17.904 74.147 ;
     RECT  19.992 73.765 21.072 75.299 ;
     RECT  16.584 74.147 18.096 78.613 ;
     RECT  53.832 74.723 53.976 75.781 ;
     RECT  32.76 74.869 34.176 75.251 ;
     RECT  26.76 75.205 27.936 77.555 ;
     RECT  27.96 75.205 29.4 77.555 ;
     RECT  60.552 75.205 61.8 75.445 ;
     RECT  73.032 75.253 74.112 75.445 ;
     RECT  67.512 75.299 68.664 75.349 ;
     RECT  67.512 75.349 70.08 76.549 ;
     RECT  70.728 75.349 72.096 75.587 ;
     RECT  44.472 75.397 45.6 76.403 ;
     RECT  73.128 75.445 74.112 75.779 ;
     RECT  70.2 75.587 70.536 76.549 ;
     RECT  72.912 75.779 74.112 80.435 ;
     RECT  67.512 76.549 68.544 76.741 ;
     RECT  68.568 76.549 70.08 76.979 ;
     RECT  67.512 76.741 68.496 80.341 ;
     RECT  145.368 76.885 146.88 77.749 ;
     RECT  26.592 77.171 26.736 78.613 ;
     RECT  82.104 77.461 83.4 78.707 ;
     RECT  35.112 77.557 36.192 78.371 ;
     RECT  52.92 77.653 53.952 78.947 ;
     RECT  145.8 77.749 146.88 87.827 ;
     RECT  144.6 77.795 145.776 83.795 ;
     RECT  58.632 78.037 60.096 80.389 ;
     RECT  35.112 78.371 36.216 78.517 ;
     RECT  15.096 78.421 16.56 78.659 ;
     RECT  35.112 78.517 36.384 81.157 ;
     RECT  19.656 78.613 20.976 79.139 ;
     RECT  25.128 78.613 26.208 79.715 ;
     RECT  53.976 78.659 54.408 79.765 ;
     RECT  41.16 78.707 41.208 79.045 ;
     RECT  83.28 78.707 83.4 79.141 ;
     RECT  78.648 78.901 80.16 82.981 ;
     RECT  41.16 79.045 42.144 80.291 ;
     RECT  19.656 79.139 21 79.189 ;
     RECT  19.656 79.189 20.928 80.291 ;
     RECT  20.952 79.189 21 79.621 ;
     RECT  26.76 79.189 28.128 79.715 ;
     RECT  28.152 79.189 29.4 80.917 ;
     RECT  56.712 79.189 58.176 80.917 ;
     RECT  130.536 79.189 132 80.531 ;
     RECT  45.264 79.475 45.6 80.101 ;
     RECT  74.712 79.477 76.08 80.579 ;
     RECT  20.952 79.621 22.368 80.339 ;
     RECT  33.432 79.621 34.8 79.717 ;
     RECT  24.312 79.715 26.208 80.531 ;
     RECT  27.888 79.715 28.128 80.389 ;
     RECT  36.408 79.717 37.488 80.435 ;
     RECT  29.712 79.765 31.104 80.053 ;
     RECT  53.976 79.765 55.248 82.835 ;
     RECT  70.968 79.765 72.096 80.149 ;
     RECT  68.568 79.811 68.616 79.813 ;
     RECT  68.568 79.813 69.792 81.013 ;
     RECT  44.328 80.101 45.6 80.773 ;
     RECT  82.104 80.245 83.28 81.011 ;
     RECT  20.64 80.291 20.928 80.579 ;
     RECT  33.432 80.291 34.8 81.349 ;
     RECT  41.16 80.291 42.864 80.965 ;
     RECT  80.568 80.341 82.08 80.819 ;
     RECT  58.632 80.389 59.904 80.675 ;
     RECT  67.512 80.483 68.496 81.539 ;
     RECT  24.312 80.531 25.464 80.821 ;
     RECT  131.76 80.531 132 80.917 ;
     RECT  20.64 80.579 20.952 81.733 ;
     RECT  58.584 80.675 59.904 80.773 ;
     RECT  58.584 80.773 59.616 81.059 ;
     RECT  25.176 80.821 25.464 81.205 ;
     RECT  76.968 80.821 78 80.963 ;
     RECT  17.016 80.867 18.48 81.011 ;
     RECT  57 80.917 58.176 82.451 ;
     RECT  76.104 80.963 76.2 82.405 ;
     RECT  41.256 80.965 42.864 81.685 ;
     RECT  18.336 81.011 18.48 82.261 ;
     RECT  60.552 81.011 61.584 81.539 ;
     RECT  58.536 81.059 59.616 83.603 ;
     RECT  35.208 81.157 36.384 81.205 ;
     RECT  68.568 81.395 69.648 81.443 ;
     RECT  68.52 81.443 69.648 81.539 ;
     RECT  60.36 81.539 61.584 82.547 ;
     RECT  5.4 81.685 6.624 82.451 ;
     RECT  6.648 81.685 7.8 82.451 ;
     RECT  41.736 81.685 42.864 82.693 ;
     RECT  55.272 81.731 56.4 82.835 ;
     RECT  20.808 81.733 20.952 82.021 ;
     RECT  51.312 82.021 52.56 83.267 ;
     RECT  52.584 82.021 53.952 83.267 ;
     RECT  19.176 82.261 20.64 83.171 ;
     RECT  21.624 82.357 23.04 82.597 ;
     RECT  26.328 82.357 27.792 82.595 ;
     RECT  56.808 82.451 58.176 83.267 ;
     RECT  60.36 82.547 61.68 82.595 ;
     RECT  27.504 82.595 27.792 82.597 ;
     RECT  60.36 82.595 61.8 82.691 ;
     RECT  21.624 82.597 22.944 82.739 ;
     RECT  27.504 82.597 27.696 83.173 ;
     RECT  53.976 82.835 56.4 84.325 ;
     RECT  10.44 83.029 11.808 83.125 ;
     RECT  19.176 83.171 20.976 84.179 ;
     RECT  51.312 83.267 53.952 84.373 ;
     RECT  56.712 83.267 58.176 84.131 ;
     RECT  35.208 83.603 36.288 84.997 ;
     RECT  58.2 83.603 59.616 84.131 ;
     RECT  18.336 83.987 18.48 85.429 ;
     RECT  58.32 84.131 59.616 85.477 ;
     RECT  19.032 84.179 20.976 84.181 ;
     RECT  19.032 84.181 20.4 84.323 ;
     RECT  39.096 84.227 40.08 88.309 ;
     RECT  19.032 84.323 20.496 84.371 ;
     RECT  54.936 84.325 56.4 85.427 ;
     RECT  51.312 84.373 52.416 84.661 ;
     RECT  52.44 84.373 53.952 85.091 ;
     RECT  71.256 84.467 72.6 84.563 ;
     RECT  44.328 84.755 45.312 85.765 ;
     RECT  51.312 84.803 52.416 85.091 ;
     RECT  35.304 84.997 36.288 86.101 ;
     RECT  70.68 85.091 70.776 86.533 ;
     RECT  49.56 85.093 51 85.667 ;
     RECT  36.408 85.427 37.128 86.581 ;
     RECT  56.304 85.427 56.4 85.477 ;
     RECT  58.344 85.477 59.616 87.827 ;
     RECT  6.648 85.525 7.8 86.195 ;
     RECT  21 85.571 21.096 86.677 ;
     RECT  50.544 85.667 51 87.109 ;
     RECT  56.808 85.957 58.32 87.827 ;
     RECT  67.608 86.051 67.656 87.253 ;
     RECT  80.328 86.053 81.648 86.627 ;
     RECT  5.688 86.195 7.8 87.205 ;
     RECT  36.408 86.581 37.584 87.781 ;
     RECT  37.608 86.581 39.072 87.827 ;
     RECT  80.184 86.627 81.648 87.827 ;
     RECT  35.304 86.675 36.288 86.771 ;
     RECT  21 86.677 22.224 86.819 ;
     RECT  24.504 86.725 25.632 86.773 ;
     RECT  35.112 86.771 36.288 87.925 ;
     RECT  21 86.819 22.464 88.403 ;
     RECT  19.272 86.821 20.736 87.253 ;
     RECT  8.952 87.157 9.936 89.941 ;
     RECT  83.712 87.157 84.96 88.595 ;
     RECT  56.304 87.203 56.4 88.309 ;
     RECT  6.504 87.205 7.8 90.083 ;
     RECT  5.4 87.251 6.48 90.083 ;
     RECT  19.464 87.253 20.736 87.683 ;
     RECT  37.08 87.827 39.072 88.405 ;
     RECT  74.52 87.925 75.696 88.885 ;
     RECT  87.816 88.069 88.8 89.941 ;
     RECT  67.608 88.115 67.656 89.413 ;
     RECT  60.36 88.213 61.8 89.699 ;
     RECT  55.32 88.309 56.4 89.125 ;
     RECT  37.08 88.405 38.304 88.547 ;
     RECT  62.952 88.501 64.224 90.323 ;
     RECT  76.632 88.501 78 89.507 ;
     RECT  83.712 88.595 85.2 89.413 ;
     RECT  70.968 88.789 72.24 88.979 ;
     RECT  28.032 88.883 28.128 88.979 ;
     RECT  28.032 88.979 28.224 89.989 ;
     RECT  70.968 88.979 72.6 89.989 ;
     RECT  83.832 89.413 85.2 89.989 ;
     RECT  76.2 89.507 76.344 90.661 ;
     RECT  59.64 89.699 61.8 91.141 ;
     RECT  83.232 89.699 83.28 91.093 ;
     RECT  70.968 89.989 72.48 91.621 ;
     RECT  83.832 89.989 84.96 90.611 ;
     RECT  62.952 90.323 63.288 91.621 ;
     RECT  44.376 90.419 45.6 90.755 ;
     RECT  72.912 90.517 73.92 91.811 ;
     RECT  83.832 90.611 85.536 90.613 ;
     RECT  79.224 90.613 80.592 91.811 ;
     RECT  84.024 90.613 85.536 91.571 ;
     RECT  67.704 90.659 68.376 91.285 ;
     RECT  44.232 90.755 45.6 93.013 ;
     RECT  46.296 91.043 46.92 91.189 ;
     RECT  59.64 91.141 60.624 93.059 ;
     RECT  60.648 91.141 61.8 93.013 ;
     RECT  46.296 91.189 47.424 92.099 ;
     RECT  67.704 91.285 68.976 91.811 ;
     RECT  69 91.285 70.368 91.811 ;
     RECT  36.408 91.621 37.584 91.717 ;
     RECT  37.608 91.621 39.072 92.533 ;
     RECT  30.072 91.667 31.056 94.261 ;
     RECT  36.408 91.717 37.392 94.021 ;
     RECT  27.984 91.763 28.032 92.821 ;
     RECT  24.552 91.811 25.128 93.109 ;
     RECT  67.704 91.811 70.368 92.245 ;
     RECT  72.912 91.811 74.016 93.061 ;
     RECT  76.2 91.811 76.344 92.485 ;
     RECT  79.224 91.811 79.32 92.869 ;
     RECT  67.704 92.245 70.08 92.581 ;
     RECT  62.112 92.435 63.216 95.653 ;
     RECT  83.28 92.435 83.4 93.925 ;
     RECT  76.2 92.485 77.856 92.533 ;
     RECT  76.2 92.533 77.76 92.725 ;
     RECT  15.48 92.581 16.608 92.677 ;
     RECT  67.704 92.581 69.12 92.867 ;
     RECT  76.2 92.725 77.232 95.605 ;
     RECT  26.952 92.821 28.032 93.589 ;
     RECT  44.232 93.013 45.36 93.349 ;
     RECT  60.648 93.013 61.68 93.059 ;
     RECT  25.416 93.109 26.928 93.445 ;
     RECT  25.416 93.445 26.88 93.493 ;
     RECT  25.704 93.493 26.88 94.259 ;
     RECT  70.32 93.539 70.704 94.837 ;
     RECT  61.68 93.779 61.8 94.981 ;
     RECT  51.48 94.165 52.944 94.739 ;
     RECT  25.416 94.259 26.88 94.547 ;
     RECT  36.408 94.499 37.392 96.371 ;
     RECT  51.48 94.739 52.92 95.125 ;
     RECT  32.088 94.883 33.312 95.315 ;
     RECT  59.64 94.981 61.008 97.139 ;
     RECT  21.096 95.029 22.272 95.171 ;
     RECT  15.672 95.075 16.008 96.133 ;
     RECT  51.48 95.125 52.896 96.755 ;
     RECT  21.096 95.171 22.512 96.371 ;
     RECT  50.688 95.219 51 96.565 ;
     RECT  32.088 95.315 33.408 96.901 ;
     RECT  67.704 95.507 68.52 95.557 ;
     RECT  67.704 95.557 68.928 95.795 ;
     RECT  68.952 95.557 70.32 95.795 ;
     RECT  62.112 95.653 63.168 96.419 ;
     RECT  70.968 95.701 72.336 97.909 ;
     RECT  76.2 95.747 77.232 97.957 ;
     RECT  67.704 95.795 67.752 96.469 ;
     RECT  88.704 95.795 88.8 96.901 ;
     RECT  37.608 96.131 38.64 97.763 ;
     RECT  78.744 96.131 79.92 96.899 ;
     RECT  36.408 96.371 37.536 97.717 ;
     RECT  62.112 96.419 63.216 97.573 ;
     RECT  66.096 96.419 67.056 96.613 ;
     RECT  49.8 96.565 51 97.907 ;
     RECT  65.784 96.613 67.056 98.435 ;
     RECT  78.696 96.899 79.92 97.187 ;
     RECT  32.232 96.901 33.408 99.731 ;
     RECT  87.816 96.901 88.8 98.099 ;
     RECT  78.648 97.187 79.92 101.507 ;
     RECT  59.28 97.235 59.616 98.581 ;
     RECT  35.256 97.475 36.288 99.395 ;
     RECT  37.56 97.763 38.64 98.339 ;
     RECT  36.408 97.907 37.536 99.491 ;
     RECT  70.968 97.909 72.048 99.203 ;
     RECT  69.576 98.005 70.944 99.587 ;
     RECT  13.656 98.051 14.688 99.971 ;
     RECT  22.728 98.243 24 100.261 ;
     RECT  37.56 98.339 39.072 99.251 ;
     RECT  62.112 98.675 63.216 99.491 ;
     RECT  76.056 98.915 77.232 99.925 ;
     RECT  28.152 98.963 29.136 99.779 ;
     RECT  70.968 99.203 72.336 103.235 ;
     RECT  74.52 99.203 75.648 102.611 ;
     RECT  35.256 99.395 36.336 99.443 ;
     RECT  35.112 99.443 36.336 104.147 ;
     RECT  36.408 99.491 37.32 99.685 ;
     RECT  28.152 99.779 29.28 100.789 ;
     RECT  59.256 99.827 59.304 100.885 ;
     RECT  76.056 99.925 77.184 100.019 ;
     RECT  13.656 99.971 15.072 100.933 ;
     RECT  75.816 100.019 77.184 100.021 ;
     RECT  75.816 100.021 76.896 100.931 ;
     RECT  22.92 100.261 24 101.507 ;
     RECT  28.152 100.789 29.232 101.317 ;
     RECT  67.056 100.883 67.2 101.845 ;
     RECT  75.672 100.931 76.896 102.421 ;
     RECT  13.752 100.933 15.072 101.605 ;
     RECT  79.944 101.269 81.456 102.659 ;
     RECT  22.632 101.507 24 103.189 ;
     RECT  78.552 101.507 79.92 102.515 ;
     RECT  28.152 101.651 29.184 102.949 ;
     RECT  46.296 102.035 46.536 103.141 ;
     RECT  51.312 102.179 52.296 102.229 ;
     RECT  51.312 102.229 52.32 105.349 ;
     RECT  39.216 102.371 39.504 103.429 ;
     RECT  78.408 102.515 79.92 103.235 ;
     RECT  30.84 102.611 31.92 107.507 ;
     RECT  18.24 102.659 18.336 102.661 ;
     RECT  79.944 102.659 80.136 103.235 ;
     RECT  17.112 102.661 18.336 102.803 ;
     RECT  16.824 102.803 18.336 104.003 ;
     RECT  27.144 102.851 28.128 104.869 ;
     RECT  68.52 103.093 69.84 103.475 ;
     RECT  21.696 103.139 22.608 103.381 ;
     RECT  69.864 103.187 70.944 103.235 ;
     RECT  80.112 103.235 80.136 103.621 ;
     RECT  19.368 103.381 20.832 105.973 ;
     RECT  21.192 103.381 22.608 103.763 ;
     RECT  56.712 103.381 58.128 104.243 ;
     RECT  38.52 103.571 39.504 106.979 ;
     RECT  78.312 103.571 78.408 104.869 ;
     RECT  28.152 103.715 29.184 105.445 ;
     RECT  29.712 103.907 30.816 105.973 ;
     RECT  22.632 104.243 24 108.229 ;
     RECT  32.184 104.867 32.232 104.869 ;
     RECT  32.184 104.869 33.696 105.491 ;
     RECT  78.696 104.869 80.112 104.963 ;
     RECT  72.912 104.915 74.064 105.877 ;
     RECT  78.696 104.963 79.512 105.397 ;
     RECT  27.144 105.059 28.128 105.491 ;
     RECT  49.704 105.397 51 106.163 ;
     RECT  69.864 105.397 71.28 106.067 ;
     RECT  71.304 105.397 72.336 106.067 ;
     RECT  28.152 105.445 29.136 105.971 ;
     RECT  27.096 105.491 28.128 110.917 ;
     RECT  78.312 105.491 79.488 106.643 ;
     RECT  72.912 105.877 74.016 107.797 ;
     RECT  28.152 105.971 29.184 106.211 ;
     RECT  16.824 105.973 18.192 106.643 ;
     RECT  74.52 105.973 75.552 106.787 ;
     RECT  40.512 106.067 41.712 107.029 ;
     RECT  51.312 106.067 52.368 110.051 ;
     RECT  19.368 106.115 20.832 106.739 ;
     RECT  28.152 106.211 29.232 106.739 ;
     RECT  20.856 106.213 22.32 107.557 ;
     RECT  78.312 106.643 78.408 106.741 ;
     RECT  18.912 106.739 20.832 108.229 ;
     RECT  28.152 106.739 29.28 108.853 ;
     RECT  74.52 106.787 75.144 107.701 ;
     RECT  38.52 106.979 40.08 107.413 ;
     RECT  37.08 106.981 38.496 107.173 ;
     RECT  40.728 107.029 41.712 108.565 ;
     RECT  37.08 107.173 38.208 107.557 ;
     RECT  25.176 107.317 26.592 108.277 ;
     RECT  38.664 107.413 40.08 109.381 ;
     RECT  30.84 107.507 31.968 107.651 ;
     RECT  20.856 107.557 21.984 107.749 ;
     RECT  30.84 107.651 32.064 108.613 ;
     RECT  20.952 107.987 21.984 108.851 ;
     RECT  18.912 108.229 20.4 108.851 ;
     RECT  22.68 108.229 24 108.851 ;
     RECT  25.224 108.277 26.592 108.565 ;
     RECT  25.32 108.565 26.592 109.141 ;
     RECT  29.928 108.659 31.296 110.485 ;
     RECT  21.696 108.851 21.984 109.621 ;
     RECT  22.008 108.851 24 109.381 ;
     RECT  40.728 109.091 41.712 111.157 ;
     RECT  25.32 109.283 26.592 109.715 ;
     RECT  22.008 109.381 23.28 110.531 ;
     RECT  38.664 109.381 40.032 110.869 ;
     RECT  17.016 109.477 18.48 110.725 ;
     RECT  25.224 109.715 26.592 112.691 ;
     RECT  34.176 110.195 34.704 111.301 ;
     RECT  29.976 110.485 31.296 111.157 ;
     RECT  22.008 110.531 24 110.627 ;
     RECT  22.416 110.627 24 110.629 ;
     RECT  22.44 110.629 24 111.733 ;
     RECT  17.016 110.725 18.192 113.365 ;
     RECT  38.712 110.869 40.032 112.115 ;
     RECT  11.016 111.011 12.192 114.851 ;
     RECT  28.152 111.251 29.4 113.459 ;
     RECT  34.176 111.301 34.272 111.445 ;
     RECT  30.312 111.443 31.296 112.741 ;
     RECT  33.096 111.445 34.272 111.541 ;
     RECT  33.096 111.541 34.176 111.685 ;
     RECT  35.256 111.683 35.928 113.173 ;
     RECT  22.44 111.733 23.856 111.925 ;
     RECT  40.728 111.827 41.76 113.219 ;
     RECT  22.44 111.925 23.52 113.125 ;
     RECT  38.712 112.115 40.2 112.741 ;
     RECT  16.704 112.691 16.992 113.989 ;
     RECT  25.128 112.691 26.592 113.075 ;
     RECT  39.144 112.741 40.2 114.275 ;
     RECT  22.44 113.125 23.472 114.083 ;
     RECT  12.216 113.171 13.2 114.851 ;
     RECT  35.256 113.173 36.576 113.315 ;
     RECT  40.728 113.219 41.856 114.277 ;
     RECT  35.208 113.315 36.576 117.349 ;
     RECT  18.912 113.365 20.208 114.517 ;
     RECT  29.28 113.459 29.4 114.421 ;
     RECT  15.576 113.989 16.992 114.131 ;
     RECT  22.44 114.083 23.856 114.227 ;
     RECT  38.808 114.275 40.2 114.371 ;
     RECT  38.712 114.371 40.2 114.611 ;
     RECT  17.592 114.419 18.6 114.707 ;
     RECT  40.872 114.467 41.856 114.611 ;
     RECT  19.032 114.517 20.208 115.573 ;
     RECT  38.232 114.611 40.2 114.661 ;
     RECT  40.872 114.611 42.288 115.043 ;
     RECT  38.232 114.661 40.08 114.803 ;
     RECT  37.992 114.803 40.08 115.187 ;
     RECT  32.184 114.853 33.6 115.139 ;
     RECT  42.192 115.043 42.288 115.573 ;
     RECT  32.184 115.139 33.984 115.187 ;
     RECT  32.184 115.187 34.704 115.763 ;
     RECT  37.512 115.187 40.08 115.813 ;
     RECT  44.616 115.187 45.6 116.147 ;
     RECT  32.088 115.763 34.704 116.149 ;
     RECT  37.512 115.813 38.784 116.389 ;
     RECT  38.808 115.813 40.08 116.293 ;
     RECT  44.568 116.147 45.6 117.349 ;
     RECT  32.088 116.149 34.32 116.245 ;
     RECT  13.512 116.195 14.784 116.867 ;
     RECT  27.912 116.197 29.28 116.341 ;
     RECT  32.088 116.245 33.168 116.627 ;
     RECT  33.192 116.245 34.32 116.579 ;
     RECT  38.808 116.293 39.984 116.627 ;
     RECT  43.08 116.339 44.112 116.867 ;
     RECT  27.912 116.341 29.04 116.531 ;
     RECT  37.608 116.389 38.784 116.627 ;
     RECT  33.192 116.579 34.704 116.675 ;
     RECT  29.136 116.627 29.4 117.637 ;
     RECT  33.072 116.627 33.168 117.925 ;
     RECT  37.608 116.627 39.984 116.771 ;
     RECT  37.608 116.771 40.2 117.109 ;
     RECT  23.28 116.819 24 117.925 ;
     RECT  43.08 116.867 44.208 117.299 ;
     RECT  38.232 117.109 40.2 117.299 ;
     RECT  39.552 117.299 40.2 117.925 ;
     RECT  35.208 117.349 36.528 117.925 ;
     RECT  18.912 117.443 20.208 117.827 ;
     RECT  23.016 117.925 24 118.595 ;
     RECT  12.024 118.259 13.056 119.171 ;
     RECT  35.208 118.547 36.576 119.987 ;
     RECT  35.112 119.987 36.576 123.731 ;
     RECT  30.072 120.229 31.584 120.611 ;
  END
END dsdv_mu_hslot
END LIBRARY
